VERSION 5.7 ;
  NOWIREEXTENSIONATPIN ON ;
  DIVIDERCHAR "/" ;
  BUSBITCHARS "[]" ;
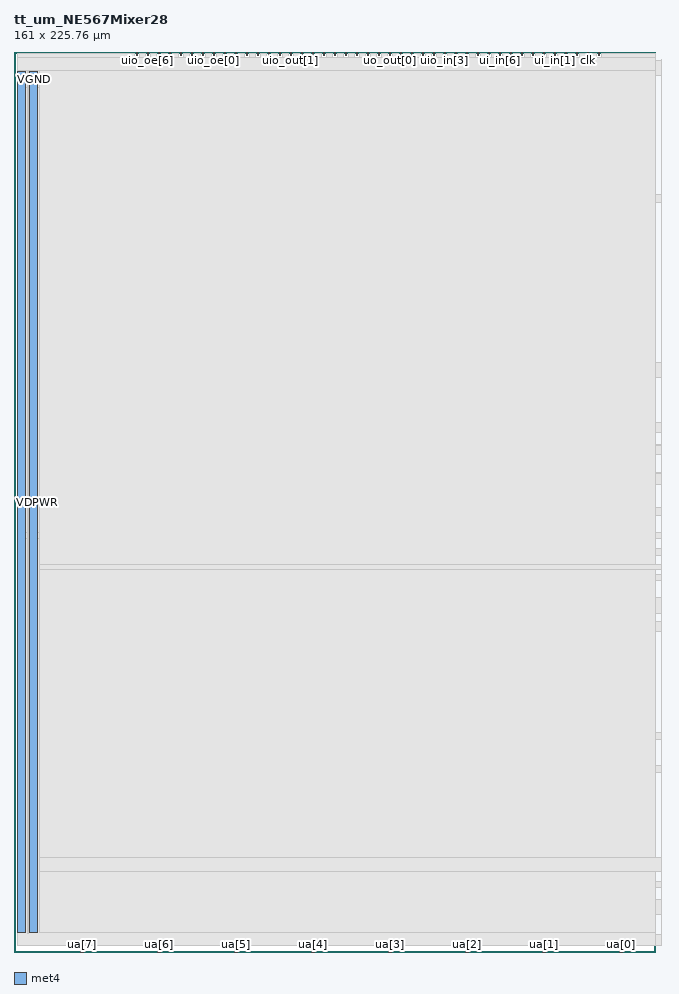
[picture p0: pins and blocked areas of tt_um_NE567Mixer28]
MACRO tt_um_NE567Mixer28
  CLASS BLOCK ;
  FOREIGN tt_um_NE567Mixer28 ;
  ORIGIN 0.000 0.000 ;
  SIZE 161.000 BY 225.760 ;
  PIN clk
    DIRECTION INPUT ;
    USE SIGNAL ;
    PORT
      LAYER met4 ;
        RECT 143.830 224.760 144.130 225.760 ;
    END
  END clk
  PIN ena
    DIRECTION INPUT ;
    USE SIGNAL ;
    PORT
      LAYER met4 ;
        RECT 146.590 224.760 146.890 225.760 ;
    END
  END ena
  PIN rst_n
    DIRECTION INPUT ;
    USE SIGNAL ;
    PORT
      LAYER met4 ;
        RECT 141.070 224.760 141.370 225.760 ;
    END
  END rst_n
  PIN ua[0]
    DIRECTION INOUT ;
    USE SIGNAL ;
    ANTENNADIFFAREA 2.320000 ;
    PORT
      LAYER met4 ;
        RECT 151.810 0.000 152.710 1.000 ;
    END
  END ua[0]
  PIN ua[1]
    DIRECTION INOUT ;
    USE SIGNAL ;
    ANTENNAGATEAREA 500.000000 ;
    PORT
      LAYER met4 ;
        RECT 132.490 0.000 133.390 1.000 ;
    END
  END ua[1]
  PIN ua[2]
    DIRECTION INOUT ;
    USE SIGNAL ;
    PORT
      LAYER met4 ;
        RECT 113.170 0.000 114.070 1.000 ;
    END
  END ua[2]
  PIN ua[3]
    DIRECTION INOUT ;
    USE SIGNAL ;
    ANTENNADIFFAREA 2.320000 ;
    PORT
      LAYER met4 ;
        RECT 93.850 0.000 94.750 1.000 ;
    END
  END ua[3]
  PIN ua[4]
    DIRECTION INOUT ;
    USE SIGNAL ;
    ANTENNAGATEAREA 500.000000 ;
    PORT
      LAYER met4 ;
        RECT 74.530 0.000 75.430 1.000 ;
    END
  END ua[4]
  PIN ua[5]
    DIRECTION INOUT ;
    USE SIGNAL ;
    ANTENNAGATEAREA 500.000000 ;
    PORT
      LAYER met4 ;
        RECT 55.210 0.000 56.110 1.000 ;
    END
  END ua[5]
  PIN ua[6]
    DIRECTION INOUT ;
    USE SIGNAL ;
    PORT
      LAYER met4 ;
        RECT 35.890 0.000 36.790 1.000 ;
    END
  END ua[6]
  PIN ua[7]
    DIRECTION INOUT ;
    USE SIGNAL ;
    PORT
      LAYER met4 ;
        RECT 16.570 0.000 17.470 1.000 ;
    END
  END ua[7]
  PIN ui_in[0]
    DIRECTION INPUT ;
    USE SIGNAL ;
    PORT
      LAYER met4 ;
        RECT 138.310 224.760 138.610 225.760 ;
    END
  END ui_in[0]
  PIN ui_in[1]
    DIRECTION INPUT ;
    USE SIGNAL ;
    PORT
      LAYER met4 ;
        RECT 135.550 224.760 135.850 225.760 ;
    END
  END ui_in[1]
  PIN ui_in[2]
    DIRECTION INPUT ;
    USE SIGNAL ;
    PORT
      LAYER met4 ;
        RECT 132.790 224.760 133.090 225.760 ;
    END
  END ui_in[2]
  PIN ui_in[3]
    DIRECTION INPUT ;
    USE SIGNAL ;
    PORT
      LAYER met4 ;
        RECT 130.030 224.760 130.330 225.760 ;
    END
  END ui_in[3]
  PIN ui_in[4]
    DIRECTION INPUT ;
    USE SIGNAL ;
    PORT
      LAYER met4 ;
        RECT 127.270 224.760 127.570 225.760 ;
    END
  END ui_in[4]
  PIN ui_in[5]
    DIRECTION INPUT ;
    USE SIGNAL ;
    PORT
      LAYER met4 ;
        RECT 124.510 224.760 124.810 225.760 ;
    END
  END ui_in[5]
  PIN ui_in[6]
    DIRECTION INPUT ;
    USE SIGNAL ;
    PORT
      LAYER met4 ;
        RECT 121.750 224.760 122.050 225.760 ;
    END
  END ui_in[6]
  PIN ui_in[7]
    DIRECTION INPUT ;
    USE SIGNAL ;
    PORT
      LAYER met4 ;
        RECT 118.990 224.760 119.290 225.760 ;
    END
  END ui_in[7]
  PIN uio_in[0]
    DIRECTION INPUT ;
    USE SIGNAL ;
    PORT
      LAYER met4 ;
        RECT 116.230 224.760 116.530 225.760 ;
    END
  END uio_in[0]
  PIN uio_in[1]
    DIRECTION INPUT ;
    USE SIGNAL ;
    PORT
      LAYER met4 ;
        RECT 113.470 224.760 113.770 225.760 ;
    END
  END uio_in[1]
  PIN uio_in[2]
    DIRECTION INPUT ;
    USE SIGNAL ;
    PORT
      LAYER met4 ;
        RECT 110.710 224.760 111.010 225.760 ;
    END
  END uio_in[2]
  PIN uio_in[3]
    DIRECTION INPUT ;
    USE SIGNAL ;
    PORT
      LAYER met4 ;
        RECT 107.950 224.760 108.250 225.760 ;
    END
  END uio_in[3]
  PIN uio_in[4]
    DIRECTION INPUT ;
    USE SIGNAL ;
    PORT
      LAYER met4 ;
        RECT 105.190 224.760 105.490 225.760 ;
    END
  END uio_in[4]
  PIN uio_in[5]
    DIRECTION INPUT ;
    USE SIGNAL ;
    PORT
      LAYER met4 ;
        RECT 102.430 224.760 102.730 225.760 ;
    END
  END uio_in[5]
  PIN uio_in[6]
    DIRECTION INPUT ;
    USE SIGNAL ;
    PORT
      LAYER met4 ;
        RECT 99.670 224.760 99.970 225.760 ;
    END
  END uio_in[6]
  PIN uio_in[7]
    DIRECTION INPUT ;
    USE SIGNAL ;
    PORT
      LAYER met4 ;
        RECT 96.910 224.760 97.210 225.760 ;
    END
  END uio_in[7]
  PIN uio_oe[0]
    DIRECTION OUTPUT ;
    USE SIGNAL ;
    ANTENNADIFFAREA 242.234787 ;
    PORT
      LAYER met4 ;
        RECT 49.990 224.760 50.290 225.760 ;
    END
  END uio_oe[0]
  PIN uio_oe[1]
    DIRECTION OUTPUT ;
    USE SIGNAL ;
    ANTENNADIFFAREA 242.234787 ;
    PORT
      LAYER met4 ;
        RECT 47.230 224.760 47.530 225.760 ;
    END
  END uio_oe[1]
  PIN uio_oe[2]
    DIRECTION OUTPUT ;
    USE SIGNAL ;
    ANTENNADIFFAREA 242.234787 ;
    PORT
      LAYER met4 ;
        RECT 44.470 224.760 44.770 225.760 ;
    END
  END uio_oe[2]
  PIN uio_oe[3]
    DIRECTION OUTPUT ;
    USE SIGNAL ;
    ANTENNADIFFAREA 242.234787 ;
    PORT
      LAYER met4 ;
        RECT 41.710 224.760 42.010 225.760 ;
    END
  END uio_oe[3]
  PIN uio_oe[4]
    DIRECTION OUTPUT ;
    USE SIGNAL ;
    ANTENNADIFFAREA 242.234787 ;
    PORT
      LAYER met4 ;
        RECT 38.950 224.760 39.250 225.760 ;
    END
  END uio_oe[4]
  PIN uio_oe[5]
    DIRECTION OUTPUT ;
    USE SIGNAL ;
    ANTENNADIFFAREA 242.234787 ;
    PORT
      LAYER met4 ;
        RECT 36.190 224.760 36.490 225.760 ;
    END
  END uio_oe[5]
  PIN uio_oe[6]
    DIRECTION OUTPUT ;
    USE SIGNAL ;
    ANTENNADIFFAREA 242.234787 ;
    PORT
      LAYER met4 ;
        RECT 33.430 224.760 33.730 225.760 ;
    END
  END uio_oe[6]
  PIN uio_oe[7]
    DIRECTION OUTPUT ;
    USE SIGNAL ;
    ANTENNADIFFAREA 242.234787 ;
    PORT
      LAYER met4 ;
        RECT 30.670 224.760 30.970 225.760 ;
    END
  END uio_oe[7]
  PIN uio_out[0]
    DIRECTION OUTPUT ;
    USE SIGNAL ;
    ANTENNADIFFAREA 242.234787 ;
    PORT
      LAYER met4 ;
        RECT 72.070 224.760 72.370 225.760 ;
    END
  END uio_out[0]
  PIN uio_out[1]
    DIRECTION OUTPUT ;
    USE SIGNAL ;
    ANTENNADIFFAREA 242.234787 ;
    PORT
      LAYER met4 ;
        RECT 69.310 224.760 69.610 225.760 ;
    END
  END uio_out[1]
  PIN uio_out[2]
    DIRECTION OUTPUT ;
    USE SIGNAL ;
    ANTENNADIFFAREA 242.234787 ;
    PORT
      LAYER met4 ;
        RECT 66.550 224.760 66.850 225.760 ;
    END
  END uio_out[2]
  PIN uio_out[3]
    DIRECTION OUTPUT ;
    USE SIGNAL ;
    ANTENNADIFFAREA 242.234787 ;
    PORT
      LAYER met4 ;
        RECT 63.790 224.760 64.090 225.760 ;
    END
  END uio_out[3]
  PIN uio_out[4]
    DIRECTION OUTPUT ;
    USE SIGNAL ;
    ANTENNADIFFAREA 242.234787 ;
    PORT
      LAYER met4 ;
        RECT 61.030 224.760 61.330 225.760 ;
    END
  END uio_out[4]
  PIN uio_out[5]
    DIRECTION OUTPUT ;
    USE SIGNAL ;
    ANTENNADIFFAREA 242.234787 ;
    PORT
      LAYER met4 ;
        RECT 58.270 224.760 58.570 225.760 ;
    END
  END uio_out[5]
  PIN uio_out[6]
    DIRECTION OUTPUT ;
    USE SIGNAL ;
    ANTENNADIFFAREA 242.234787 ;
    PORT
      LAYER met4 ;
        RECT 55.510 224.760 55.810 225.760 ;
    END
  END uio_out[6]
  PIN uio_out[7]
    DIRECTION OUTPUT ;
    USE SIGNAL ;
    ANTENNADIFFAREA 242.234787 ;
    PORT
      LAYER met4 ;
        RECT 52.750 224.760 53.050 225.760 ;
    END
  END uio_out[7]
  PIN uo_out[0]
    DIRECTION OUTPUT ;
    USE SIGNAL ;
    ANTENNADIFFAREA 242.234787 ;
    PORT
      LAYER met4 ;
        RECT 94.150 224.760 94.450 225.760 ;
    END
  END uo_out[0]
  PIN uo_out[1]
    DIRECTION OUTPUT ;
    USE SIGNAL ;
    ANTENNADIFFAREA 242.234787 ;
    PORT
      LAYER met4 ;
        RECT 91.390 224.760 91.690 225.760 ;
    END
  END uo_out[1]
  PIN uo_out[2]
    DIRECTION OUTPUT ;
    USE SIGNAL ;
    ANTENNADIFFAREA 242.234787 ;
    PORT
      LAYER met4 ;
        RECT 88.630 224.760 88.930 225.760 ;
    END
  END uo_out[2]
  PIN uo_out[3]
    DIRECTION OUTPUT ;
    USE SIGNAL ;
    ANTENNADIFFAREA 242.234787 ;
    PORT
      LAYER met4 ;
        RECT 85.870 224.760 86.170 225.760 ;
    END
  END uo_out[3]
  PIN uo_out[4]
    DIRECTION OUTPUT ;
    USE SIGNAL ;
    ANTENNADIFFAREA 242.234787 ;
    PORT
      LAYER met4 ;
        RECT 83.110 224.760 83.410 225.760 ;
    END
  END uo_out[4]
  PIN uo_out[5]
    DIRECTION OUTPUT ;
    USE SIGNAL ;
    ANTENNADIFFAREA 242.234787 ;
    PORT
      LAYER met4 ;
        RECT 80.350 224.760 80.650 225.760 ;
    END
  END uo_out[5]
  PIN uo_out[6]
    DIRECTION OUTPUT ;
    USE SIGNAL ;
    ANTENNADIFFAREA 242.234787 ;
    PORT
      LAYER met4 ;
        RECT 77.590 224.760 77.890 225.760 ;
    END
  END uo_out[6]
  PIN uo_out[7]
    DIRECTION OUTPUT ;
    USE SIGNAL ;
    ANTENNADIFFAREA 242.234787 ;
    PORT
      LAYER met4 ;
        RECT 74.830 224.760 75.130 225.760 ;
    END
  END uo_out[7]
  PIN VDPWR
    DIRECTION INOUT ;
    USE POWER ;
    PORT
      LAYER met4 ;
        RECT 1.000 5.000 3.000 220.760 ;
    END
  END VDPWR
  PIN VGND
    DIRECTION INOUT ;
    USE GROUND ;
    PORT
      LAYER met4 ;
        RECT 4.000 5.000 6.000 220.760 ;
    END
  END VGND
  OBS
      LAYER nwell ;
        RECT 40.830 17.360 161.000 218.560 ;
        RECT 252.020 207.610 275.390 217.020 ;
        RECT 281.650 214.020 287.690 218.210 ;
        RECT 303.010 213.970 309.050 218.160 ;
        RECT 281.700 207.940 287.890 212.130 ;
        RECT 302.900 207.780 309.090 211.970 ;
        RECT 481.630 207.960 505.000 217.370 ;
        RECT 511.260 214.370 517.300 218.560 ;
        RECT 532.620 214.320 538.660 218.510 ;
        RECT 511.310 208.290 517.500 212.480 ;
        RECT 532.510 208.130 538.700 212.320 ;
        RECT 252.050 180.340 280.420 202.590 ;
        RECT 291.650 180.340 320.020 202.590 ;
      LAYER pwell ;
        RECT 332.250 187.840 339.870 189.850 ;
      LAYER nwell ;
        RECT 481.660 180.690 510.030 202.940 ;
        RECT 521.260 180.690 549.630 202.940 ;
      LAYER pwell ;
        RECT 315.970 171.330 322.070 174.290 ;
        RECT 255.350 167.560 261.450 170.520 ;
        RECT 316.690 165.170 321.590 168.130 ;
        RECT 256.060 160.210 260.960 163.170 ;
        RECT 388.485 161.445 390.495 178.265 ;
        RECT 398.200 161.320 400.210 178.140 ;
        RECT 409.950 161.430 411.960 178.250 ;
        RECT 421.470 161.430 423.480 178.250 ;
        RECT 545.580 171.680 551.680 174.640 ;
        RECT 484.960 167.910 491.060 170.870 ;
        RECT 546.300 165.520 551.200 168.480 ;
        RECT 485.670 160.560 490.570 163.520 ;
        RECT 476.830 135.670 493.650 137.680 ;
        RECT 497.240 135.660 514.060 137.670 ;
        RECT 517.850 135.600 534.670 137.610 ;
        RECT 539.040 135.720 555.860 137.730 ;
        RECT 742.190 123.910 759.010 125.920 ;
        RECT 764.250 123.840 781.070 125.850 ;
        RECT 786.090 123.840 802.910 125.850 ;
        RECT 806.680 123.780 823.500 125.790 ;
      LAYER nwell ;
        RECT 300.530 73.270 323.900 82.680 ;
        RECT 330.160 79.680 336.200 83.870 ;
        RECT 351.520 79.630 357.560 83.820 ;
        RECT 330.210 73.600 336.400 77.790 ;
        RECT 351.410 73.440 357.600 77.630 ;
        RECT 574.920 73.120 598.290 82.530 ;
        RECT 604.550 79.530 610.590 83.720 ;
        RECT 625.910 79.480 631.950 83.670 ;
        RECT 604.600 73.450 610.790 77.640 ;
        RECT 625.800 73.290 631.990 77.480 ;
        RECT 766.380 73.120 789.750 82.530 ;
        RECT 796.010 79.530 802.050 83.720 ;
        RECT 817.370 79.480 823.410 83.670 ;
        RECT 796.060 73.450 802.250 77.640 ;
        RECT 817.260 73.290 823.450 77.480 ;
        RECT 300.560 46.000 328.930 68.250 ;
        RECT 340.160 46.000 368.530 68.250 ;
      LAYER pwell ;
        RECT 394.100 55.560 396.110 63.180 ;
      LAYER nwell ;
        RECT 574.950 45.850 603.320 68.100 ;
        RECT 614.550 45.850 642.920 68.100 ;
        RECT 766.410 45.850 794.780 68.100 ;
        RECT 806.010 45.850 834.380 68.100 ;
      LAYER pwell ;
        RECT 169.290 28.140 171.300 44.960 ;
        RECT 177.615 27.875 179.625 44.695 ;
        RECT 188.160 27.950 190.170 44.770 ;
        RECT 364.480 36.990 370.580 39.950 ;
        RECT 638.870 36.840 644.970 39.800 ;
        RECT 303.860 33.220 309.960 36.180 ;
        RECT 365.200 30.830 370.100 33.790 ;
        RECT 578.250 33.070 584.350 36.030 ;
        RECT 675.655 34.705 684.175 42.095 ;
        RECT 830.330 36.840 836.430 39.800 ;
        RECT 639.590 30.680 644.490 33.640 ;
        RECT 769.710 33.070 775.810 36.030 ;
        RECT 831.050 30.680 835.950 33.640 ;
        RECT 304.570 25.870 309.470 28.830 ;
        RECT 424.330 24.850 435.150 26.860 ;
        RECT 457.530 24.780 468.350 26.790 ;
        RECT 486.210 24.780 497.030 26.790 ;
        RECT 527.110 24.710 537.930 26.720 ;
        RECT 578.960 25.720 583.860 28.680 ;
        RECT 770.420 25.720 775.320 28.680 ;
        RECT 424.310 17.360 443.330 19.370 ;
        RECT 457.600 17.430 466.490 19.440 ;
        RECT 486.120 17.500 505.140 19.510 ;
        RECT 527.190 17.580 534.610 19.590 ;
      LAYER li1 ;
        RECT 40.940 17.450 161.000 218.680 ;
        RECT 513.580 218.380 514.770 218.680 ;
        RECT 283.970 218.030 285.160 218.330 ;
        RECT 511.440 218.210 517.120 218.380 ;
        RECT 535.090 218.330 536.270 218.410 ;
        RECT 281.830 217.860 287.510 218.030 ;
        RECT 305.480 217.980 306.660 218.060 ;
        RECT 270.600 216.840 272.580 216.970 ;
        RECT 252.200 216.670 275.210 216.840 ;
        RECT 252.200 207.960 252.370 216.670 ;
        RECT 270.600 216.570 272.580 216.670 ;
        RECT 253.095 216.100 263.135 216.270 ;
        RECT 264.275 216.100 274.315 216.270 ;
        RECT 252.710 215.040 252.880 216.040 ;
        RECT 263.350 215.040 263.520 216.040 ;
        RECT 263.890 215.040 264.060 216.040 ;
        RECT 274.530 215.040 274.700 216.040 ;
        RECT 253.095 214.810 263.135 214.980 ;
        RECT 264.275 214.810 274.315 214.980 ;
        RECT 252.710 213.750 252.880 214.750 ;
        RECT 263.350 213.750 263.520 214.750 ;
        RECT 263.890 213.750 264.060 214.750 ;
        RECT 274.530 213.750 274.700 214.750 ;
        RECT 253.095 213.520 263.135 213.690 ;
        RECT 264.275 213.520 274.315 213.690 ;
        RECT 252.710 212.460 252.880 213.460 ;
        RECT 263.350 212.460 263.520 213.460 ;
        RECT 263.890 212.460 264.060 213.460 ;
        RECT 274.530 212.460 274.700 213.460 ;
        RECT 253.095 212.230 263.135 212.400 ;
        RECT 264.275 212.230 274.315 212.400 ;
        RECT 252.710 211.170 252.880 212.170 ;
        RECT 263.350 211.170 263.520 212.170 ;
        RECT 263.890 211.170 264.060 212.170 ;
        RECT 274.530 211.170 274.700 212.170 ;
        RECT 253.095 210.940 263.135 211.110 ;
        RECT 264.275 210.940 274.315 211.110 ;
        RECT 252.710 209.880 252.880 210.880 ;
        RECT 263.350 209.880 263.520 210.880 ;
        RECT 263.890 209.880 264.060 210.880 ;
        RECT 274.530 209.880 274.700 210.880 ;
        RECT 253.095 209.650 263.135 209.820 ;
        RECT 264.275 209.650 274.315 209.820 ;
        RECT 252.710 208.590 252.880 209.590 ;
        RECT 263.350 208.590 263.520 209.590 ;
        RECT 263.890 208.590 264.060 209.590 ;
        RECT 274.530 208.590 274.700 209.590 ;
        RECT 253.095 208.360 263.135 208.530 ;
        RECT 264.275 208.360 274.315 208.530 ;
        RECT 275.040 207.960 275.210 216.670 ;
        RECT 281.830 214.370 282.000 217.860 ;
        RECT 283.970 217.740 285.160 217.860 ;
        RECT 282.725 217.290 286.615 217.460 ;
        RECT 282.340 215.000 282.510 217.230 ;
        RECT 286.830 215.000 287.000 217.230 ;
        RECT 282.725 214.770 286.615 214.940 ;
        RECT 287.340 214.370 287.510 217.860 ;
        RECT 281.830 214.200 287.510 214.370 ;
        RECT 303.190 217.810 308.870 217.980 ;
        RECT 303.190 214.320 303.360 217.810 ;
        RECT 305.480 217.730 306.660 217.810 ;
        RECT 304.085 217.240 307.975 217.410 ;
        RECT 303.700 214.950 303.870 217.180 ;
        RECT 308.190 214.950 308.360 217.180 ;
        RECT 304.085 214.720 307.975 214.890 ;
        RECT 308.700 214.320 308.870 217.810 ;
        RECT 500.210 217.190 502.190 217.320 ;
        RECT 303.190 214.150 308.870 214.320 ;
        RECT 481.810 217.020 504.820 217.190 ;
        RECT 284.100 211.950 285.250 212.050 ;
        RECT 281.880 211.780 287.710 211.950 ;
        RECT 305.260 211.790 306.630 211.860 ;
        RECT 281.880 208.290 282.050 211.780 ;
        RECT 284.100 211.700 285.250 211.780 ;
        RECT 282.775 211.210 286.815 211.380 ;
        RECT 282.390 208.920 282.560 211.150 ;
        RECT 287.030 208.920 287.200 211.150 ;
        RECT 282.775 208.690 286.815 208.860 ;
        RECT 287.540 208.290 287.710 211.780 ;
        RECT 281.880 208.120 287.710 208.290 ;
        RECT 303.080 211.620 308.910 211.790 ;
        RECT 303.080 208.130 303.250 211.620 ;
        RECT 305.260 211.490 306.630 211.620 ;
        RECT 303.975 211.050 308.015 211.220 ;
        RECT 303.590 208.760 303.760 210.990 ;
        RECT 308.230 208.760 308.400 210.990 ;
        RECT 303.975 208.530 308.015 208.700 ;
        RECT 308.740 208.130 308.910 211.620 ;
        RECT 481.810 208.310 481.980 217.020 ;
        RECT 500.210 216.920 502.190 217.020 ;
        RECT 482.705 216.450 492.745 216.620 ;
        RECT 493.885 216.450 503.925 216.620 ;
        RECT 482.320 215.390 482.490 216.390 ;
        RECT 492.960 215.390 493.130 216.390 ;
        RECT 493.500 215.390 493.670 216.390 ;
        RECT 504.140 215.390 504.310 216.390 ;
        RECT 482.705 215.160 492.745 215.330 ;
        RECT 493.885 215.160 503.925 215.330 ;
        RECT 482.320 214.100 482.490 215.100 ;
        RECT 492.960 214.100 493.130 215.100 ;
        RECT 493.500 214.100 493.670 215.100 ;
        RECT 504.140 214.100 504.310 215.100 ;
        RECT 482.705 213.870 492.745 214.040 ;
        RECT 493.885 213.870 503.925 214.040 ;
        RECT 482.320 212.810 482.490 213.810 ;
        RECT 492.960 212.810 493.130 213.810 ;
        RECT 493.500 212.810 493.670 213.810 ;
        RECT 504.140 212.810 504.310 213.810 ;
        RECT 482.705 212.580 492.745 212.750 ;
        RECT 493.885 212.580 503.925 212.750 ;
        RECT 482.320 211.520 482.490 212.520 ;
        RECT 492.960 211.520 493.130 212.520 ;
        RECT 493.500 211.520 493.670 212.520 ;
        RECT 504.140 211.520 504.310 212.520 ;
        RECT 482.705 211.290 492.745 211.460 ;
        RECT 493.885 211.290 503.925 211.460 ;
        RECT 482.320 210.230 482.490 211.230 ;
        RECT 492.960 210.230 493.130 211.230 ;
        RECT 493.500 210.230 493.670 211.230 ;
        RECT 504.140 210.230 504.310 211.230 ;
        RECT 482.705 210.000 492.745 210.170 ;
        RECT 493.885 210.000 503.925 210.170 ;
        RECT 482.320 208.940 482.490 209.940 ;
        RECT 492.960 208.940 493.130 209.940 ;
        RECT 493.500 208.940 493.670 209.940 ;
        RECT 504.140 208.940 504.310 209.940 ;
        RECT 482.705 208.710 492.745 208.880 ;
        RECT 493.885 208.710 503.925 208.880 ;
        RECT 504.650 208.310 504.820 217.020 ;
        RECT 511.440 214.720 511.610 218.210 ;
        RECT 513.580 218.090 514.770 218.210 ;
        RECT 512.335 217.640 516.225 217.810 ;
        RECT 511.950 215.350 512.120 217.580 ;
        RECT 516.440 215.350 516.610 217.580 ;
        RECT 512.335 215.120 516.225 215.290 ;
        RECT 516.950 214.720 517.120 218.210 ;
        RECT 511.440 214.550 517.120 214.720 ;
        RECT 532.800 218.160 538.480 218.330 ;
        RECT 532.800 214.670 532.970 218.160 ;
        RECT 535.090 218.080 536.270 218.160 ;
        RECT 533.695 217.590 537.585 217.760 ;
        RECT 533.310 215.300 533.480 217.530 ;
        RECT 537.800 215.300 537.970 217.530 ;
        RECT 533.695 215.070 537.585 215.240 ;
        RECT 538.310 214.670 538.480 218.160 ;
        RECT 532.800 214.500 538.480 214.670 ;
        RECT 513.710 212.300 514.860 212.400 ;
        RECT 511.490 212.130 517.320 212.300 ;
        RECT 534.870 212.140 536.240 212.210 ;
        RECT 511.490 208.640 511.660 212.130 ;
        RECT 513.710 212.050 514.860 212.130 ;
        RECT 512.385 211.560 516.425 211.730 ;
        RECT 512.000 209.270 512.170 211.500 ;
        RECT 516.640 209.270 516.810 211.500 ;
        RECT 512.385 209.040 516.425 209.210 ;
        RECT 517.150 208.640 517.320 212.130 ;
        RECT 511.490 208.470 517.320 208.640 ;
        RECT 532.690 211.970 538.520 212.140 ;
        RECT 532.690 208.480 532.860 211.970 ;
        RECT 534.870 211.840 536.240 211.970 ;
        RECT 533.585 211.400 537.625 211.570 ;
        RECT 533.200 209.110 533.370 211.340 ;
        RECT 537.840 209.110 538.010 211.340 ;
        RECT 533.585 208.880 537.625 209.050 ;
        RECT 538.350 208.480 538.520 211.970 ;
        RECT 532.690 208.310 538.520 208.480 ;
        RECT 481.810 208.140 504.820 208.310 ;
        RECT 303.080 207.960 308.910 208.130 ;
        RECT 252.200 207.790 275.210 207.960 ;
        RECT 487.930 202.760 490.700 202.850 ;
        RECT 527.440 202.760 529.820 202.910 ;
        RECT 481.840 202.590 509.850 202.760 ;
        RECT 258.320 202.410 261.090 202.500 ;
        RECT 297.830 202.410 300.210 202.560 ;
        RECT 252.230 202.240 280.240 202.410 ;
        RECT 252.230 180.690 252.400 202.240 ;
        RECT 258.320 202.200 261.090 202.240 ;
        RECT 253.125 201.670 265.665 201.840 ;
        RECT 266.805 201.670 279.345 201.840 ;
        RECT 252.740 191.610 252.910 201.610 ;
        RECT 265.880 191.610 266.050 201.610 ;
        RECT 266.420 191.610 266.590 201.610 ;
        RECT 279.560 191.610 279.730 201.610 ;
        RECT 253.125 191.380 265.665 191.550 ;
        RECT 266.805 191.380 279.345 191.550 ;
        RECT 252.740 181.320 252.910 191.320 ;
        RECT 265.880 181.320 266.050 191.320 ;
        RECT 266.420 181.320 266.590 191.320 ;
        RECT 279.560 181.320 279.730 191.320 ;
        RECT 253.125 181.090 265.665 181.260 ;
        RECT 266.805 181.090 279.345 181.260 ;
        RECT 280.070 180.690 280.240 202.240 ;
        RECT 252.230 180.520 280.240 180.690 ;
        RECT 291.830 202.240 319.840 202.410 ;
        RECT 291.830 180.690 292.000 202.240 ;
        RECT 297.830 202.140 300.210 202.240 ;
        RECT 292.725 201.670 305.265 201.840 ;
        RECT 306.405 201.670 318.945 201.840 ;
        RECT 292.340 191.610 292.510 201.610 ;
        RECT 305.480 191.610 305.650 201.610 ;
        RECT 306.020 191.610 306.190 201.610 ;
        RECT 319.160 191.610 319.330 201.610 ;
        RECT 292.725 191.380 305.265 191.550 ;
        RECT 306.405 191.380 318.945 191.550 ;
        RECT 292.340 181.320 292.510 191.320 ;
        RECT 305.480 181.320 305.650 191.320 ;
        RECT 306.020 181.320 306.190 191.320 ;
        RECT 319.160 181.320 319.330 191.320 ;
        RECT 292.725 181.090 305.265 181.260 ;
        RECT 306.405 181.090 318.945 181.260 ;
        RECT 319.670 180.690 319.840 202.240 ;
        RECT 332.430 189.500 339.690 189.670 ;
        RECT 332.430 188.190 332.600 189.500 ;
        RECT 333.080 188.670 335.240 189.020 ;
        RECT 336.880 188.670 339.040 189.020 ;
        RECT 335.650 188.190 336.600 188.280 ;
        RECT 339.520 188.190 339.690 189.500 ;
        RECT 332.430 188.020 339.690 188.190 ;
        RECT 335.650 187.900 336.600 188.020 ;
        RECT 481.840 181.040 482.010 202.590 ;
        RECT 487.930 202.550 490.700 202.590 ;
        RECT 482.735 202.020 495.275 202.190 ;
        RECT 496.415 202.020 508.955 202.190 ;
        RECT 482.350 191.960 482.520 201.960 ;
        RECT 495.490 191.960 495.660 201.960 ;
        RECT 496.030 191.960 496.200 201.960 ;
        RECT 509.170 191.960 509.340 201.960 ;
        RECT 482.735 191.730 495.275 191.900 ;
        RECT 496.415 191.730 508.955 191.900 ;
        RECT 482.350 181.670 482.520 191.670 ;
        RECT 495.490 181.670 495.660 191.670 ;
        RECT 496.030 181.670 496.200 191.670 ;
        RECT 509.170 181.670 509.340 191.670 ;
        RECT 482.735 181.440 495.275 181.610 ;
        RECT 496.415 181.440 508.955 181.610 ;
        RECT 509.680 181.040 509.850 202.590 ;
        RECT 481.840 180.870 509.850 181.040 ;
        RECT 521.440 202.590 549.450 202.760 ;
        RECT 521.440 181.040 521.610 202.590 ;
        RECT 527.440 202.490 529.820 202.590 ;
        RECT 522.335 202.020 534.875 202.190 ;
        RECT 536.015 202.020 548.555 202.190 ;
        RECT 521.950 191.960 522.120 201.960 ;
        RECT 535.090 191.960 535.260 201.960 ;
        RECT 535.630 191.960 535.800 201.960 ;
        RECT 548.770 191.960 548.940 201.960 ;
        RECT 522.335 191.730 534.875 191.900 ;
        RECT 536.015 191.730 548.555 191.900 ;
        RECT 521.950 181.670 522.120 191.670 ;
        RECT 535.090 181.670 535.260 191.670 ;
        RECT 535.630 181.670 535.800 191.670 ;
        RECT 548.770 181.670 548.940 191.670 ;
        RECT 522.335 181.440 534.875 181.610 ;
        RECT 536.015 181.440 548.555 181.610 ;
        RECT 549.280 181.040 549.450 202.590 ;
        RECT 521.440 180.870 549.450 181.040 ;
        RECT 291.830 180.520 319.840 180.690 ;
        RECT 388.665 177.915 390.315 178.085 ;
        RECT 316.150 173.940 321.890 174.110 ;
        RECT 316.150 171.680 316.320 173.940 ;
        RECT 317.000 173.370 321.040 173.540 ;
        RECT 316.660 172.310 316.830 173.310 ;
        RECT 321.210 172.310 321.380 173.310 ;
        RECT 317.000 172.080 321.040 172.250 ;
        RECT 316.680 171.680 317.700 171.790 ;
        RECT 321.720 171.680 321.890 173.940 ;
        RECT 316.150 171.510 321.890 171.680 ;
        RECT 316.680 171.390 317.700 171.510 ;
        RECT 255.530 170.170 261.270 170.340 ;
        RECT 255.530 169.440 255.700 170.170 ;
        RECT 256.380 169.600 260.420 169.770 ;
        RECT 255.440 168.560 255.800 169.440 ;
        RECT 255.530 167.910 255.700 168.560 ;
        RECT 256.040 168.540 256.210 169.540 ;
        RECT 260.590 168.540 260.760 169.540 ;
        RECT 256.380 168.310 260.420 168.480 ;
        RECT 261.100 167.910 261.270 170.170 ;
        RECT 316.900 167.950 317.800 168.070 ;
        RECT 255.530 167.740 261.270 167.910 ;
        RECT 316.870 167.780 321.410 167.950 ;
        RECT 316.870 167.730 317.800 167.780 ;
        RECT 316.870 165.520 317.040 167.730 ;
        RECT 317.720 167.210 320.560 167.380 ;
        RECT 317.380 166.150 317.550 167.150 ;
        RECT 320.730 166.150 320.900 167.150 ;
        RECT 317.720 165.920 320.560 166.090 ;
        RECT 318.600 165.520 319.840 165.630 ;
        RECT 321.240 165.520 321.410 167.780 ;
        RECT 316.870 165.350 321.410 165.520 ;
        RECT 318.600 165.140 319.840 165.350 ;
        RECT 256.240 162.820 260.780 162.990 ;
        RECT 256.240 160.560 256.410 162.820 ;
        RECT 257.090 162.250 259.930 162.420 ;
        RECT 256.750 161.190 256.920 162.190 ;
        RECT 260.100 161.190 260.270 162.190 ;
        RECT 257.090 160.960 259.930 161.130 ;
        RECT 258.030 160.560 259.010 160.690 ;
        RECT 260.610 160.560 260.780 162.820 ;
        RECT 388.665 161.795 388.835 177.915 ;
        RECT 389.315 175.275 389.665 177.435 ;
        RECT 389.315 162.275 389.665 164.435 ;
        RECT 390.145 161.795 390.315 177.915 ;
        RECT 388.665 161.625 390.315 161.795 ;
        RECT 398.380 177.790 400.030 177.960 ;
        RECT 398.380 161.670 398.550 177.790 ;
        RECT 399.030 175.150 399.380 177.310 ;
        RECT 399.030 162.150 399.380 164.310 ;
        RECT 398.800 161.670 399.570 161.730 ;
        RECT 399.860 161.670 400.030 177.790 ;
        RECT 389.060 161.560 389.920 161.625 ;
        RECT 398.380 161.500 400.030 161.670 ;
        RECT 410.130 177.900 411.780 178.070 ;
        RECT 410.130 161.780 410.300 177.900 ;
        RECT 410.780 175.260 411.130 177.420 ;
        RECT 410.780 162.260 411.130 164.420 ;
        RECT 410.570 161.780 411.340 161.880 ;
        RECT 411.610 161.780 411.780 177.900 ;
        RECT 410.130 161.610 411.780 161.780 ;
        RECT 421.650 177.900 423.300 178.070 ;
        RECT 421.650 161.780 421.820 177.900 ;
        RECT 422.300 175.260 422.650 177.420 ;
        RECT 422.300 162.260 422.650 164.420 ;
        RECT 422.160 161.780 422.930 161.880 ;
        RECT 423.130 161.780 423.300 177.900 ;
        RECT 545.760 174.290 551.500 174.460 ;
        RECT 545.760 172.030 545.930 174.290 ;
        RECT 546.610 173.720 550.650 173.890 ;
        RECT 546.270 172.660 546.440 173.660 ;
        RECT 550.820 172.660 550.990 173.660 ;
        RECT 546.610 172.430 550.650 172.600 ;
        RECT 546.290 172.030 547.310 172.140 ;
        RECT 551.330 172.030 551.500 174.290 ;
        RECT 545.760 171.860 551.500 172.030 ;
        RECT 546.290 171.740 547.310 171.860 ;
        RECT 485.140 170.520 490.880 170.690 ;
        RECT 485.140 169.790 485.310 170.520 ;
        RECT 485.990 169.950 490.030 170.120 ;
        RECT 485.050 168.910 485.410 169.790 ;
        RECT 485.140 168.260 485.310 168.910 ;
        RECT 485.650 168.890 485.820 169.890 ;
        RECT 490.200 168.890 490.370 169.890 ;
        RECT 485.990 168.660 490.030 168.830 ;
        RECT 490.710 168.260 490.880 170.520 ;
        RECT 546.510 168.300 547.410 168.420 ;
        RECT 485.140 168.090 490.880 168.260 ;
        RECT 546.480 168.130 551.020 168.300 ;
        RECT 546.480 168.080 547.410 168.130 ;
        RECT 546.480 165.870 546.650 168.080 ;
        RECT 547.330 167.560 550.170 167.730 ;
        RECT 546.990 166.500 547.160 167.500 ;
        RECT 550.340 166.500 550.510 167.500 ;
        RECT 547.330 166.270 550.170 166.440 ;
        RECT 548.210 165.870 549.450 165.980 ;
        RECT 550.850 165.870 551.020 168.130 ;
        RECT 546.480 165.700 551.020 165.870 ;
        RECT 548.210 165.490 549.450 165.700 ;
        RECT 421.650 161.610 423.300 161.780 ;
        RECT 485.850 163.170 490.390 163.340 ;
        RECT 410.570 161.520 411.340 161.610 ;
        RECT 422.160 161.520 422.930 161.610 ;
        RECT 398.800 161.370 399.570 161.500 ;
        RECT 485.850 160.910 486.020 163.170 ;
        RECT 486.700 162.600 489.540 162.770 ;
        RECT 486.360 161.540 486.530 162.540 ;
        RECT 489.710 161.540 489.880 162.540 ;
        RECT 486.700 161.310 489.540 161.480 ;
        RECT 487.640 160.910 488.620 161.040 ;
        RECT 490.220 160.910 490.390 163.170 ;
        RECT 485.850 160.740 490.390 160.910 ;
        RECT 487.640 160.590 488.620 160.740 ;
        RECT 256.240 160.390 260.780 160.560 ;
        RECT 258.030 160.240 259.010 160.390 ;
        RECT 484.410 137.500 486.030 137.600 ;
        RECT 477.010 137.330 493.470 137.500 ;
        RECT 504.790 137.490 506.410 137.600 ;
        RECT 546.640 137.550 548.260 137.610 ;
        RECT 477.010 136.020 477.180 137.330 ;
        RECT 484.410 137.240 486.030 137.330 ;
        RECT 477.660 136.500 479.820 136.850 ;
        RECT 490.660 136.500 492.820 136.850 ;
        RECT 493.300 136.020 493.470 137.330 ;
        RECT 477.010 135.850 493.470 136.020 ;
        RECT 497.420 137.320 513.880 137.490 ;
        RECT 525.390 137.430 527.010 137.530 ;
        RECT 497.420 136.010 497.590 137.320 ;
        RECT 504.790 137.240 506.410 137.320 ;
        RECT 498.070 136.490 500.230 136.840 ;
        RECT 511.070 136.490 513.230 136.840 ;
        RECT 513.710 136.010 513.880 137.320 ;
        RECT 497.420 135.840 513.880 136.010 ;
        RECT 518.030 137.260 534.490 137.430 ;
        RECT 518.030 135.950 518.200 137.260 ;
        RECT 525.390 137.170 527.010 137.260 ;
        RECT 518.680 136.430 520.840 136.780 ;
        RECT 531.680 136.430 533.840 136.780 ;
        RECT 534.320 135.950 534.490 137.260 ;
        RECT 518.030 135.780 534.490 135.950 ;
        RECT 539.220 137.380 555.680 137.550 ;
        RECT 539.220 136.070 539.390 137.380 ;
        RECT 546.640 137.250 548.260 137.380 ;
        RECT 539.870 136.550 542.030 136.900 ;
        RECT 552.870 136.550 555.030 136.900 ;
        RECT 555.510 136.070 555.680 137.380 ;
        RECT 539.220 135.900 555.680 136.070 ;
        RECT 742.370 125.570 758.830 125.740 ;
        RECT 742.370 124.260 742.540 125.570 ;
        RECT 743.020 124.740 745.180 125.090 ;
        RECT 756.020 124.740 758.180 125.090 ;
        RECT 748.800 124.260 751.700 124.450 ;
        RECT 758.660 124.260 758.830 125.570 ;
        RECT 742.370 124.090 758.830 124.260 ;
        RECT 764.430 125.500 780.890 125.670 ;
        RECT 764.430 124.190 764.600 125.500 ;
        RECT 765.080 124.670 767.240 125.020 ;
        RECT 778.080 124.670 780.240 125.020 ;
        RECT 771.500 124.190 774.400 124.370 ;
        RECT 780.720 124.190 780.890 125.500 ;
        RECT 748.800 123.960 751.700 124.090 ;
        RECT 764.430 124.020 780.890 124.190 ;
        RECT 786.270 125.500 802.730 125.670 ;
        RECT 786.270 124.190 786.440 125.500 ;
        RECT 786.920 124.670 789.080 125.020 ;
        RECT 799.920 124.670 802.080 125.020 ;
        RECT 792.960 124.190 795.860 124.290 ;
        RECT 802.560 124.190 802.730 125.500 ;
        RECT 786.270 124.020 802.730 124.190 ;
        RECT 806.860 125.440 823.320 125.610 ;
        RECT 806.860 124.130 807.030 125.440 ;
        RECT 807.510 124.610 809.670 124.960 ;
        RECT 820.510 124.610 822.670 124.960 ;
        RECT 813.610 124.130 816.510 124.260 ;
        RECT 823.150 124.130 823.320 125.440 ;
        RECT 771.500 123.880 774.400 124.020 ;
        RECT 792.960 123.800 795.860 124.020 ;
        RECT 806.860 123.960 823.320 124.130 ;
        RECT 813.610 123.770 816.510 123.960 ;
        RECT 332.480 83.690 333.670 83.990 ;
        RECT 330.340 83.520 336.020 83.690 ;
        RECT 353.990 83.640 355.170 83.720 ;
        RECT 319.110 82.500 321.090 82.630 ;
        RECT 300.710 82.330 323.720 82.500 ;
        RECT 300.710 73.620 300.880 82.330 ;
        RECT 319.110 82.230 321.090 82.330 ;
        RECT 301.605 81.760 311.645 81.930 ;
        RECT 312.785 81.760 322.825 81.930 ;
        RECT 301.220 80.700 301.390 81.700 ;
        RECT 311.860 80.700 312.030 81.700 ;
        RECT 312.400 80.700 312.570 81.700 ;
        RECT 323.040 80.700 323.210 81.700 ;
        RECT 301.605 80.470 311.645 80.640 ;
        RECT 312.785 80.470 322.825 80.640 ;
        RECT 301.220 79.410 301.390 80.410 ;
        RECT 311.860 79.410 312.030 80.410 ;
        RECT 312.400 79.410 312.570 80.410 ;
        RECT 323.040 79.410 323.210 80.410 ;
        RECT 301.605 79.180 311.645 79.350 ;
        RECT 312.785 79.180 322.825 79.350 ;
        RECT 301.220 78.120 301.390 79.120 ;
        RECT 311.860 78.120 312.030 79.120 ;
        RECT 312.400 78.120 312.570 79.120 ;
        RECT 323.040 78.120 323.210 79.120 ;
        RECT 301.605 77.890 311.645 78.060 ;
        RECT 312.785 77.890 322.825 78.060 ;
        RECT 301.220 76.830 301.390 77.830 ;
        RECT 311.860 76.830 312.030 77.830 ;
        RECT 312.400 76.830 312.570 77.830 ;
        RECT 323.040 76.830 323.210 77.830 ;
        RECT 301.605 76.600 311.645 76.770 ;
        RECT 312.785 76.600 322.825 76.770 ;
        RECT 301.220 75.540 301.390 76.540 ;
        RECT 311.860 75.540 312.030 76.540 ;
        RECT 312.400 75.540 312.570 76.540 ;
        RECT 323.040 75.540 323.210 76.540 ;
        RECT 301.605 75.310 311.645 75.480 ;
        RECT 312.785 75.310 322.825 75.480 ;
        RECT 301.220 74.250 301.390 75.250 ;
        RECT 311.860 74.250 312.030 75.250 ;
        RECT 312.400 74.250 312.570 75.250 ;
        RECT 323.040 74.250 323.210 75.250 ;
        RECT 301.605 74.020 311.645 74.190 ;
        RECT 312.785 74.020 322.825 74.190 ;
        RECT 323.550 73.620 323.720 82.330 ;
        RECT 330.340 80.030 330.510 83.520 ;
        RECT 332.480 83.400 333.670 83.520 ;
        RECT 331.235 82.950 335.125 83.120 ;
        RECT 330.850 80.660 331.020 82.890 ;
        RECT 335.340 80.660 335.510 82.890 ;
        RECT 331.235 80.430 335.125 80.600 ;
        RECT 335.850 80.030 336.020 83.520 ;
        RECT 330.340 79.860 336.020 80.030 ;
        RECT 351.700 83.470 357.380 83.640 ;
        RECT 606.870 83.540 608.060 83.840 ;
        RECT 351.700 79.980 351.870 83.470 ;
        RECT 353.990 83.390 355.170 83.470 ;
        RECT 352.595 82.900 356.485 83.070 ;
        RECT 352.210 80.610 352.380 82.840 ;
        RECT 356.700 80.610 356.870 82.840 ;
        RECT 352.595 80.380 356.485 80.550 ;
        RECT 357.210 79.980 357.380 83.470 ;
        RECT 604.730 83.370 610.410 83.540 ;
        RECT 628.380 83.490 629.560 83.570 ;
        RECT 798.330 83.540 799.520 83.840 ;
        RECT 593.500 82.350 595.480 82.480 ;
        RECT 351.700 79.810 357.380 79.980 ;
        RECT 575.100 82.180 598.110 82.350 ;
        RECT 332.610 77.610 333.760 77.710 ;
        RECT 330.390 77.440 336.220 77.610 ;
        RECT 353.770 77.450 355.140 77.520 ;
        RECT 330.390 73.950 330.560 77.440 ;
        RECT 332.610 77.360 333.760 77.440 ;
        RECT 331.285 76.870 335.325 77.040 ;
        RECT 330.900 74.580 331.070 76.810 ;
        RECT 335.540 74.580 335.710 76.810 ;
        RECT 331.285 74.350 335.325 74.520 ;
        RECT 336.050 73.950 336.220 77.440 ;
        RECT 330.390 73.780 336.220 73.950 ;
        RECT 351.590 77.280 357.420 77.450 ;
        RECT 351.590 73.790 351.760 77.280 ;
        RECT 353.770 77.150 355.140 77.280 ;
        RECT 352.485 76.710 356.525 76.880 ;
        RECT 352.100 74.420 352.270 76.650 ;
        RECT 356.740 74.420 356.910 76.650 ;
        RECT 352.485 74.190 356.525 74.360 ;
        RECT 357.250 73.790 357.420 77.280 ;
        RECT 351.590 73.620 357.420 73.790 ;
        RECT 300.710 73.450 323.720 73.620 ;
        RECT 575.100 73.470 575.270 82.180 ;
        RECT 593.500 82.080 595.480 82.180 ;
        RECT 575.995 81.610 586.035 81.780 ;
        RECT 587.175 81.610 597.215 81.780 ;
        RECT 575.610 80.550 575.780 81.550 ;
        RECT 586.250 80.550 586.420 81.550 ;
        RECT 586.790 80.550 586.960 81.550 ;
        RECT 597.430 80.550 597.600 81.550 ;
        RECT 575.995 80.320 586.035 80.490 ;
        RECT 587.175 80.320 597.215 80.490 ;
        RECT 575.610 79.260 575.780 80.260 ;
        RECT 586.250 79.260 586.420 80.260 ;
        RECT 586.790 79.260 586.960 80.260 ;
        RECT 597.430 79.260 597.600 80.260 ;
        RECT 575.995 79.030 586.035 79.200 ;
        RECT 587.175 79.030 597.215 79.200 ;
        RECT 575.610 77.970 575.780 78.970 ;
        RECT 586.250 77.970 586.420 78.970 ;
        RECT 586.790 77.970 586.960 78.970 ;
        RECT 597.430 77.970 597.600 78.970 ;
        RECT 575.995 77.740 586.035 77.910 ;
        RECT 587.175 77.740 597.215 77.910 ;
        RECT 575.610 76.680 575.780 77.680 ;
        RECT 586.250 76.680 586.420 77.680 ;
        RECT 586.790 76.680 586.960 77.680 ;
        RECT 597.430 76.680 597.600 77.680 ;
        RECT 575.995 76.450 586.035 76.620 ;
        RECT 587.175 76.450 597.215 76.620 ;
        RECT 575.610 75.390 575.780 76.390 ;
        RECT 586.250 75.390 586.420 76.390 ;
        RECT 586.790 75.390 586.960 76.390 ;
        RECT 597.430 75.390 597.600 76.390 ;
        RECT 575.995 75.160 586.035 75.330 ;
        RECT 587.175 75.160 597.215 75.330 ;
        RECT 575.610 74.100 575.780 75.100 ;
        RECT 586.250 74.100 586.420 75.100 ;
        RECT 586.790 74.100 586.960 75.100 ;
        RECT 597.430 74.100 597.600 75.100 ;
        RECT 575.995 73.870 586.035 74.040 ;
        RECT 587.175 73.870 597.215 74.040 ;
        RECT 597.940 73.470 598.110 82.180 ;
        RECT 604.730 79.880 604.900 83.370 ;
        RECT 606.870 83.250 608.060 83.370 ;
        RECT 605.625 82.800 609.515 82.970 ;
        RECT 605.240 80.510 605.410 82.740 ;
        RECT 609.730 80.510 609.900 82.740 ;
        RECT 605.625 80.280 609.515 80.450 ;
        RECT 610.240 79.880 610.410 83.370 ;
        RECT 604.730 79.710 610.410 79.880 ;
        RECT 626.090 83.320 631.770 83.490 ;
        RECT 626.090 79.830 626.260 83.320 ;
        RECT 628.380 83.240 629.560 83.320 ;
        RECT 626.985 82.750 630.875 82.920 ;
        RECT 626.600 80.460 626.770 82.690 ;
        RECT 631.090 80.460 631.260 82.690 ;
        RECT 626.985 80.230 630.875 80.400 ;
        RECT 631.600 79.830 631.770 83.320 ;
        RECT 796.190 83.370 801.870 83.540 ;
        RECT 819.840 83.490 821.020 83.570 ;
        RECT 784.960 82.350 786.940 82.480 ;
        RECT 626.090 79.660 631.770 79.830 ;
        RECT 766.560 82.180 789.570 82.350 ;
        RECT 607.000 77.460 608.150 77.560 ;
        RECT 604.780 77.290 610.610 77.460 ;
        RECT 628.160 77.300 629.530 77.370 ;
        RECT 604.780 73.800 604.950 77.290 ;
        RECT 607.000 77.210 608.150 77.290 ;
        RECT 605.675 76.720 609.715 76.890 ;
        RECT 605.290 74.430 605.460 76.660 ;
        RECT 609.930 74.430 610.100 76.660 ;
        RECT 605.675 74.200 609.715 74.370 ;
        RECT 610.440 73.800 610.610 77.290 ;
        RECT 604.780 73.630 610.610 73.800 ;
        RECT 625.980 77.130 631.810 77.300 ;
        RECT 625.980 73.640 626.150 77.130 ;
        RECT 628.160 77.000 629.530 77.130 ;
        RECT 626.875 76.560 630.915 76.730 ;
        RECT 626.490 74.270 626.660 76.500 ;
        RECT 631.130 74.270 631.300 76.500 ;
        RECT 626.875 74.040 630.915 74.210 ;
        RECT 631.640 73.640 631.810 77.130 ;
        RECT 625.980 73.470 631.810 73.640 ;
        RECT 766.560 73.470 766.730 82.180 ;
        RECT 784.960 82.080 786.940 82.180 ;
        RECT 767.455 81.610 777.495 81.780 ;
        RECT 778.635 81.610 788.675 81.780 ;
        RECT 767.070 80.550 767.240 81.550 ;
        RECT 777.710 80.550 777.880 81.550 ;
        RECT 778.250 80.550 778.420 81.550 ;
        RECT 788.890 80.550 789.060 81.550 ;
        RECT 767.455 80.320 777.495 80.490 ;
        RECT 778.635 80.320 788.675 80.490 ;
        RECT 767.070 79.260 767.240 80.260 ;
        RECT 777.710 79.260 777.880 80.260 ;
        RECT 778.250 79.260 778.420 80.260 ;
        RECT 788.890 79.260 789.060 80.260 ;
        RECT 767.455 79.030 777.495 79.200 ;
        RECT 778.635 79.030 788.675 79.200 ;
        RECT 767.070 77.970 767.240 78.970 ;
        RECT 777.710 77.970 777.880 78.970 ;
        RECT 778.250 77.970 778.420 78.970 ;
        RECT 788.890 77.970 789.060 78.970 ;
        RECT 767.455 77.740 777.495 77.910 ;
        RECT 778.635 77.740 788.675 77.910 ;
        RECT 767.070 76.680 767.240 77.680 ;
        RECT 777.710 76.680 777.880 77.680 ;
        RECT 778.250 76.680 778.420 77.680 ;
        RECT 788.890 76.680 789.060 77.680 ;
        RECT 767.455 76.450 777.495 76.620 ;
        RECT 778.635 76.450 788.675 76.620 ;
        RECT 767.070 75.390 767.240 76.390 ;
        RECT 777.710 75.390 777.880 76.390 ;
        RECT 778.250 75.390 778.420 76.390 ;
        RECT 788.890 75.390 789.060 76.390 ;
        RECT 767.455 75.160 777.495 75.330 ;
        RECT 778.635 75.160 788.675 75.330 ;
        RECT 767.070 74.100 767.240 75.100 ;
        RECT 777.710 74.100 777.880 75.100 ;
        RECT 778.250 74.100 778.420 75.100 ;
        RECT 788.890 74.100 789.060 75.100 ;
        RECT 767.455 73.870 777.495 74.040 ;
        RECT 778.635 73.870 788.675 74.040 ;
        RECT 789.400 73.470 789.570 82.180 ;
        RECT 796.190 79.880 796.360 83.370 ;
        RECT 798.330 83.250 799.520 83.370 ;
        RECT 797.085 82.800 800.975 82.970 ;
        RECT 796.700 80.510 796.870 82.740 ;
        RECT 801.190 80.510 801.360 82.740 ;
        RECT 797.085 80.280 800.975 80.450 ;
        RECT 801.700 79.880 801.870 83.370 ;
        RECT 796.190 79.710 801.870 79.880 ;
        RECT 817.550 83.320 823.230 83.490 ;
        RECT 817.550 79.830 817.720 83.320 ;
        RECT 819.840 83.240 821.020 83.320 ;
        RECT 818.445 82.750 822.335 82.920 ;
        RECT 818.060 80.460 818.230 82.690 ;
        RECT 822.550 80.460 822.720 82.690 ;
        RECT 818.445 80.230 822.335 80.400 ;
        RECT 823.060 79.830 823.230 83.320 ;
        RECT 817.550 79.660 823.230 79.830 ;
        RECT 798.460 77.460 799.610 77.560 ;
        RECT 796.240 77.290 802.070 77.460 ;
        RECT 819.620 77.300 820.990 77.370 ;
        RECT 796.240 73.800 796.410 77.290 ;
        RECT 798.460 77.210 799.610 77.290 ;
        RECT 797.135 76.720 801.175 76.890 ;
        RECT 796.750 74.430 796.920 76.660 ;
        RECT 801.390 74.430 801.560 76.660 ;
        RECT 797.135 74.200 801.175 74.370 ;
        RECT 801.900 73.800 802.070 77.290 ;
        RECT 796.240 73.630 802.070 73.800 ;
        RECT 817.440 77.130 823.270 77.300 ;
        RECT 817.440 73.640 817.610 77.130 ;
        RECT 819.620 77.000 820.990 77.130 ;
        RECT 818.335 76.560 822.375 76.730 ;
        RECT 817.950 74.270 818.120 76.500 ;
        RECT 822.590 74.270 822.760 76.500 ;
        RECT 818.335 74.040 822.375 74.210 ;
        RECT 823.100 73.640 823.270 77.130 ;
        RECT 817.440 73.470 823.270 73.640 ;
        RECT 575.100 73.300 598.110 73.470 ;
        RECT 766.560 73.300 789.570 73.470 ;
        RECT 306.830 68.070 309.600 68.160 ;
        RECT 346.340 68.070 348.720 68.220 ;
        RECT 300.740 67.900 328.750 68.070 ;
        RECT 300.740 46.350 300.910 67.900 ;
        RECT 306.830 67.860 309.600 67.900 ;
        RECT 301.635 67.330 314.175 67.500 ;
        RECT 315.315 67.330 327.855 67.500 ;
        RECT 301.250 57.270 301.420 67.270 ;
        RECT 314.390 57.270 314.560 67.270 ;
        RECT 314.930 57.270 315.100 67.270 ;
        RECT 328.070 57.270 328.240 67.270 ;
        RECT 301.635 57.040 314.175 57.210 ;
        RECT 315.315 57.040 327.855 57.210 ;
        RECT 301.250 46.980 301.420 56.980 ;
        RECT 314.390 46.980 314.560 56.980 ;
        RECT 314.930 46.980 315.100 56.980 ;
        RECT 328.070 46.980 328.240 56.980 ;
        RECT 301.635 46.750 314.175 46.920 ;
        RECT 315.315 46.750 327.855 46.920 ;
        RECT 328.580 46.350 328.750 67.900 ;
        RECT 300.740 46.180 328.750 46.350 ;
        RECT 340.340 67.900 368.350 68.070 ;
        RECT 581.220 67.920 583.990 68.010 ;
        RECT 620.730 67.920 623.110 68.070 ;
        RECT 772.680 67.920 775.450 68.010 ;
        RECT 812.190 67.920 814.570 68.070 ;
        RECT 340.340 46.350 340.510 67.900 ;
        RECT 346.340 67.800 348.720 67.900 ;
        RECT 341.235 67.330 353.775 67.500 ;
        RECT 354.915 67.330 367.455 67.500 ;
        RECT 340.850 57.270 341.020 67.270 ;
        RECT 353.990 57.270 354.160 67.270 ;
        RECT 354.530 57.270 354.700 67.270 ;
        RECT 367.670 57.270 367.840 67.270 ;
        RECT 341.235 57.040 353.775 57.210 ;
        RECT 354.915 57.040 367.455 57.210 ;
        RECT 340.850 46.980 341.020 56.980 ;
        RECT 353.990 46.980 354.160 56.980 ;
        RECT 354.530 46.980 354.700 56.980 ;
        RECT 367.670 46.980 367.840 56.980 ;
        RECT 341.235 46.750 353.775 46.920 ;
        RECT 354.915 46.750 367.455 46.920 ;
        RECT 368.180 46.350 368.350 67.900 ;
        RECT 575.130 67.750 603.140 67.920 ;
        RECT 394.280 62.830 395.930 63.000 ;
        RECT 394.280 55.910 394.450 62.830 ;
        RECT 394.930 60.190 395.280 62.350 ;
        RECT 395.760 59.990 395.930 62.830 ;
        RECT 395.760 59.020 396.030 59.990 ;
        RECT 394.930 56.390 395.280 58.550 ;
        RECT 395.760 55.910 395.930 59.020 ;
        RECT 394.280 55.740 395.930 55.910 ;
        RECT 340.340 46.180 368.350 46.350 ;
        RECT 575.130 46.200 575.300 67.750 ;
        RECT 581.220 67.710 583.990 67.750 ;
        RECT 576.025 67.180 588.565 67.350 ;
        RECT 589.705 67.180 602.245 67.350 ;
        RECT 575.640 57.120 575.810 67.120 ;
        RECT 588.780 57.120 588.950 67.120 ;
        RECT 589.320 57.120 589.490 67.120 ;
        RECT 602.460 57.120 602.630 67.120 ;
        RECT 576.025 56.890 588.565 57.060 ;
        RECT 589.705 56.890 602.245 57.060 ;
        RECT 575.640 46.830 575.810 56.830 ;
        RECT 588.780 46.830 588.950 56.830 ;
        RECT 589.320 46.830 589.490 56.830 ;
        RECT 602.460 46.830 602.630 56.830 ;
        RECT 576.025 46.600 588.565 46.770 ;
        RECT 589.705 46.600 602.245 46.770 ;
        RECT 602.970 46.200 603.140 67.750 ;
        RECT 575.130 46.030 603.140 46.200 ;
        RECT 614.730 67.750 642.740 67.920 ;
        RECT 614.730 46.200 614.900 67.750 ;
        RECT 620.730 67.650 623.110 67.750 ;
        RECT 615.625 67.180 628.165 67.350 ;
        RECT 629.305 67.180 641.845 67.350 ;
        RECT 615.240 57.120 615.410 67.120 ;
        RECT 628.380 57.120 628.550 67.120 ;
        RECT 628.920 57.120 629.090 67.120 ;
        RECT 642.060 57.120 642.230 67.120 ;
        RECT 615.625 56.890 628.165 57.060 ;
        RECT 629.305 56.890 641.845 57.060 ;
        RECT 615.240 46.830 615.410 56.830 ;
        RECT 628.380 46.830 628.550 56.830 ;
        RECT 628.920 46.830 629.090 56.830 ;
        RECT 642.060 46.830 642.230 56.830 ;
        RECT 615.625 46.600 628.165 46.770 ;
        RECT 629.305 46.600 641.845 46.770 ;
        RECT 642.570 46.200 642.740 67.750 ;
        RECT 614.730 46.030 642.740 46.200 ;
        RECT 766.590 67.750 794.600 67.920 ;
        RECT 766.590 46.200 766.760 67.750 ;
        RECT 772.680 67.710 775.450 67.750 ;
        RECT 767.485 67.180 780.025 67.350 ;
        RECT 781.165 67.180 793.705 67.350 ;
        RECT 767.100 57.120 767.270 67.120 ;
        RECT 780.240 57.120 780.410 67.120 ;
        RECT 780.780 57.120 780.950 67.120 ;
        RECT 793.920 57.120 794.090 67.120 ;
        RECT 767.485 56.890 780.025 57.060 ;
        RECT 781.165 56.890 793.705 57.060 ;
        RECT 767.100 46.830 767.270 56.830 ;
        RECT 780.240 46.830 780.410 56.830 ;
        RECT 780.780 46.830 780.950 56.830 ;
        RECT 793.920 46.830 794.090 56.830 ;
        RECT 767.485 46.600 780.025 46.770 ;
        RECT 781.165 46.600 793.705 46.770 ;
        RECT 794.430 46.200 794.600 67.750 ;
        RECT 766.590 46.030 794.600 46.200 ;
        RECT 806.190 67.750 834.200 67.920 ;
        RECT 806.190 46.200 806.360 67.750 ;
        RECT 812.190 67.650 814.570 67.750 ;
        RECT 807.085 67.180 819.625 67.350 ;
        RECT 820.765 67.180 833.305 67.350 ;
        RECT 806.700 57.120 806.870 67.120 ;
        RECT 819.840 57.120 820.010 67.120 ;
        RECT 820.380 57.120 820.550 67.120 ;
        RECT 833.520 57.120 833.690 67.120 ;
        RECT 807.085 56.890 819.625 57.060 ;
        RECT 820.765 56.890 833.305 57.060 ;
        RECT 806.700 46.830 806.870 56.830 ;
        RECT 819.840 46.830 820.010 56.830 ;
        RECT 820.380 46.830 820.550 56.830 ;
        RECT 833.520 46.830 833.690 56.830 ;
        RECT 807.085 46.600 819.625 46.770 ;
        RECT 820.765 46.600 833.305 46.770 ;
        RECT 834.030 46.200 834.200 67.750 ;
        RECT 806.190 46.030 834.200 46.200 ;
        RECT 169.470 44.610 171.120 44.780 ;
        RECT 169.470 28.490 169.640 44.610 ;
        RECT 170.120 41.970 170.470 44.130 ;
        RECT 170.120 28.970 170.470 31.130 ;
        RECT 169.930 28.490 170.710 28.580 ;
        RECT 170.950 28.490 171.120 44.610 ;
        RECT 169.470 28.320 171.120 28.490 ;
        RECT 177.795 44.345 179.445 44.515 ;
        RECT 169.930 28.300 170.710 28.320 ;
        RECT 177.795 28.225 177.965 44.345 ;
        RECT 178.445 41.705 178.795 43.865 ;
        RECT 178.445 28.705 178.795 30.865 ;
        RECT 178.220 28.225 179.000 28.290 ;
        RECT 179.275 28.225 179.445 44.345 ;
        RECT 177.795 28.055 179.445 28.225 ;
        RECT 188.340 44.420 189.990 44.590 ;
        RECT 188.340 28.300 188.510 44.420 ;
        RECT 188.990 41.780 189.340 43.940 ;
        RECT 188.990 28.780 189.340 30.940 ;
        RECT 188.760 28.300 189.540 28.350 ;
        RECT 189.820 28.300 189.990 44.420 ;
        RECT 675.835 41.745 683.995 41.915 ;
        RECT 364.660 39.600 370.400 39.770 ;
        RECT 364.660 37.340 364.830 39.600 ;
        RECT 365.510 39.030 369.550 39.200 ;
        RECT 365.170 37.970 365.340 38.970 ;
        RECT 369.720 37.970 369.890 38.970 ;
        RECT 365.510 37.740 369.550 37.910 ;
        RECT 365.190 37.340 366.210 37.450 ;
        RECT 370.230 37.340 370.400 39.600 ;
        RECT 364.660 37.170 370.400 37.340 ;
        RECT 639.050 39.450 644.790 39.620 ;
        RECT 639.050 37.190 639.220 39.450 ;
        RECT 639.900 38.880 643.940 39.050 ;
        RECT 639.560 37.820 639.730 38.820 ;
        RECT 644.110 37.820 644.280 38.820 ;
        RECT 639.900 37.590 643.940 37.760 ;
        RECT 639.580 37.190 640.600 37.300 ;
        RECT 644.620 37.190 644.790 39.450 ;
        RECT 365.190 37.050 366.210 37.170 ;
        RECT 639.050 37.020 644.790 37.190 ;
        RECT 639.580 36.900 640.600 37.020 ;
        RECT 304.040 35.830 309.780 36.000 ;
        RECT 304.040 35.100 304.210 35.830 ;
        RECT 304.890 35.260 308.930 35.430 ;
        RECT 303.950 34.220 304.310 35.100 ;
        RECT 304.040 33.570 304.210 34.220 ;
        RECT 304.550 34.200 304.720 35.200 ;
        RECT 309.100 34.200 309.270 35.200 ;
        RECT 304.890 33.970 308.930 34.140 ;
        RECT 309.610 33.570 309.780 35.830 ;
        RECT 578.430 35.680 584.170 35.850 ;
        RECT 578.430 34.950 578.600 35.680 ;
        RECT 579.280 35.110 583.320 35.280 ;
        RECT 578.340 34.070 578.700 34.950 ;
        RECT 365.410 33.610 366.310 33.730 ;
        RECT 304.040 33.400 309.780 33.570 ;
        RECT 365.380 33.440 369.920 33.610 ;
        RECT 365.380 33.390 366.310 33.440 ;
        RECT 365.380 31.180 365.550 33.390 ;
        RECT 366.230 32.870 369.070 33.040 ;
        RECT 365.890 31.810 366.060 32.810 ;
        RECT 369.240 31.810 369.410 32.810 ;
        RECT 366.230 31.580 369.070 31.750 ;
        RECT 367.110 31.180 368.350 31.290 ;
        RECT 369.750 31.180 369.920 33.440 ;
        RECT 578.430 33.420 578.600 34.070 ;
        RECT 578.940 34.050 579.110 35.050 ;
        RECT 583.490 34.050 583.660 35.050 ;
        RECT 579.280 33.820 583.320 33.990 ;
        RECT 584.000 33.420 584.170 35.680 ;
        RECT 675.835 35.055 676.005 41.745 ;
        RECT 676.485 35.535 678.645 41.265 ;
        RECT 681.185 35.535 683.345 41.265 ;
        RECT 679.230 35.055 680.920 35.120 ;
        RECT 683.825 35.055 683.995 41.745 ;
        RECT 830.510 39.450 836.250 39.620 ;
        RECT 830.510 37.190 830.680 39.450 ;
        RECT 831.360 38.880 835.400 39.050 ;
        RECT 831.020 37.820 831.190 38.820 ;
        RECT 835.570 37.820 835.740 38.820 ;
        RECT 831.360 37.590 835.400 37.760 ;
        RECT 831.040 37.190 832.060 37.300 ;
        RECT 836.080 37.190 836.250 39.450 ;
        RECT 830.510 37.020 836.250 37.190 ;
        RECT 831.040 36.900 832.060 37.020 ;
        RECT 675.835 34.885 683.995 35.055 ;
        RECT 769.890 35.680 775.630 35.850 ;
        RECT 769.890 34.950 770.060 35.680 ;
        RECT 770.740 35.110 774.780 35.280 ;
        RECT 679.230 34.310 680.920 34.885 ;
        RECT 769.800 34.070 770.160 34.950 ;
        RECT 639.800 33.460 640.700 33.580 ;
        RECT 578.430 33.250 584.170 33.420 ;
        RECT 639.770 33.290 644.310 33.460 ;
        RECT 365.380 31.010 369.920 31.180 ;
        RECT 639.770 33.240 640.700 33.290 ;
        RECT 639.770 31.030 639.940 33.240 ;
        RECT 640.620 32.720 643.460 32.890 ;
        RECT 640.280 31.660 640.450 32.660 ;
        RECT 643.630 31.660 643.800 32.660 ;
        RECT 640.620 31.430 643.460 31.600 ;
        RECT 641.500 31.030 642.740 31.140 ;
        RECT 644.140 31.030 644.310 33.290 ;
        RECT 769.890 33.420 770.060 34.070 ;
        RECT 770.400 34.050 770.570 35.050 ;
        RECT 774.950 34.050 775.120 35.050 ;
        RECT 770.740 33.820 774.780 33.990 ;
        RECT 775.460 33.420 775.630 35.680 ;
        RECT 831.260 33.460 832.160 33.580 ;
        RECT 769.890 33.250 775.630 33.420 ;
        RECT 831.230 33.290 835.770 33.460 ;
        RECT 367.110 30.800 368.350 31.010 ;
        RECT 639.770 30.860 644.310 31.030 ;
        RECT 831.230 33.240 832.160 33.290 ;
        RECT 831.230 31.030 831.400 33.240 ;
        RECT 832.080 32.720 834.920 32.890 ;
        RECT 831.740 31.660 831.910 32.660 ;
        RECT 835.090 31.660 835.260 32.660 ;
        RECT 832.080 31.430 834.920 31.600 ;
        RECT 832.960 31.030 834.200 31.140 ;
        RECT 835.600 31.030 835.770 33.290 ;
        RECT 831.230 30.860 835.770 31.030 ;
        RECT 641.500 30.650 642.740 30.860 ;
        RECT 832.960 30.650 834.200 30.860 ;
        RECT 188.340 28.130 189.990 28.300 ;
        RECT 304.750 28.480 309.290 28.650 ;
        RECT 188.760 28.070 189.540 28.130 ;
        RECT 178.220 28.010 179.000 28.055 ;
        RECT 304.750 26.220 304.920 28.480 ;
        RECT 305.600 27.910 308.440 28.080 ;
        RECT 305.260 26.850 305.430 27.850 ;
        RECT 308.610 26.850 308.780 27.850 ;
        RECT 305.600 26.620 308.440 26.790 ;
        RECT 306.540 26.220 307.520 26.350 ;
        RECT 309.120 26.220 309.290 28.480 ;
        RECT 579.140 28.330 583.680 28.500 ;
        RECT 424.510 26.510 434.970 26.680 ;
        RECT 424.510 26.220 424.680 26.510 ;
        RECT 304.750 26.050 309.290 26.220 ;
        RECT 306.540 25.900 307.520 26.050 ;
        RECT 424.340 25.490 424.860 26.220 ;
        RECT 425.160 25.680 427.320 26.030 ;
        RECT 432.160 25.680 434.320 26.030 ;
        RECT 424.510 25.200 424.680 25.490 ;
        RECT 434.800 25.200 434.970 26.510 ;
        RECT 457.710 26.440 468.170 26.610 ;
        RECT 457.710 26.110 457.880 26.440 ;
        RECT 457.520 25.450 458.010 26.110 ;
        RECT 458.360 25.610 460.520 25.960 ;
        RECT 465.360 25.610 467.520 25.960 ;
        RECT 424.510 25.030 434.970 25.200 ;
        RECT 457.710 25.130 457.880 25.450 ;
        RECT 468.000 25.130 468.170 26.440 ;
        RECT 486.390 26.440 496.850 26.610 ;
        RECT 486.390 26.150 486.560 26.440 ;
        RECT 486.230 25.490 486.720 26.150 ;
        RECT 487.040 25.610 489.200 25.960 ;
        RECT 494.040 25.610 496.200 25.960 ;
        RECT 457.710 24.960 468.170 25.130 ;
        RECT 486.390 25.130 486.560 25.490 ;
        RECT 496.680 25.130 496.850 26.440 ;
        RECT 527.290 26.370 537.750 26.540 ;
        RECT 527.290 26.040 527.460 26.370 ;
        RECT 527.100 25.380 527.590 26.040 ;
        RECT 527.940 25.540 530.100 25.890 ;
        RECT 534.940 25.540 537.100 25.890 ;
        RECT 486.390 24.960 496.850 25.130 ;
        RECT 527.290 25.060 527.460 25.380 ;
        RECT 537.580 25.060 537.750 26.370 ;
        RECT 579.140 26.070 579.310 28.330 ;
        RECT 579.990 27.760 582.830 27.930 ;
        RECT 579.650 26.700 579.820 27.700 ;
        RECT 583.000 26.700 583.170 27.700 ;
        RECT 579.990 26.470 582.830 26.640 ;
        RECT 580.930 26.070 581.910 26.200 ;
        RECT 583.510 26.070 583.680 28.330 ;
        RECT 579.140 25.900 583.680 26.070 ;
        RECT 770.600 28.330 775.140 28.500 ;
        RECT 770.600 26.070 770.770 28.330 ;
        RECT 771.450 27.760 774.290 27.930 ;
        RECT 771.110 26.700 771.280 27.700 ;
        RECT 774.460 26.700 774.630 27.700 ;
        RECT 771.450 26.470 774.290 26.640 ;
        RECT 772.390 26.070 773.370 26.200 ;
        RECT 774.970 26.070 775.140 28.330 ;
        RECT 770.600 25.900 775.140 26.070 ;
        RECT 580.930 25.750 581.910 25.900 ;
        RECT 772.390 25.750 773.370 25.900 ;
        RECT 527.290 24.890 537.750 25.060 ;
        RECT 424.490 19.020 443.150 19.190 ;
        RECT 424.490 17.710 424.660 19.020 ;
        RECT 425.140 18.190 427.300 18.540 ;
        RECT 440.340 18.190 442.500 18.540 ;
        RECT 440.860 17.710 441.750 17.780 ;
        RECT 442.980 17.710 443.150 19.020 ;
        RECT 424.490 17.540 443.150 17.710 ;
        RECT 457.780 19.090 466.310 19.260 ;
        RECT 457.780 17.780 457.950 19.090 ;
        RECT 458.430 18.260 460.590 18.610 ;
        RECT 463.500 18.260 465.660 18.610 ;
        RECT 464.120 17.780 465.140 17.820 ;
        RECT 466.140 17.780 466.310 19.090 ;
        RECT 457.780 17.610 466.310 17.780 ;
        RECT 486.300 19.160 504.960 19.330 ;
        RECT 486.300 17.850 486.470 19.160 ;
        RECT 486.950 18.330 489.110 18.680 ;
        RECT 502.150 18.330 504.310 18.680 ;
        RECT 502.770 17.850 503.720 17.880 ;
        RECT 504.790 17.850 504.960 19.160 ;
        RECT 486.300 17.680 504.960 17.850 ;
        RECT 527.370 19.240 534.430 19.410 ;
        RECT 527.370 17.930 527.540 19.240 ;
        RECT 528.020 18.410 530.180 18.760 ;
        RECT 531.620 18.410 533.780 18.760 ;
        RECT 532.260 17.930 533.370 17.980 ;
        RECT 534.260 17.930 534.430 19.240 ;
        RECT 527.370 17.760 534.430 17.930 ;
        RECT 440.860 17.450 441.750 17.540 ;
        RECT 464.120 17.530 465.140 17.610 ;
        RECT 502.770 17.600 503.720 17.680 ;
        RECT 532.260 17.650 533.370 17.760 ;
      LAYER met1 ;
        RECT 0.950 223.640 161.000 223.930 ;
        RECT 476.630 223.900 485.060 223.930 ;
        RECT 476.300 223.760 485.060 223.900 ;
        RECT 476.300 223.740 551.030 223.760 ;
        RECT 476.300 223.640 598.360 223.740 ;
        RECT 0.950 219.870 598.360 223.640 ;
        RECT 0.950 219.770 554.655 219.870 ;
        RECT 0.950 189.950 161.000 219.770 ;
        RECT 246.690 219.560 328.420 219.770 ;
        RECT 259.520 218.490 267.950 219.560 ;
        RECT 270.560 217.000 272.640 219.560 ;
        RECT 283.440 217.490 285.890 219.560 ;
        RECT 282.745 217.260 286.595 217.490 ;
        RECT 304.960 217.440 307.150 219.560 ;
        RECT 318.710 219.520 328.420 219.560 ;
        RECT 489.130 218.840 497.560 219.770 ;
        RECT 304.105 217.210 307.955 217.440 ;
        RECT 500.170 217.350 502.250 219.770 ;
        RECT 513.050 217.840 515.500 219.770 ;
        RECT 512.355 217.610 516.205 217.840 ;
        RECT 534.570 217.790 536.760 219.770 ;
        RECT 533.715 217.560 537.565 217.790 ;
        RECT 270.540 216.540 272.640 217.000 ;
        RECT 259.440 216.300 261.790 216.450 ;
        RECT 253.115 216.070 263.115 216.300 ;
        RECT 264.295 216.070 274.295 216.300 ;
        RECT 252.680 215.710 252.910 216.020 ;
        RECT 259.440 216.010 261.790 216.070 ;
        RECT 249.950 215.060 252.910 215.710 ;
        RECT 263.320 215.890 263.550 216.020 ;
        RECT 263.860 215.890 264.090 216.020 ;
        RECT 265.680 215.910 267.950 216.070 ;
        RECT 249.950 214.730 252.790 215.060 ;
        RECT 253.520 215.010 255.760 215.120 ;
        RECT 263.320 215.060 264.090 215.890 ;
        RECT 274.500 215.060 274.730 216.020 ;
        RECT 253.115 214.780 263.115 215.010 ;
        RECT 249.950 213.770 252.910 214.730 ;
        RECT 253.520 214.620 255.760 214.780 ;
        RECT 263.380 214.730 264.030 215.060 ;
        RECT 271.120 215.010 273.320 215.050 ;
        RECT 282.310 215.020 282.540 217.210 ;
        RECT 286.800 216.810 287.030 217.210 ;
        RECT 303.670 216.810 303.900 217.160 ;
        RECT 286.800 215.330 303.900 216.810 ;
        RECT 286.800 215.020 287.030 215.330 ;
        RECT 264.295 214.780 274.295 215.010 ;
        RECT 303.670 214.970 303.900 215.330 ;
        RECT 308.160 214.970 308.390 217.160 ;
        RECT 500.150 216.890 502.250 217.350 ;
        RECT 489.050 216.650 491.400 216.800 ;
        RECT 482.725 216.420 492.725 216.650 ;
        RECT 493.905 216.420 503.905 216.650 ;
        RECT 482.290 216.060 482.520 216.370 ;
        RECT 489.050 216.360 491.400 216.420 ;
        RECT 479.560 215.410 482.520 216.060 ;
        RECT 492.930 216.240 493.160 216.370 ;
        RECT 493.470 216.240 493.700 216.370 ;
        RECT 495.290 216.260 497.560 216.420 ;
        RECT 479.560 215.080 482.400 215.410 ;
        RECT 483.130 215.360 485.370 215.470 ;
        RECT 492.930 215.410 493.700 216.240 ;
        RECT 504.110 215.410 504.340 216.370 ;
        RECT 482.725 215.130 492.725 215.360 ;
        RECT 263.320 213.770 264.090 214.730 ;
        RECT 271.120 214.520 273.320 214.780 ;
        RECT 282.745 214.740 286.595 214.970 ;
        RECT 249.950 213.440 252.790 213.770 ;
        RECT 259.480 213.720 261.780 213.770 ;
        RECT 253.115 213.490 263.115 213.720 ;
        RECT 249.950 212.480 252.910 213.440 ;
        RECT 259.480 213.380 261.780 213.490 ;
        RECT 263.380 213.440 264.030 213.770 ;
        RECT 265.680 213.720 267.930 213.830 ;
        RECT 274.500 213.770 274.730 214.730 ;
        RECT 264.295 213.490 274.295 213.720 ;
        RECT 249.950 212.150 252.790 212.480 ;
        RECT 253.490 212.430 255.730 212.610 ;
        RECT 263.320 212.480 264.090 213.440 ;
        RECT 265.680 213.430 267.930 213.490 ;
        RECT 253.115 212.200 263.115 212.430 ;
        RECT 249.950 211.870 252.910 212.150 ;
        RECT 253.490 212.110 255.730 212.200 ;
        RECT 263.380 212.150 264.030 212.480 ;
        RECT 271.120 212.430 273.320 212.590 ;
        RECT 274.500 212.480 274.730 213.440 ;
        RECT 264.295 212.200 274.295 212.430 ;
        RECT 240.005 211.190 252.910 211.870 ;
        RECT 263.320 211.190 264.090 212.150 ;
        RECT 271.120 212.060 273.320 212.200 ;
        RECT 240.005 210.860 252.790 211.190 ;
        RECT 259.460 211.140 261.740 211.180 ;
        RECT 253.115 210.910 263.115 211.140 ;
        RECT 240.005 209.900 252.910 210.860 ;
        RECT 259.460 210.680 261.740 210.910 ;
        RECT 263.380 210.860 264.030 211.190 ;
        RECT 265.740 211.140 267.990 211.220 ;
        RECT 274.500 211.190 274.730 212.150 ;
        RECT 283.590 211.410 285.780 214.740 ;
        RECT 304.105 214.690 307.955 214.920 ;
        RECT 282.795 211.180 286.795 211.410 ;
        RECT 304.490 211.250 307.340 214.690 ;
        RECT 479.560 214.120 482.520 215.080 ;
        RECT 483.130 214.970 485.370 215.130 ;
        RECT 492.990 215.080 493.640 215.410 ;
        RECT 500.730 215.360 502.930 215.400 ;
        RECT 511.920 215.370 512.150 217.560 ;
        RECT 516.410 217.160 516.640 217.560 ;
        RECT 533.280 217.160 533.510 217.510 ;
        RECT 516.410 215.680 533.510 217.160 ;
        RECT 516.410 215.370 516.640 215.680 ;
        RECT 493.905 215.130 503.905 215.360 ;
        RECT 533.280 215.320 533.510 215.680 ;
        RECT 537.770 215.320 538.000 217.510 ;
        RECT 492.930 214.120 493.700 215.080 ;
        RECT 500.730 214.870 502.930 215.130 ;
        RECT 512.355 215.090 516.205 215.320 ;
        RECT 479.560 213.790 482.400 214.120 ;
        RECT 489.090 214.070 491.390 214.120 ;
        RECT 482.725 213.840 492.725 214.070 ;
        RECT 479.560 212.830 482.520 213.790 ;
        RECT 489.090 213.730 491.390 213.840 ;
        RECT 492.990 213.790 493.640 214.120 ;
        RECT 495.290 214.070 497.540 214.180 ;
        RECT 504.110 214.120 504.340 215.080 ;
        RECT 493.905 213.840 503.905 214.070 ;
        RECT 479.560 212.500 482.400 212.830 ;
        RECT 483.100 212.780 485.340 212.960 ;
        RECT 492.930 212.830 493.700 213.790 ;
        RECT 495.290 213.780 497.540 213.840 ;
        RECT 482.725 212.550 492.725 212.780 ;
        RECT 479.560 212.220 482.520 212.500 ;
        RECT 483.100 212.460 485.340 212.550 ;
        RECT 492.990 212.500 493.640 212.830 ;
        RECT 500.730 212.780 502.930 212.940 ;
        RECT 504.110 212.830 504.340 213.790 ;
        RECT 493.905 212.550 503.905 212.780 ;
        RECT 466.045 211.540 482.520 212.220 ;
        RECT 492.930 211.540 493.700 212.500 ;
        RECT 500.730 212.410 502.930 212.550 ;
        RECT 466.045 211.520 482.400 211.540 ;
        RECT 326.220 211.360 328.340 211.440 ;
        RECT 264.295 210.910 274.295 211.140 ;
        RECT 240.005 209.800 252.790 209.900 ;
        RECT 253.500 209.850 255.740 209.990 ;
        RECT 263.320 209.900 264.090 210.860 ;
        RECT 265.740 210.820 267.990 210.910 ;
        RECT 249.950 209.570 252.790 209.800 ;
        RECT 253.115 209.620 263.115 209.850 ;
        RECT 249.950 208.980 252.910 209.570 ;
        RECT 253.500 209.490 255.740 209.620 ;
        RECT 263.380 209.570 264.030 209.900 ;
        RECT 271.140 209.850 273.340 209.930 ;
        RECT 274.500 209.900 274.730 210.860 ;
        RECT 264.295 209.620 274.295 209.850 ;
        RECT 252.680 208.610 252.910 208.980 ;
        RECT 263.320 208.760 264.090 209.570 ;
        RECT 271.140 209.400 273.340 209.620 ;
        RECT 263.320 208.610 263.550 208.760 ;
        RECT 263.860 208.610 264.090 208.760 ;
        RECT 259.480 208.560 261.720 208.610 ;
        RECT 265.730 208.560 267.980 208.630 ;
        RECT 274.500 208.610 274.730 209.570 ;
        RECT 282.360 208.940 282.590 211.130 ;
        RECT 287.000 210.760 287.230 211.130 ;
        RECT 303.995 211.020 307.995 211.250 ;
        RECT 308.380 210.970 333.900 211.360 ;
        RECT 303.560 210.760 303.790 210.970 ;
        RECT 287.000 209.100 303.790 210.760 ;
        RECT 287.000 208.940 287.230 209.100 ;
        RECT 283.770 208.890 286.220 208.930 ;
        RECT 282.795 208.660 286.795 208.890 ;
        RECT 303.560 208.780 303.790 209.100 ;
        RECT 308.200 208.960 333.900 210.970 ;
        RECT 465.510 211.210 482.400 211.520 ;
        RECT 489.070 211.490 491.350 211.530 ;
        RECT 482.725 211.260 492.725 211.490 ;
        RECT 465.510 210.250 482.520 211.210 ;
        RECT 489.070 211.030 491.350 211.260 ;
        RECT 492.990 211.210 493.640 211.540 ;
        RECT 495.350 211.490 497.600 211.570 ;
        RECT 504.110 211.540 504.340 212.500 ;
        RECT 513.200 211.760 515.390 215.090 ;
        RECT 533.715 215.040 537.565 215.270 ;
        RECT 512.405 211.530 516.405 211.760 ;
        RECT 534.100 211.600 536.950 215.040 ;
        RECT 555.830 211.710 557.950 211.790 ;
        RECT 493.905 211.260 503.905 211.490 ;
        RECT 465.510 210.150 482.400 210.250 ;
        RECT 483.110 210.200 485.350 210.340 ;
        RECT 492.930 210.250 493.700 211.210 ;
        RECT 495.350 211.170 497.600 211.260 ;
        RECT 465.510 210.100 467.030 210.150 ;
        RECT 479.560 209.920 482.400 210.150 ;
        RECT 482.725 209.970 492.725 210.200 ;
        RECT 479.560 209.330 482.520 209.920 ;
        RECT 483.110 209.840 485.350 209.970 ;
        RECT 492.990 209.920 493.640 210.250 ;
        RECT 500.750 210.200 502.950 210.280 ;
        RECT 504.110 210.250 504.340 211.210 ;
        RECT 493.905 209.970 503.905 210.200 ;
        RECT 482.290 208.960 482.520 209.330 ;
        RECT 492.930 209.110 493.700 209.920 ;
        RECT 500.750 209.750 502.950 209.970 ;
        RECT 492.930 208.960 493.160 209.110 ;
        RECT 493.470 208.960 493.700 209.110 ;
        RECT 308.200 208.930 327.290 208.960 ;
        RECT 308.200 208.780 308.430 208.930 ;
        RECT 489.090 208.910 491.330 208.960 ;
        RECT 495.340 208.910 497.590 208.980 ;
        RECT 504.110 208.960 504.340 209.920 ;
        RECT 511.970 209.290 512.200 211.480 ;
        RECT 516.610 211.110 516.840 211.480 ;
        RECT 533.605 211.370 537.605 211.600 ;
        RECT 537.990 211.320 565.795 211.710 ;
        RECT 533.170 211.110 533.400 211.320 ;
        RECT 516.610 209.450 533.400 211.110 ;
        RECT 516.610 209.290 516.840 209.450 ;
        RECT 513.380 209.240 515.830 209.280 ;
        RECT 512.405 209.010 516.405 209.240 ;
        RECT 533.170 209.130 533.400 209.450 ;
        RECT 537.810 209.280 565.795 211.320 ;
        RECT 537.810 209.130 538.040 209.280 ;
        RECT 513.380 208.930 515.830 209.010 ;
        RECT 283.770 208.580 286.220 208.660 ;
        RECT 253.115 208.330 263.115 208.560 ;
        RECT 264.295 208.330 274.295 208.560 ;
        RECT 303.995 208.500 307.995 208.730 ;
        RECT 482.725 208.680 492.725 208.910 ;
        RECT 493.905 208.680 503.905 208.910 ;
        RECT 533.605 208.850 537.605 209.080 ;
        RECT 489.090 208.590 491.330 208.680 ;
        RECT 495.340 208.580 497.590 208.680 ;
        RECT 259.480 208.240 261.720 208.330 ;
        RECT 265.730 208.230 267.980 208.330 ;
        RECT 304.570 207.600 307.590 208.500 ;
        RECT 534.180 207.950 537.200 208.850 ;
        RECT 550.350 207.950 552.180 208.140 ;
        RECT 320.740 207.600 322.570 207.790 ;
        RECT 304.570 206.400 322.570 207.600 ;
        RECT 534.180 206.750 552.180 207.950 ;
        RECT 534.190 206.470 552.180 206.750 ;
        RECT 304.580 206.120 322.570 206.400 ;
        RECT 258.270 202.530 261.210 202.680 ;
        RECT 258.260 202.170 261.210 202.530 ;
        RECT 258.270 202.070 261.210 202.170 ;
        RECT 297.770 202.110 300.270 202.590 ;
        RECT 254.240 201.870 255.850 201.990 ;
        RECT 257.510 201.870 262.000 201.910 ;
        RECT 267.800 201.870 269.680 202.020 ;
        RECT 271.090 201.870 275.380 202.030 ;
        RECT 293.530 201.870 295.240 201.970 ;
        RECT 296.610 201.870 302.400 201.970 ;
        RECT 307.520 201.870 309.230 201.990 ;
        RECT 310.310 201.870 316.100 202.050 ;
        RECT 253.145 201.640 265.645 201.870 ;
        RECT 266.825 201.640 279.325 201.870 ;
        RECT 292.745 201.640 305.245 201.870 ;
        RECT 306.425 201.640 318.925 201.870 ;
        RECT 248.860 200.020 250.900 200.050 ;
        RECT 252.710 200.020 252.940 201.590 ;
        RECT 254.240 201.350 255.850 201.640 ;
        RECT 257.510 201.550 262.000 201.640 ;
        RECT 248.860 193.560 252.940 200.020 ;
        RECT 248.860 192.980 250.900 193.560 ;
        RECT 246.650 192.075 250.900 192.980 ;
        RECT 240.285 190.370 250.900 192.075 ;
        RECT 252.710 191.630 252.940 193.560 ;
        RECT 265.850 200.000 266.080 201.590 ;
        RECT 266.390 200.000 266.620 201.590 ;
        RECT 267.800 201.390 269.680 201.640 ;
        RECT 271.090 201.470 275.380 201.640 ;
        RECT 265.850 193.530 266.620 200.000 ;
        RECT 256.920 191.580 259.100 191.810 ;
        RECT 265.850 191.630 266.080 193.530 ;
        RECT 266.390 191.630 266.620 193.530 ;
        RECT 272.600 191.580 275.250 191.730 ;
        RECT 279.530 191.630 279.760 201.590 ;
        RECT 292.310 200.460 292.540 201.590 ;
        RECT 293.530 201.430 295.240 201.640 ;
        RECT 296.610 201.480 302.400 201.640 ;
        RECT 288.460 192.460 292.540 200.460 ;
        RECT 253.145 191.350 265.645 191.580 ;
        RECT 266.825 191.350 279.325 191.580 ;
        RECT 240.285 190.165 247.275 190.370 ;
        RECT 240.285 189.950 242.195 190.165 ;
        RECT 0.950 188.040 242.195 189.950 ;
        RECT 248.810 189.940 250.900 190.370 ;
        RECT 252.710 189.940 252.940 191.300 ;
        RECT 256.920 190.830 259.100 191.350 ;
        RECT 0.950 147.960 161.000 188.040 ;
        RECT 164.880 187.240 167.620 188.040 ;
        RECT 248.810 182.750 252.940 189.940 ;
        RECT 249.120 182.700 252.940 182.750 ;
        RECT 252.710 181.340 252.940 182.700 ;
        RECT 265.850 189.940 266.080 191.300 ;
        RECT 266.390 189.940 266.620 191.300 ;
        RECT 272.600 191.060 275.250 191.350 ;
        RECT 265.850 182.710 266.620 189.940 ;
        RECT 254.290 181.290 255.830 181.470 ;
        RECT 265.850 181.340 266.080 182.710 ;
        RECT 266.390 181.340 266.620 182.710 ;
        RECT 267.760 181.290 269.640 181.530 ;
        RECT 279.530 181.340 279.760 191.300 ;
        RECT 288.460 190.510 290.790 192.460 ;
        RECT 292.310 191.630 292.540 192.460 ;
        RECT 305.450 200.530 305.680 201.590 ;
        RECT 305.990 200.530 306.220 201.590 ;
        RECT 307.520 201.450 309.230 201.640 ;
        RECT 310.310 201.560 316.100 201.640 ;
        RECT 305.450 192.500 306.220 200.530 ;
        RECT 301.630 191.580 304.010 191.750 ;
        RECT 305.450 191.630 305.680 192.500 ;
        RECT 305.990 191.630 306.220 192.500 ;
        RECT 310.460 191.580 313.290 191.680 ;
        RECT 319.130 191.630 319.360 201.590 ;
        RECT 320.740 196.350 322.570 206.120 ;
        RECT 487.880 202.880 490.820 203.030 ;
        RECT 487.870 202.520 490.820 202.880 ;
        RECT 487.880 202.420 490.820 202.520 ;
        RECT 527.380 202.460 529.880 202.940 ;
        RECT 483.850 202.220 485.460 202.340 ;
        RECT 487.120 202.220 491.610 202.260 ;
        RECT 497.410 202.220 499.290 202.370 ;
        RECT 500.700 202.220 504.990 202.380 ;
        RECT 523.140 202.220 524.850 202.320 ;
        RECT 526.220 202.220 532.010 202.320 ;
        RECT 537.130 202.220 538.840 202.340 ;
        RECT 539.920 202.220 545.710 202.400 ;
        RECT 482.755 201.990 495.255 202.220 ;
        RECT 496.435 201.990 508.935 202.220 ;
        RECT 522.355 201.990 534.855 202.220 ;
        RECT 536.035 201.990 548.535 202.220 ;
        RECT 478.470 200.370 480.510 200.400 ;
        RECT 482.320 200.370 482.550 201.940 ;
        RECT 483.850 201.700 485.460 201.990 ;
        RECT 487.120 201.900 491.610 201.990 ;
        RECT 320.740 194.590 322.590 196.350 ;
        RECT 328.745 195.465 332.095 198.715 ;
        RECT 292.745 191.350 305.245 191.580 ;
        RECT 306.425 191.350 318.925 191.580 ;
        RECT 292.310 190.510 292.540 191.300 ;
        RECT 301.630 190.850 304.010 191.350 ;
        RECT 288.460 182.340 292.540 190.510 ;
        RECT 253.145 181.060 265.645 181.290 ;
        RECT 266.825 181.060 279.325 181.290 ;
        RECT 254.290 180.980 255.830 181.060 ;
        RECT 267.760 180.900 269.640 181.060 ;
        RECT 237.980 178.260 281.420 178.290 ;
        RECT 288.460 178.260 290.790 182.340 ;
        RECT 292.310 181.340 292.540 182.340 ;
        RECT 305.450 190.580 305.680 191.300 ;
        RECT 305.990 190.580 306.220 191.300 ;
        RECT 310.460 190.840 313.290 191.350 ;
        RECT 305.450 182.480 306.220 190.580 ;
        RECT 293.390 181.290 295.100 181.500 ;
        RECT 305.450 181.340 305.680 182.480 ;
        RECT 305.990 181.340 306.220 182.480 ;
        RECT 307.580 181.290 309.290 181.500 ;
        RECT 319.130 181.340 319.360 191.300 ;
        RECT 320.760 189.700 322.590 194.590 ;
        RECT 329.240 189.700 331.090 195.465 ;
        RECT 478.470 193.910 482.550 200.370 ;
        RECT 478.470 193.330 480.510 193.910 ;
        RECT 457.975 192.740 480.510 193.330 ;
        RECT 457.815 190.755 480.510 192.740 ;
        RECT 482.320 191.980 482.550 193.910 ;
        RECT 495.460 200.350 495.690 201.940 ;
        RECT 496.000 200.350 496.230 201.940 ;
        RECT 497.410 201.740 499.290 201.990 ;
        RECT 500.700 201.820 504.990 201.990 ;
        RECT 495.460 193.880 496.230 200.350 ;
        RECT 486.530 191.930 488.710 192.160 ;
        RECT 495.460 191.980 495.690 193.880 ;
        RECT 496.000 191.980 496.230 193.880 ;
        RECT 502.210 191.930 504.860 192.080 ;
        RECT 509.140 191.980 509.370 201.940 ;
        RECT 521.920 200.810 522.150 201.940 ;
        RECT 523.140 201.780 524.850 201.990 ;
        RECT 526.220 201.830 532.010 201.990 ;
        RECT 518.070 192.810 522.150 200.810 ;
        RECT 482.755 191.700 495.255 191.930 ;
        RECT 496.435 191.700 508.935 191.930 ;
        RECT 457.975 190.720 480.510 190.755 ;
        RECT 478.420 190.290 480.510 190.720 ;
        RECT 482.320 190.290 482.550 191.650 ;
        RECT 486.530 191.180 488.710 191.700 ;
        RECT 320.760 188.970 334.615 189.700 ;
        RECT 338.460 188.970 453.135 189.930 ;
        RECT 320.760 188.720 335.215 188.970 ;
        RECT 336.905 188.720 453.135 188.970 ;
        RECT 320.760 187.790 334.615 188.720 ;
        RECT 335.590 188.310 336.600 188.320 ;
        RECT 335.590 187.870 336.660 188.310 ;
        RECT 292.745 181.060 305.245 181.290 ;
        RECT 306.425 181.060 318.925 181.290 ;
        RECT 293.390 180.960 295.100 181.060 ;
        RECT 307.580 180.960 309.290 181.060 ;
        RECT 320.760 178.980 322.590 187.790 ;
        RECT 320.760 178.920 323.140 178.980 ;
        RECT 237.980 175.270 290.790 178.260 ;
        RECT 237.980 161.470 241.000 175.270 ;
        RECT 279.910 175.240 290.790 175.270 ;
        RECT 318.000 177.550 323.140 178.920 ;
        RECT 335.590 178.735 336.600 187.870 ;
        RECT 338.460 187.780 453.135 188.720 ;
        RECT 335.590 177.725 349.355 178.735 ;
        RECT 318.000 177.290 322.590 177.550 ;
        RECT 318.000 177.280 322.550 177.290 ;
        RECT 318.000 173.570 320.170 177.280 ;
        RECT 317.020 173.340 321.020 173.570 ;
        RECT 318.000 173.330 320.170 173.340 ;
        RECT 321.260 173.290 338.590 173.710 ;
        RECT 309.440 173.160 310.970 173.250 ;
        RECT 316.630 173.160 316.860 173.290 ;
        RECT 309.440 172.470 316.860 173.160 ;
        RECT 309.440 169.890 310.970 172.470 ;
        RECT 316.630 172.330 316.860 172.470 ;
        RECT 318.370 172.280 319.820 172.360 ;
        RECT 321.180 172.330 338.590 173.290 ;
        RECT 317.020 172.050 321.020 172.280 ;
        RECT 321.260 172.050 338.590 172.330 ;
        RECT 318.370 171.940 319.820 172.050 ;
        RECT 336.860 171.880 338.500 172.050 ;
        RECT 316.620 171.360 317.760 171.820 ;
        RECT 257.610 169.800 259.440 169.850 ;
        RECT 256.400 169.570 260.400 169.800 ;
        RECT 257.610 169.520 259.440 169.570 ;
        RECT 255.410 169.320 255.830 169.500 ;
        RECT 254.080 168.570 255.830 169.320 ;
        RECT 250.820 164.330 253.130 165.580 ;
        RECT 237.930 158.450 241.050 161.470 ;
        RECT 254.080 159.610 255.090 168.570 ;
        RECT 255.410 168.500 255.830 168.570 ;
        RECT 256.010 168.560 256.240 169.520 ;
        RECT 260.560 169.420 260.790 169.520 ;
        RECT 262.150 169.420 310.990 169.890 ;
        RECT 260.560 168.680 310.990 169.420 ;
        RECT 260.560 168.560 260.790 168.680 ;
        RECT 257.520 168.510 259.570 168.530 ;
        RECT 256.400 168.280 260.400 168.510 ;
        RECT 257.520 168.220 259.570 168.280 ;
        RECT 262.150 167.900 310.990 168.680 ;
        RECT 316.710 168.100 317.760 171.360 ;
        RECT 316.710 167.750 317.860 168.100 ;
        RECT 316.840 167.700 317.860 167.750 ;
        RECT 320.790 167.560 327.550 167.570 ;
        RECT 318.520 167.410 319.850 167.530 ;
        RECT 317.740 167.180 320.540 167.410 ;
        RECT 318.520 167.130 319.850 167.180 ;
        RECT 320.790 167.130 331.955 167.560 ;
        RECT 317.350 166.890 317.580 167.130 ;
        RECT 313.430 166.360 317.580 166.890 ;
        RECT 257.470 162.450 259.520 162.490 ;
        RECT 257.110 162.220 259.910 162.450 ;
        RECT 257.470 162.180 259.520 162.220 ;
        RECT 256.720 161.210 256.950 162.170 ;
        RECT 260.070 161.950 260.300 162.170 ;
        RECT 260.070 161.930 263.120 161.950 ;
        RECT 260.070 161.240 263.140 161.930 ;
        RECT 260.070 161.210 260.300 161.240 ;
        RECT 257.110 160.930 259.910 161.160 ;
        RECT 257.510 159.610 259.550 160.930 ;
        RECT 254.080 158.790 259.550 159.610 ;
        RECT 254.830 158.780 259.550 158.790 ;
        RECT 257.510 147.960 259.550 158.780 ;
        RECT 261.800 159.480 263.140 161.240 ;
        RECT 313.430 159.480 315.170 166.360 ;
        RECT 317.350 166.170 317.580 166.360 ;
        RECT 320.700 166.170 331.955 167.130 ;
        RECT 317.740 165.890 320.540 166.120 ;
        RECT 320.790 165.910 331.955 166.170 ;
        RECT 326.280 165.890 331.955 165.910 ;
        RECT 261.800 157.410 315.180 159.480 ;
        RECT 261.800 157.360 263.140 157.410 ;
        RECT 318.320 147.960 319.930 165.890 ;
        RECT 348.345 147.960 349.355 177.725 ;
        RECT 388.440 176.180 390.830 187.780 ;
        RECT 450.985 178.465 453.135 187.780 ;
        RECT 478.420 183.100 482.550 190.290 ;
        RECT 478.730 183.050 482.550 183.100 ;
        RECT 482.320 181.690 482.550 183.050 ;
        RECT 495.460 190.290 495.690 191.650 ;
        RECT 496.000 190.290 496.230 191.650 ;
        RECT 502.210 191.410 504.860 191.700 ;
        RECT 495.460 183.060 496.230 190.290 ;
        RECT 483.900 181.640 485.440 181.820 ;
        RECT 495.460 181.690 495.690 183.060 ;
        RECT 496.000 181.690 496.230 183.060 ;
        RECT 497.370 181.640 499.250 181.880 ;
        RECT 509.140 181.690 509.370 191.650 ;
        RECT 518.070 190.860 520.400 192.810 ;
        RECT 521.920 191.980 522.150 192.810 ;
        RECT 535.060 200.880 535.290 201.940 ;
        RECT 535.600 200.880 535.830 201.940 ;
        RECT 537.130 201.800 538.840 201.990 ;
        RECT 539.920 201.910 545.710 201.990 ;
        RECT 535.060 192.850 535.830 200.880 ;
        RECT 531.240 191.930 533.620 192.100 ;
        RECT 535.060 191.980 535.290 192.850 ;
        RECT 535.600 191.980 535.830 192.850 ;
        RECT 540.070 191.930 542.900 192.030 ;
        RECT 548.740 191.980 548.970 201.940 ;
        RECT 550.350 196.700 552.180 206.470 ;
        RECT 714.050 198.230 716.430 198.740 ;
        RECT 550.350 194.940 552.200 196.700 ;
        RECT 522.355 191.700 534.855 191.930 ;
        RECT 536.035 191.700 548.535 191.930 ;
        RECT 521.920 190.860 522.150 191.650 ;
        RECT 531.240 191.200 533.620 191.700 ;
        RECT 518.070 182.690 522.150 190.860 ;
        RECT 482.755 181.410 495.255 181.640 ;
        RECT 496.435 181.410 508.935 181.640 ;
        RECT 483.900 181.330 485.440 181.410 ;
        RECT 497.370 181.250 499.250 181.410 ;
        RECT 477.130 178.620 511.030 178.640 ;
        RECT 476.260 178.610 511.030 178.620 ;
        RECT 518.070 178.610 520.400 182.690 ;
        RECT 521.920 181.690 522.150 182.690 ;
        RECT 535.060 190.930 535.290 191.650 ;
        RECT 535.600 190.930 535.830 191.650 ;
        RECT 540.070 191.190 542.900 191.700 ;
        RECT 535.060 182.830 535.830 190.930 ;
        RECT 523.000 181.640 524.710 181.850 ;
        RECT 535.060 181.690 535.290 182.830 ;
        RECT 535.600 181.690 535.830 182.830 ;
        RECT 537.190 181.640 538.900 181.850 ;
        RECT 548.740 181.690 548.970 191.650 ;
        RECT 550.370 190.050 552.200 194.940 ;
        RECT 714.050 195.950 716.470 198.230 ;
        RECT 550.370 188.140 596.560 190.050 ;
        RECT 522.355 181.410 534.855 181.640 ;
        RECT 536.035 181.410 548.535 181.640 ;
        RECT 523.000 181.310 524.710 181.410 ;
        RECT 537.190 181.310 538.900 181.410 ;
        RECT 550.370 179.330 552.200 188.140 ;
        RECT 550.370 179.270 552.750 179.330 ;
        RECT 476.260 178.465 520.400 178.610 ;
        RECT 389.365 175.300 389.615 176.180 ;
        RECT 393.610 175.420 399.750 177.400 ;
        RECT 414.920 177.390 422.540 177.510 ;
        RECT 410.830 177.290 411.080 177.390 ;
        RECT 389.365 164.050 389.615 164.410 ;
        RECT 393.610 164.050 395.590 175.420 ;
        RECT 399.080 175.175 399.330 175.420 ;
        RECT 403.360 175.310 411.480 177.290 ;
        RECT 414.920 175.530 422.600 177.390 ;
        RECT 450.985 176.315 520.400 178.465 ;
        RECT 476.260 175.640 520.400 176.315 ;
        RECT 477.130 175.620 520.400 175.640 ;
        RECT 509.520 175.590 520.400 175.620 ;
        RECT 547.610 177.900 552.750 179.270 ;
        RECT 547.610 177.640 552.200 177.900 ;
        RECT 547.610 177.630 552.160 177.640 ;
        RECT 389.365 162.630 395.590 164.050 ;
        RECT 399.080 164.280 399.330 164.285 ;
        RECT 403.360 164.280 405.340 175.310 ;
        RECT 410.830 175.285 411.080 175.310 ;
        RECT 410.830 164.280 411.080 164.395 ;
        RECT 414.920 164.280 416.900 175.530 ;
        RECT 422.350 175.285 422.600 175.530 ;
        RECT 547.610 173.920 549.780 177.630 ;
        RECT 546.630 173.690 550.630 173.920 ;
        RECT 550.870 173.770 575.420 174.060 ;
        RECT 547.610 173.680 549.780 173.690 ;
        RECT 550.870 173.640 575.720 173.770 ;
        RECT 539.050 173.510 540.580 173.600 ;
        RECT 546.240 173.510 546.470 173.640 ;
        RECT 539.050 172.820 546.470 173.510 ;
        RECT 539.050 170.240 540.580 172.820 ;
        RECT 546.240 172.680 546.470 172.820 ;
        RECT 547.980 172.630 549.430 172.710 ;
        RECT 550.790 172.680 575.720 173.640 ;
        RECT 546.630 172.400 550.630 172.630 ;
        RECT 550.870 172.400 575.720 172.680 ;
        RECT 547.980 172.290 549.430 172.400 ;
        RECT 574.080 172.230 575.720 172.400 ;
        RECT 591.840 173.710 596.560 188.140 ;
        RECT 546.230 171.710 547.370 172.170 ;
        RECT 487.220 170.150 489.050 170.200 ;
        RECT 486.010 169.920 490.010 170.150 ;
        RECT 487.220 169.870 489.050 169.920 ;
        RECT 485.020 169.670 485.440 169.850 ;
        RECT 483.690 168.920 485.440 169.670 ;
        RECT 480.430 164.680 482.740 165.930 ;
        RECT 389.365 162.305 389.615 162.630 ;
        RECT 399.080 162.300 405.340 164.280 ;
        RECT 410.720 162.300 416.900 164.280 ;
        RECT 422.350 164.280 422.600 164.395 ;
        RECT 422.350 162.300 435.230 164.280 ;
        RECT 399.080 162.180 399.330 162.300 ;
        RECT 410.830 162.290 411.080 162.300 ;
        RECT 422.350 162.290 422.600 162.300 ;
        RECT 389.000 161.715 389.980 161.810 ;
        RECT 410.510 161.805 411.400 161.910 ;
        RECT 389.000 161.530 390.115 161.715 ;
        RECT 398.740 161.645 399.630 161.760 ;
        RECT 389.265 160.950 390.115 161.530 ;
        RECT 398.695 161.340 399.630 161.645 ;
        RECT 410.455 161.490 411.400 161.805 ;
        RECT 422.100 161.490 422.990 161.910 ;
        RECT 398.695 160.950 399.545 161.340 ;
        RECT 410.455 160.950 411.305 161.490 ;
        RECT 422.130 160.950 422.980 161.490 ;
        RECT 389.265 160.100 422.980 160.950 ;
        RECT 402.565 147.960 403.415 160.100 ;
        RECT 483.690 159.960 484.700 168.920 ;
        RECT 485.020 168.850 485.440 168.920 ;
        RECT 485.620 168.910 485.850 169.870 ;
        RECT 490.170 169.770 490.400 169.870 ;
        RECT 491.760 169.770 540.600 170.240 ;
        RECT 490.170 169.030 540.600 169.770 ;
        RECT 490.170 168.910 490.400 169.030 ;
        RECT 487.130 168.860 489.180 168.880 ;
        RECT 486.010 168.630 490.010 168.860 ;
        RECT 487.130 168.570 489.180 168.630 ;
        RECT 491.760 168.250 540.600 169.030 ;
        RECT 546.320 168.450 547.370 171.710 ;
        RECT 546.320 168.100 547.470 168.450 ;
        RECT 546.450 168.050 547.470 168.100 ;
        RECT 550.400 167.910 557.160 167.920 ;
        RECT 548.130 167.760 549.460 167.880 ;
        RECT 547.350 167.530 550.150 167.760 ;
        RECT 550.400 167.705 557.630 167.910 ;
        RECT 548.130 167.480 549.460 167.530 ;
        RECT 550.400 167.480 566.145 167.705 ;
        RECT 546.960 167.240 547.190 167.480 ;
        RECT 543.040 166.710 547.190 167.240 ;
        RECT 487.080 162.800 489.130 162.840 ;
        RECT 486.720 162.570 489.520 162.800 ;
        RECT 487.080 162.530 489.130 162.570 ;
        RECT 486.330 161.560 486.560 162.520 ;
        RECT 489.680 162.300 489.910 162.520 ;
        RECT 489.680 162.280 492.730 162.300 ;
        RECT 489.680 161.590 492.750 162.280 ;
        RECT 489.680 161.560 489.910 161.590 ;
        RECT 486.720 161.280 489.520 161.510 ;
        RECT 487.120 159.960 489.160 161.280 ;
        RECT 483.690 159.140 489.160 159.960 ;
        RECT 484.440 159.130 489.160 159.140 ;
        RECT 487.120 148.100 489.160 159.130 ;
        RECT 491.410 159.830 492.750 161.590 ;
        RECT 543.040 159.830 544.780 166.710 ;
        RECT 546.960 166.520 547.190 166.710 ;
        RECT 550.310 166.520 566.145 167.480 ;
        RECT 547.350 166.240 550.150 166.470 ;
        RECT 550.400 166.260 566.145 166.520 ;
        RECT 555.890 166.240 566.145 166.260 ;
        RECT 491.410 157.760 544.790 159.830 ;
        RECT 491.410 157.710 492.750 157.760 ;
        RECT 547.930 148.100 549.540 166.240 ;
        RECT 556.415 166.035 566.145 166.240 ;
        RECT 483.710 148.070 550.890 148.100 ;
        RECT 476.180 148.060 550.890 148.070 ;
        RECT 476.180 147.960 558.020 148.060 ;
        RECT 0.950 144.150 558.085 147.960 ;
        RECT 0.950 101.245 161.000 144.150 ;
        RECT 246.600 143.900 328.360 144.150 ;
        RECT 246.600 143.890 256.000 143.900 ;
        RECT 246.600 143.860 248.460 143.890 ;
        RECT 330.215 136.075 331.985 137.745 ;
        RECT 473.280 136.800 478.950 137.970 ;
        RECT 484.360 137.630 486.120 144.150 ;
        RECT 484.350 137.310 486.120 137.630 ;
        RECT 484.350 137.210 486.090 137.310 ;
        RECT 491.400 136.800 499.390 137.970 ;
        RECT 504.740 137.630 506.500 144.150 ;
        RECT 504.730 137.310 506.500 137.630 ;
        RECT 504.730 137.210 506.470 137.310 ;
        RECT 473.280 136.550 479.795 136.800 ;
        RECT 490.685 136.790 499.390 136.800 ;
        RECT 511.250 136.790 520.050 137.680 ;
        RECT 525.330 137.250 527.090 144.150 ;
        RECT 525.330 137.140 527.070 137.250 ;
        RECT 490.685 136.550 500.205 136.790 ;
        RECT 247.085 128.190 249.755 128.285 ;
        RECT 179.140 127.020 181.200 127.100 ;
        RECT 179.140 124.760 182.210 127.020 ;
        RECT 195.890 125.715 249.755 128.190 ;
        RECT 195.890 125.560 249.080 125.715 ;
        RECT 179.140 124.690 181.200 124.760 ;
        RECT 195.890 119.945 198.520 125.560 ;
        RECT 195.840 117.315 198.570 119.945 ;
        RECT 195.890 116.865 198.520 117.315 ;
        RECT 165.970 111.310 167.920 111.450 ;
        RECT 174.870 111.310 324.550 112.110 ;
        RECT 165.970 109.600 324.550 111.310 ;
        RECT 166.820 109.370 324.550 109.600 ;
        RECT 174.870 109.030 324.550 109.370 ;
        RECT 330.265 101.245 331.935 136.075 ;
        RECT 473.280 135.720 478.950 136.550 ;
        RECT 491.400 136.540 500.205 136.550 ;
        RECT 511.095 136.730 520.050 136.790 ;
        RECT 532.260 136.850 541.060 137.680 ;
        RECT 546.680 137.640 548.440 144.150 ;
        RECT 546.580 137.370 548.440 137.640 ;
        RECT 546.580 137.220 548.320 137.370 ;
        RECT 553.970 136.850 559.010 137.920 ;
        RECT 532.260 136.730 542.005 136.850 ;
        RECT 511.095 136.540 520.815 136.730 ;
        RECT 385.220 123.520 413.780 126.240 ;
        RECT 385.220 117.620 387.940 123.520 ;
        RECT 473.280 119.885 475.530 135.720 ;
        RECT 491.400 135.370 499.390 136.540 ;
        RECT 511.250 136.480 520.815 136.540 ;
        RECT 531.705 136.600 542.005 136.730 ;
        RECT 552.895 136.600 559.010 136.850 ;
        RECT 531.705 136.480 541.060 136.600 ;
        RECT 511.250 135.480 520.050 136.480 ;
        RECT 532.260 135.480 541.060 136.480 ;
        RECT 553.970 135.370 559.010 136.600 ;
        RECT 556.275 122.075 558.825 135.370 ;
        RECT 399.515 117.635 475.530 119.885 ;
        RECT 556.225 119.525 558.875 122.075 ;
        RECT 385.330 117.570 387.930 117.620 ;
        RECT 389.330 112.150 527.870 112.510 ;
        RECT 387.735 108.840 527.870 112.150 ;
        RECT 545.180 110.940 547.520 113.180 ;
        RECT 389.330 108.770 527.870 108.840 ;
        RECT 564.475 101.245 566.145 166.035 ;
        RECT 591.840 166.630 596.600 173.710 ;
        RECT 591.840 161.870 684.240 166.630 ;
        RECT 591.840 111.690 596.600 161.870 ;
        RECT 665.200 147.780 669.360 148.110 ;
        RECT 664.870 122.850 669.370 147.780 ;
        RECT 714.050 126.470 716.430 195.950 ;
        RECT 876.155 158.860 881.105 158.955 ;
        RECT 847.905 151.915 851.195 155.105 ;
        RECT 876.155 154.290 888.060 158.860 ;
        RECT 876.155 154.105 881.105 154.290 ;
        RECT 834.255 126.660 837.445 126.670 ;
        RECT 847.955 126.660 851.145 151.915 ;
        RECT 877.325 134.950 880.935 134.995 ;
        RECT 877.325 131.485 887.880 134.950 ;
        RECT 878.720 131.310 887.880 131.485 ;
        RECT 714.050 125.040 744.730 126.470 ;
        RECT 757.000 125.040 766.140 126.590 ;
        RECT 714.050 124.790 745.155 125.040 ;
        RECT 756.045 124.970 766.140 125.040 ;
        RECT 778.770 124.970 787.910 126.340 ;
        RECT 800.920 124.970 808.740 126.160 ;
        RECT 756.045 124.790 767.215 124.970 ;
        RECT 714.050 124.090 744.730 124.790 ;
        RECT 757.000 124.720 767.215 124.790 ;
        RECT 778.105 124.720 789.055 124.970 ;
        RECT 799.945 124.910 808.740 124.970 ;
        RECT 821.570 124.910 869.585 126.660 ;
        RECT 799.945 124.720 809.645 124.910 ;
        RECT 664.870 118.350 690.980 122.850 ;
        RECT 714.050 113.460 716.430 124.090 ;
        RECT 748.740 123.930 751.760 124.480 ;
        RECT 749.585 121.830 751.375 123.930 ;
        RECT 757.000 123.840 766.140 124.720 ;
        RECT 771.440 123.850 774.460 124.400 ;
        RECT 748.710 120.445 751.375 121.830 ;
        RECT 771.935 120.445 773.725 123.850 ;
        RECT 778.770 123.590 787.910 124.720 ;
        RECT 800.920 124.660 809.645 124.720 ;
        RECT 820.535 124.660 869.585 124.910 ;
        RECT 792.900 123.770 795.920 124.320 ;
        RECT 793.355 120.445 795.145 123.770 ;
        RECT 800.920 123.470 808.740 124.660 ;
        RECT 813.550 123.740 816.570 124.290 ;
        RECT 813.610 121.980 816.530 123.740 ;
        RECT 821.570 123.470 869.585 124.660 ;
        RECT 813.855 120.445 815.645 121.980 ;
        RECT 748.710 119.290 815.645 120.445 ;
        RECT 749.585 118.655 815.645 119.290 ;
        RECT 592.215 110.830 595.125 111.690 ;
        RECT 714.000 111.080 716.480 113.460 ;
        RECT 0.950 99.575 853.675 101.245 ;
        RECT 0.950 88.835 161.000 99.575 ;
        RECT 392.840 94.670 426.620 94.760 ;
        RECT 265.860 93.250 283.300 94.670 ;
        RECT 392.270 93.250 426.780 94.670 ;
        RECT 519.080 94.380 534.190 94.490 ;
        RECT 708.000 94.380 720.930 94.610 ;
        RECT 266.290 93.200 283.140 93.250 ;
        RECT 392.840 93.240 426.620 93.250 ;
        RECT 518.730 92.960 534.190 94.380 ;
        RECT 707.720 92.960 721.160 94.380 ;
        RECT 726.290 94.360 727.810 94.380 ;
        RECT 738.930 94.360 740.450 94.380 ;
        RECT 726.290 92.960 740.450 94.360 ;
        RECT 519.080 92.790 534.190 92.960 ;
        RECT 708.000 92.750 720.930 92.960 ;
        RECT 726.540 92.910 740.020 92.960 ;
        RECT 295.530 89.210 303.960 89.240 ;
        RECT 295.200 89.070 303.960 89.210 ;
        RECT 295.200 89.050 369.930 89.070 ;
        RECT 569.920 89.060 578.350 89.090 ;
        RECT 761.380 89.060 769.810 89.090 ;
        RECT 295.200 88.835 376.930 89.050 ;
        RECT 569.590 88.920 578.350 89.060 ;
        RECT 761.050 88.920 769.810 89.060 ;
        RECT 569.590 88.900 644.320 88.920 ;
        RECT 761.050 88.900 835.780 88.920 ;
        RECT 569.590 88.835 651.320 88.900 ;
        RECT 761.050 88.835 842.780 88.900 ;
        RECT 0.950 85.030 842.780 88.835 ;
        RECT 0.950 84.995 842.130 85.030 ;
        RECT 0.950 55.160 161.000 84.995 ;
        RECT 308.030 84.150 316.460 84.995 ;
        RECT 319.070 82.660 321.150 84.995 ;
        RECT 331.950 83.150 334.400 84.995 ;
        RECT 331.255 82.920 335.105 83.150 ;
        RECT 353.470 83.100 355.660 84.995 ;
        RECT 352.615 82.870 356.465 83.100 ;
        RECT 319.050 82.200 321.150 82.660 ;
        RECT 307.950 81.960 310.300 82.110 ;
        RECT 301.625 81.730 311.625 81.960 ;
        RECT 312.805 81.730 322.805 81.960 ;
        RECT 301.190 81.370 301.420 81.680 ;
        RECT 307.950 81.670 310.300 81.730 ;
        RECT 298.460 80.720 301.420 81.370 ;
        RECT 311.830 81.550 312.060 81.680 ;
        RECT 312.370 81.550 312.600 81.680 ;
        RECT 314.190 81.570 316.460 81.730 ;
        RECT 298.460 80.390 301.300 80.720 ;
        RECT 302.030 80.670 304.270 80.780 ;
        RECT 311.830 80.720 312.600 81.550 ;
        RECT 323.010 80.720 323.240 81.680 ;
        RECT 301.625 80.440 311.625 80.670 ;
        RECT 298.460 79.430 301.420 80.390 ;
        RECT 302.030 80.280 304.270 80.440 ;
        RECT 311.890 80.390 312.540 80.720 ;
        RECT 319.630 80.670 321.830 80.710 ;
        RECT 330.820 80.680 331.050 82.870 ;
        RECT 335.310 82.470 335.540 82.870 ;
        RECT 352.180 82.470 352.410 82.820 ;
        RECT 335.310 80.990 352.410 82.470 ;
        RECT 335.310 80.680 335.540 80.990 ;
        RECT 312.805 80.440 322.805 80.670 ;
        RECT 352.180 80.630 352.410 80.990 ;
        RECT 356.670 80.630 356.900 82.820 ;
        RECT 311.830 79.430 312.600 80.390 ;
        RECT 319.630 80.180 321.830 80.440 ;
        RECT 331.255 80.400 335.105 80.630 ;
        RECT 298.460 79.100 301.300 79.430 ;
        RECT 307.990 79.380 310.290 79.430 ;
        RECT 301.625 79.150 311.625 79.380 ;
        RECT 298.460 78.140 301.420 79.100 ;
        RECT 307.990 79.040 310.290 79.150 ;
        RECT 311.890 79.100 312.540 79.430 ;
        RECT 314.190 79.380 316.440 79.490 ;
        RECT 323.010 79.430 323.240 80.390 ;
        RECT 312.805 79.150 322.805 79.380 ;
        RECT 298.460 77.810 301.300 78.140 ;
        RECT 302.000 78.090 304.240 78.270 ;
        RECT 311.830 78.140 312.600 79.100 ;
        RECT 314.190 79.090 316.440 79.150 ;
        RECT 301.625 77.860 311.625 78.090 ;
        RECT 298.460 77.530 301.420 77.810 ;
        RECT 302.000 77.770 304.240 77.860 ;
        RECT 311.890 77.810 312.540 78.140 ;
        RECT 319.630 78.090 321.830 78.250 ;
        RECT 323.010 78.140 323.240 79.100 ;
        RECT 312.805 77.860 322.805 78.090 ;
        RECT 288.885 76.850 301.420 77.530 ;
        RECT 311.830 76.850 312.600 77.810 ;
        RECT 319.630 77.720 321.830 77.860 ;
        RECT 288.885 76.520 301.300 76.850 ;
        RECT 307.970 76.800 310.250 76.840 ;
        RECT 301.625 76.570 311.625 76.800 ;
        RECT 288.885 75.560 301.420 76.520 ;
        RECT 307.970 76.340 310.250 76.570 ;
        RECT 311.890 76.520 312.540 76.850 ;
        RECT 314.250 76.800 316.500 76.880 ;
        RECT 323.010 76.850 323.240 77.810 ;
        RECT 332.100 77.070 334.290 80.400 ;
        RECT 352.615 80.350 356.465 80.580 ;
        RECT 331.305 76.840 335.305 77.070 ;
        RECT 353.000 76.910 355.850 80.350 ;
        RECT 374.730 77.020 376.850 77.100 ;
        RECT 312.805 76.570 322.805 76.800 ;
        RECT 288.885 75.460 301.300 75.560 ;
        RECT 302.010 75.510 304.250 75.650 ;
        RECT 311.830 75.560 312.600 76.520 ;
        RECT 314.250 76.480 316.500 76.570 ;
        RECT 298.460 75.230 301.300 75.460 ;
        RECT 301.625 75.280 311.625 75.510 ;
        RECT 298.460 74.640 301.420 75.230 ;
        RECT 302.010 75.150 304.250 75.280 ;
        RECT 311.890 75.230 312.540 75.560 ;
        RECT 319.650 75.510 321.850 75.590 ;
        RECT 323.010 75.560 323.240 76.520 ;
        RECT 312.805 75.280 322.805 75.510 ;
        RECT 301.190 74.270 301.420 74.640 ;
        RECT 311.830 74.420 312.600 75.230 ;
        RECT 319.650 75.060 321.850 75.280 ;
        RECT 311.830 74.270 312.060 74.420 ;
        RECT 312.370 74.270 312.600 74.420 ;
        RECT 307.990 74.220 310.230 74.270 ;
        RECT 314.240 74.220 316.490 74.290 ;
        RECT 323.010 74.270 323.240 75.230 ;
        RECT 330.870 74.600 331.100 76.790 ;
        RECT 335.510 76.420 335.740 76.790 ;
        RECT 352.505 76.680 356.505 76.910 ;
        RECT 356.890 76.630 379.625 77.020 ;
        RECT 352.070 76.420 352.300 76.630 ;
        RECT 335.510 74.760 352.300 76.420 ;
        RECT 335.510 74.600 335.740 74.760 ;
        RECT 332.280 74.550 334.730 74.590 ;
        RECT 331.305 74.320 335.305 74.550 ;
        RECT 352.070 74.440 352.300 74.760 ;
        RECT 356.710 76.620 379.625 76.630 ;
        RECT 356.710 75.340 379.710 76.620 ;
        RECT 356.710 74.590 379.625 75.340 ;
        RECT 356.710 74.440 356.940 74.590 ;
        RECT 332.280 74.240 334.730 74.320 ;
        RECT 301.625 73.990 311.625 74.220 ;
        RECT 312.805 73.990 322.805 74.220 ;
        RECT 352.505 74.160 356.505 74.390 ;
        RECT 307.990 73.900 310.230 73.990 ;
        RECT 314.240 73.890 316.490 73.990 ;
        RECT 353.080 73.260 356.100 74.160 ;
        RECT 369.250 73.260 371.080 73.450 ;
        RECT 353.080 72.060 371.080 73.260 ;
        RECT 353.090 71.780 371.080 72.060 ;
        RECT 306.780 68.190 309.720 68.340 ;
        RECT 306.770 67.830 309.720 68.190 ;
        RECT 306.780 67.730 309.720 67.830 ;
        RECT 346.280 67.770 348.780 68.250 ;
        RECT 302.750 67.530 304.360 67.650 ;
        RECT 306.020 67.530 310.510 67.570 ;
        RECT 316.310 67.530 318.190 67.680 ;
        RECT 319.600 67.530 323.890 67.690 ;
        RECT 342.040 67.530 343.750 67.630 ;
        RECT 345.120 67.530 350.910 67.630 ;
        RECT 356.030 67.530 357.740 67.650 ;
        RECT 358.820 67.530 364.610 67.710 ;
        RECT 301.655 67.300 314.155 67.530 ;
        RECT 315.335 67.300 327.835 67.530 ;
        RECT 341.255 67.300 353.755 67.530 ;
        RECT 354.935 67.300 367.435 67.530 ;
        RECT 297.370 65.680 299.410 65.710 ;
        RECT 301.220 65.680 301.450 67.250 ;
        RECT 302.750 67.010 304.360 67.300 ;
        RECT 306.020 67.210 310.510 67.300 ;
        RECT 297.370 59.220 301.450 65.680 ;
        RECT 297.370 58.640 299.410 59.220 ;
        RECT 295.160 58.055 299.410 58.640 ;
        RECT 290.995 56.145 299.410 58.055 ;
        RECT 301.220 57.290 301.450 59.220 ;
        RECT 314.360 65.660 314.590 67.250 ;
        RECT 314.900 65.660 315.130 67.250 ;
        RECT 316.310 67.050 318.190 67.300 ;
        RECT 319.600 67.130 323.890 67.300 ;
        RECT 314.360 59.190 315.130 65.660 ;
        RECT 305.430 57.240 307.610 57.470 ;
        RECT 314.360 57.290 314.590 59.190 ;
        RECT 314.900 57.290 315.130 59.190 ;
        RECT 321.110 57.240 323.760 57.390 ;
        RECT 328.040 57.290 328.270 67.250 ;
        RECT 340.820 66.120 341.050 67.250 ;
        RECT 342.040 67.090 343.750 67.300 ;
        RECT 345.120 67.140 350.910 67.300 ;
        RECT 336.970 58.120 341.050 66.120 ;
        RECT 301.655 57.010 314.155 57.240 ;
        RECT 315.335 57.010 327.835 57.240 ;
        RECT 290.995 55.160 292.905 56.145 ;
        RECT 295.160 56.030 299.410 56.145 ;
        RECT 0.950 53.250 292.905 55.160 ;
        RECT 297.320 55.600 299.410 56.030 ;
        RECT 301.220 55.600 301.450 56.960 ;
        RECT 305.430 56.490 307.610 57.010 ;
        RECT 0.950 13.230 161.000 53.250 ;
        RECT 164.050 44.925 166.040 46.815 ;
        RECT 164.100 43.920 165.990 44.925 ;
        RECT 170.170 43.920 170.420 44.100 ;
        RECT 164.100 42.030 170.420 43.920 ;
        RECT 178.495 43.720 178.745 43.835 ;
        RECT 189.040 43.750 189.290 43.910 ;
        RECT 170.170 41.995 170.420 42.030 ;
        RECT 173.160 41.840 179.100 43.720 ;
        RECT 170.170 30.960 170.420 31.105 ;
        RECT 173.160 30.960 175.040 41.840 ;
        RECT 178.495 41.730 178.745 41.840 ;
        RECT 182.350 41.810 189.500 43.750 ;
        RECT 170.150 29.080 175.040 30.960 ;
        RECT 178.495 30.690 178.745 30.840 ;
        RECT 182.350 30.690 184.290 41.810 ;
        RECT 189.040 41.805 189.290 41.810 ;
        RECT 170.170 29.000 170.420 29.080 ;
        RECT 178.495 28.750 184.290 30.690 ;
        RECT 189.040 30.520 189.290 30.915 ;
        RECT 193.550 30.520 195.230 53.250 ;
        RECT 297.320 48.410 301.450 55.600 ;
        RECT 297.630 48.360 301.450 48.410 ;
        RECT 301.220 47.000 301.450 48.360 ;
        RECT 314.360 55.600 314.590 56.960 ;
        RECT 314.900 55.600 315.130 56.960 ;
        RECT 321.110 56.720 323.760 57.010 ;
        RECT 314.360 48.370 315.130 55.600 ;
        RECT 302.800 46.950 304.340 47.130 ;
        RECT 314.360 47.000 314.590 48.370 ;
        RECT 314.900 47.000 315.130 48.370 ;
        RECT 316.270 46.950 318.150 47.190 ;
        RECT 328.040 47.000 328.270 56.960 ;
        RECT 336.970 56.170 339.300 58.120 ;
        RECT 340.820 57.290 341.050 58.120 ;
        RECT 353.960 66.190 354.190 67.250 ;
        RECT 354.500 66.190 354.730 67.250 ;
        RECT 356.030 67.110 357.740 67.300 ;
        RECT 358.820 67.220 364.610 67.300 ;
        RECT 353.960 58.160 354.730 66.190 ;
        RECT 350.140 57.240 352.520 57.410 ;
        RECT 353.960 57.290 354.190 58.160 ;
        RECT 354.500 57.290 354.730 58.160 ;
        RECT 358.970 57.240 361.800 57.340 ;
        RECT 367.640 57.290 367.870 67.250 ;
        RECT 369.250 62.010 371.080 71.780 ;
        RECT 394.230 63.635 396.240 65.545 ;
        RECT 369.250 60.250 371.100 62.010 ;
        RECT 394.280 60.840 396.190 63.635 ;
        RECT 341.255 57.010 353.755 57.240 ;
        RECT 354.935 57.010 367.435 57.240 ;
        RECT 340.820 56.170 341.050 56.960 ;
        RECT 350.140 56.510 352.520 57.010 ;
        RECT 336.970 48.000 341.050 56.170 ;
        RECT 301.655 46.720 314.155 46.950 ;
        RECT 315.335 46.720 327.835 46.950 ;
        RECT 302.800 46.640 304.340 46.720 ;
        RECT 316.270 46.560 318.150 46.720 ;
        RECT 272.310 43.920 329.930 43.950 ;
        RECT 336.970 43.920 339.300 48.000 ;
        RECT 340.820 47.000 341.050 48.000 ;
        RECT 353.960 56.240 354.190 56.960 ;
        RECT 354.500 56.240 354.730 56.960 ;
        RECT 358.970 56.500 361.800 57.010 ;
        RECT 353.960 48.140 354.730 56.240 ;
        RECT 341.900 46.950 343.610 47.160 ;
        RECT 353.960 47.000 354.190 48.140 ;
        RECT 354.500 47.000 354.730 48.140 ;
        RECT 356.090 46.950 357.800 47.160 ;
        RECT 367.640 47.000 367.870 56.960 ;
        RECT 369.270 55.360 371.100 60.250 ;
        RECT 394.980 60.215 395.230 60.840 ;
        RECT 395.740 59.970 396.060 60.050 ;
        RECT 395.740 59.020 399.070 59.970 ;
        RECT 395.740 58.960 396.060 59.020 ;
        RECT 394.980 58.155 395.230 58.525 ;
        RECT 394.045 55.360 395.955 58.155 ;
        RECT 369.270 53.450 396.085 55.360 ;
        RECT 341.255 46.720 353.755 46.950 ;
        RECT 354.935 46.720 367.435 46.950 ;
        RECT 341.900 46.620 343.610 46.720 ;
        RECT 356.090 46.620 357.800 46.720 ;
        RECT 369.270 44.640 371.100 53.450 ;
        RECT 388.765 48.190 390.675 53.450 ;
        RECT 388.380 45.290 391.380 48.190 ;
        RECT 369.270 44.580 371.650 44.640 ;
        RECT 272.310 40.930 339.300 43.920 ;
        RECT 328.420 40.900 339.300 40.930 ;
        RECT 366.510 43.210 371.650 44.580 ;
        RECT 366.510 42.950 371.100 43.210 ;
        RECT 366.510 42.940 371.060 42.950 ;
        RECT 366.510 39.230 368.680 42.940 ;
        RECT 365.530 39.000 369.530 39.230 ;
        RECT 369.770 39.160 384.830 39.370 ;
        RECT 366.510 38.990 368.680 39.000 ;
        RECT 369.770 38.950 385.290 39.160 ;
        RECT 357.950 38.820 359.480 38.910 ;
        RECT 365.140 38.820 365.370 38.950 ;
        RECT 357.950 38.130 365.370 38.820 ;
        RECT 357.950 35.550 359.480 38.130 ;
        RECT 365.140 37.990 365.370 38.130 ;
        RECT 366.880 37.940 368.330 38.020 ;
        RECT 369.690 37.990 385.290 38.950 ;
        RECT 365.530 37.710 369.530 37.940 ;
        RECT 369.770 37.710 385.290 37.990 ;
        RECT 366.880 37.600 368.330 37.710 ;
        RECT 383.650 37.620 385.290 37.710 ;
        RECT 365.130 37.020 366.270 37.480 ;
        RECT 306.120 35.460 307.950 35.510 ;
        RECT 304.910 35.230 308.910 35.460 ;
        RECT 306.120 35.180 307.950 35.230 ;
        RECT 303.920 34.980 304.340 35.160 ;
        RECT 302.590 34.230 304.340 34.980 ;
        RECT 188.910 28.840 195.230 30.520 ;
        RECT 299.330 29.990 301.640 31.240 ;
        RECT 189.040 28.810 189.290 28.840 ;
        RECT 178.495 28.735 178.745 28.750 ;
        RECT 169.870 28.585 170.770 28.610 ;
        RECT 169.870 28.270 170.795 28.585 ;
        RECT 169.945 26.835 170.795 28.270 ;
        RECT 178.160 27.980 179.060 28.320 ;
        RECT 188.700 28.040 189.610 28.380 ;
        RECT 178.205 26.835 179.055 27.980 ;
        RECT 188.750 27.470 189.610 28.040 ;
        RECT 188.750 26.835 189.600 27.470 ;
        RECT 169.945 25.985 189.600 26.835 ;
        RECT 178.165 13.230 179.015 25.985 ;
        RECT 302.590 25.270 303.600 34.230 ;
        RECT 303.920 34.160 304.340 34.230 ;
        RECT 304.520 34.220 304.750 35.180 ;
        RECT 309.070 35.080 309.300 35.180 ;
        RECT 310.660 35.080 359.500 35.550 ;
        RECT 309.070 34.340 359.500 35.080 ;
        RECT 309.070 34.220 309.300 34.340 ;
        RECT 306.030 34.170 308.080 34.190 ;
        RECT 304.910 33.940 308.910 34.170 ;
        RECT 306.030 33.880 308.080 33.940 ;
        RECT 310.660 33.560 359.500 34.340 ;
        RECT 365.220 33.760 366.270 37.020 ;
        RECT 365.220 33.410 366.370 33.760 ;
        RECT 365.350 33.360 366.370 33.410 ;
        RECT 369.300 33.220 376.060 33.230 ;
        RECT 367.030 33.070 368.360 33.190 ;
        RECT 366.250 32.840 369.050 33.070 ;
        RECT 367.030 32.790 368.360 32.840 ;
        RECT 369.300 32.790 380.165 33.220 ;
        RECT 365.860 32.550 366.090 32.790 ;
        RECT 361.940 32.020 366.090 32.550 ;
        RECT 305.980 28.110 308.030 28.150 ;
        RECT 305.620 27.880 308.420 28.110 ;
        RECT 305.980 27.840 308.030 27.880 ;
        RECT 305.230 26.870 305.460 27.830 ;
        RECT 308.580 27.610 308.810 27.830 ;
        RECT 308.580 27.590 311.630 27.610 ;
        RECT 308.580 26.900 311.650 27.590 ;
        RECT 308.580 26.870 308.810 26.900 ;
        RECT 305.620 26.590 308.420 26.820 ;
        RECT 306.020 25.270 308.060 26.590 ;
        RECT 302.590 24.450 308.060 25.270 ;
        RECT 310.310 25.140 311.650 26.900 ;
        RECT 361.940 25.140 363.680 32.020 ;
        RECT 365.860 31.830 366.090 32.020 ;
        RECT 369.210 31.830 380.165 32.790 ;
        RECT 366.250 31.550 369.050 31.780 ;
        RECT 369.300 31.570 380.165 31.830 ;
        RECT 374.790 31.550 380.165 31.570 ;
        RECT 310.310 24.480 363.690 25.140 ;
        RECT 303.340 24.440 308.060 24.450 ;
        RECT 306.020 13.410 308.060 24.440 ;
        RECT 309.560 23.070 363.690 24.480 ;
        RECT 309.560 23.020 311.650 23.070 ;
        RECT 309.560 22.670 311.250 23.020 ;
        RECT 366.830 13.410 368.440 31.550 ;
        RECT 302.610 13.380 369.790 13.410 ;
        RECT 295.080 13.370 369.790 13.380 ;
        RECT 295.080 13.230 376.870 13.370 ;
        RECT 398.120 13.230 399.070 59.020 ;
        RECT 423.070 30.420 426.910 84.995 ;
        RECT 582.420 84.000 590.850 84.995 ;
        RECT 593.460 82.510 595.540 84.995 ;
        RECT 606.340 83.000 608.790 84.995 ;
        RECT 605.645 82.770 609.495 83.000 ;
        RECT 627.860 82.950 630.050 84.995 ;
        RECT 773.880 84.000 782.310 84.995 ;
        RECT 627.005 82.720 630.855 82.950 ;
        RECT 593.440 82.050 595.540 82.510 ;
        RECT 582.340 81.810 584.690 81.960 ;
        RECT 576.015 81.580 586.015 81.810 ;
        RECT 587.195 81.580 597.195 81.810 ;
        RECT 500.840 80.100 543.010 81.560 ;
        RECT 575.580 81.220 575.810 81.530 ;
        RECT 582.340 81.520 584.690 81.580 ;
        RECT 572.850 80.570 575.810 81.220 ;
        RECT 586.220 81.400 586.450 81.530 ;
        RECT 586.760 81.400 586.990 81.530 ;
        RECT 588.580 81.420 590.850 81.580 ;
        RECT 572.850 80.240 575.690 80.570 ;
        RECT 576.420 80.520 578.660 80.630 ;
        RECT 586.220 80.570 586.990 81.400 ;
        RECT 597.400 80.570 597.630 81.530 ;
        RECT 576.015 80.290 586.015 80.520 ;
        RECT 500.840 36.520 502.300 80.100 ;
        RECT 572.850 79.280 575.810 80.240 ;
        RECT 576.420 80.130 578.660 80.290 ;
        RECT 586.280 80.240 586.930 80.570 ;
        RECT 594.020 80.520 596.220 80.560 ;
        RECT 605.210 80.530 605.440 82.720 ;
        RECT 609.700 82.320 609.930 82.720 ;
        RECT 626.570 82.320 626.800 82.670 ;
        RECT 609.700 80.840 626.800 82.320 ;
        RECT 609.700 80.530 609.930 80.840 ;
        RECT 587.195 80.290 597.195 80.520 ;
        RECT 626.570 80.480 626.800 80.840 ;
        RECT 631.060 80.480 631.290 82.670 ;
        RECT 784.920 82.510 787.000 84.995 ;
        RECT 797.800 83.000 800.250 84.995 ;
        RECT 797.105 82.770 800.955 83.000 ;
        RECT 819.320 82.950 821.510 84.995 ;
        RECT 818.465 82.720 822.315 82.950 ;
        RECT 784.900 82.050 787.000 82.510 ;
        RECT 773.800 81.810 776.150 81.960 ;
        RECT 767.475 81.580 777.475 81.810 ;
        RECT 778.655 81.580 788.655 81.810 ;
        RECT 767.040 81.220 767.270 81.530 ;
        RECT 773.800 81.520 776.150 81.580 ;
        RECT 764.310 80.570 767.270 81.220 ;
        RECT 777.680 81.400 777.910 81.530 ;
        RECT 778.220 81.400 778.450 81.530 ;
        RECT 780.040 81.420 782.310 81.580 ;
        RECT 586.220 79.280 586.990 80.240 ;
        RECT 594.020 80.030 596.220 80.290 ;
        RECT 605.645 80.250 609.495 80.480 ;
        RECT 572.850 78.950 575.690 79.280 ;
        RECT 582.380 79.230 584.680 79.280 ;
        RECT 576.015 79.000 586.015 79.230 ;
        RECT 572.850 77.990 575.810 78.950 ;
        RECT 582.380 78.890 584.680 79.000 ;
        RECT 586.280 78.950 586.930 79.280 ;
        RECT 588.580 79.230 590.830 79.340 ;
        RECT 597.400 79.280 597.630 80.240 ;
        RECT 587.195 79.000 597.195 79.230 ;
        RECT 572.850 77.660 575.690 77.990 ;
        RECT 576.390 77.940 578.630 78.120 ;
        RECT 586.220 77.990 586.990 78.950 ;
        RECT 588.580 78.940 590.830 79.000 ;
        RECT 576.015 77.710 586.015 77.940 ;
        RECT 572.850 77.380 575.810 77.660 ;
        RECT 576.390 77.620 578.630 77.710 ;
        RECT 586.280 77.660 586.930 77.990 ;
        RECT 594.020 77.940 596.220 78.100 ;
        RECT 597.400 77.990 597.630 78.950 ;
        RECT 587.195 77.710 597.195 77.940 ;
        RECT 559.555 76.700 575.810 77.380 ;
        RECT 586.220 76.700 586.990 77.660 ;
        RECT 594.020 77.570 596.220 77.710 ;
        RECT 559.555 76.510 575.690 76.700 ;
        RECT 582.360 76.650 584.640 76.690 ;
        RECT 559.430 76.370 575.690 76.510 ;
        RECT 576.015 76.420 586.015 76.650 ;
        RECT 559.430 75.410 575.810 76.370 ;
        RECT 582.360 76.190 584.640 76.420 ;
        RECT 586.280 76.370 586.930 76.700 ;
        RECT 588.640 76.650 590.890 76.730 ;
        RECT 597.400 76.700 597.630 77.660 ;
        RECT 606.490 76.920 608.680 80.250 ;
        RECT 627.005 80.200 630.855 80.430 ;
        RECT 764.310 80.240 767.150 80.570 ;
        RECT 767.880 80.520 770.120 80.630 ;
        RECT 777.680 80.570 778.450 81.400 ;
        RECT 788.860 80.570 789.090 81.530 ;
        RECT 767.475 80.290 777.475 80.520 ;
        RECT 605.695 76.690 609.695 76.920 ;
        RECT 627.390 76.760 630.240 80.200 ;
        RECT 764.310 79.280 767.270 80.240 ;
        RECT 767.880 80.130 770.120 80.290 ;
        RECT 777.740 80.240 778.390 80.570 ;
        RECT 785.480 80.520 787.680 80.560 ;
        RECT 796.670 80.530 796.900 82.720 ;
        RECT 801.160 82.320 801.390 82.720 ;
        RECT 818.030 82.320 818.260 82.670 ;
        RECT 801.160 80.840 818.260 82.320 ;
        RECT 801.160 80.530 801.390 80.840 ;
        RECT 778.655 80.290 788.655 80.520 ;
        RECT 818.030 80.480 818.260 80.840 ;
        RECT 822.520 80.480 822.750 82.670 ;
        RECT 777.680 79.280 778.450 80.240 ;
        RECT 785.480 80.030 787.680 80.290 ;
        RECT 797.105 80.250 800.955 80.480 ;
        RECT 764.310 78.950 767.150 79.280 ;
        RECT 773.840 79.230 776.140 79.280 ;
        RECT 767.475 79.000 777.475 79.230 ;
        RECT 649.120 76.870 651.240 76.950 ;
        RECT 587.195 76.420 597.195 76.650 ;
        RECT 559.430 75.310 575.690 75.410 ;
        RECT 576.400 75.360 578.640 75.500 ;
        RECT 586.220 75.410 586.990 76.370 ;
        RECT 588.640 76.330 590.890 76.420 ;
        RECT 559.430 75.090 560.950 75.310 ;
        RECT 572.850 75.080 575.690 75.310 ;
        RECT 576.015 75.130 586.015 75.360 ;
        RECT 572.850 74.490 575.810 75.080 ;
        RECT 576.400 75.000 578.640 75.130 ;
        RECT 586.280 75.080 586.930 75.410 ;
        RECT 594.040 75.360 596.240 75.440 ;
        RECT 597.400 75.410 597.630 76.370 ;
        RECT 587.195 75.130 597.195 75.360 ;
        RECT 575.580 74.120 575.810 74.490 ;
        RECT 586.220 74.270 586.990 75.080 ;
        RECT 594.040 74.910 596.240 75.130 ;
        RECT 586.220 74.120 586.450 74.270 ;
        RECT 586.760 74.120 586.990 74.270 ;
        RECT 582.380 74.070 584.620 74.120 ;
        RECT 588.630 74.070 590.880 74.140 ;
        RECT 597.400 74.120 597.630 75.080 ;
        RECT 605.260 74.450 605.490 76.640 ;
        RECT 609.900 76.270 610.130 76.640 ;
        RECT 626.895 76.530 630.895 76.760 ;
        RECT 631.280 76.630 654.355 76.870 ;
        RECT 631.280 76.480 654.800 76.630 ;
        RECT 626.460 76.270 626.690 76.480 ;
        RECT 609.900 74.610 626.690 76.270 ;
        RECT 609.900 74.450 610.130 74.610 ;
        RECT 606.670 74.400 609.120 74.440 ;
        RECT 605.695 74.170 609.695 74.400 ;
        RECT 626.460 74.290 626.690 74.610 ;
        RECT 631.100 75.350 654.800 76.480 ;
        RECT 732.115 75.405 734.825 78.015 ;
        RECT 764.310 77.990 767.270 78.950 ;
        RECT 773.840 78.890 776.140 79.000 ;
        RECT 777.740 78.950 778.390 79.280 ;
        RECT 780.040 79.230 782.290 79.340 ;
        RECT 788.860 79.280 789.090 80.240 ;
        RECT 778.655 79.000 788.655 79.230 ;
        RECT 764.310 77.660 767.150 77.990 ;
        RECT 767.850 77.940 770.090 78.120 ;
        RECT 777.680 77.990 778.450 78.950 ;
        RECT 780.040 78.940 782.290 79.000 ;
        RECT 767.475 77.710 777.475 77.940 ;
        RECT 764.310 77.380 767.270 77.660 ;
        RECT 767.850 77.620 770.090 77.710 ;
        RECT 777.740 77.660 778.390 77.990 ;
        RECT 785.480 77.940 787.680 78.100 ;
        RECT 788.860 77.990 789.090 78.950 ;
        RECT 778.655 77.710 788.655 77.940 ;
        RECT 756.135 76.700 767.270 77.380 ;
        RECT 777.680 76.700 778.450 77.660 ;
        RECT 785.480 77.570 787.680 77.710 ;
        RECT 756.135 76.370 767.150 76.700 ;
        RECT 773.820 76.650 776.100 76.690 ;
        RECT 767.475 76.420 777.475 76.650 ;
        RECT 756.135 75.410 767.270 76.370 ;
        RECT 773.820 76.190 776.100 76.420 ;
        RECT 777.740 76.370 778.390 76.700 ;
        RECT 780.100 76.650 782.350 76.730 ;
        RECT 788.860 76.700 789.090 77.660 ;
        RECT 797.950 76.920 800.140 80.250 ;
        RECT 818.465 80.200 822.315 80.430 ;
        RECT 797.155 76.690 801.155 76.920 ;
        RECT 818.850 76.760 821.700 80.200 ;
        RECT 840.580 76.870 842.700 76.950 ;
        RECT 778.655 76.420 788.655 76.650 ;
        RECT 631.100 74.440 654.355 75.350 ;
        RECT 631.100 74.290 631.330 74.440 ;
        RECT 606.670 74.090 609.120 74.170 ;
        RECT 576.015 73.840 586.015 74.070 ;
        RECT 587.195 73.840 597.195 74.070 ;
        RECT 626.895 74.010 630.895 74.240 ;
        RECT 582.380 73.750 584.620 73.840 ;
        RECT 588.630 73.740 590.880 73.840 ;
        RECT 627.470 73.110 630.490 74.010 ;
        RECT 643.640 73.110 645.470 73.300 ;
        RECT 627.470 71.910 645.470 73.110 ;
        RECT 627.480 71.630 645.470 71.910 ;
        RECT 581.170 68.040 584.110 68.190 ;
        RECT 581.160 67.680 584.110 68.040 ;
        RECT 581.170 67.580 584.110 67.680 ;
        RECT 620.670 67.620 623.170 68.100 ;
        RECT 577.140 67.380 578.750 67.500 ;
        RECT 580.410 67.380 584.900 67.420 ;
        RECT 590.700 67.380 592.580 67.530 ;
        RECT 593.990 67.380 598.280 67.540 ;
        RECT 616.430 67.380 618.140 67.480 ;
        RECT 619.510 67.380 625.300 67.480 ;
        RECT 630.420 67.380 632.130 67.500 ;
        RECT 633.210 67.380 639.000 67.560 ;
        RECT 576.045 67.150 588.545 67.380 ;
        RECT 589.725 67.150 602.225 67.380 ;
        RECT 615.645 67.150 628.145 67.380 ;
        RECT 629.325 67.150 641.825 67.380 ;
        RECT 571.760 65.530 573.800 65.560 ;
        RECT 575.610 65.530 575.840 67.100 ;
        RECT 577.140 66.860 578.750 67.150 ;
        RECT 580.410 67.060 584.900 67.150 ;
        RECT 561.085 58.490 565.055 59.105 ;
        RECT 571.760 59.070 575.840 65.530 ;
        RECT 571.760 58.490 573.800 59.070 ;
        RECT 561.085 55.880 573.800 58.490 ;
        RECT 575.610 57.140 575.840 59.070 ;
        RECT 588.750 65.510 588.980 67.100 ;
        RECT 589.290 65.510 589.520 67.100 ;
        RECT 590.700 66.900 592.580 67.150 ;
        RECT 593.990 66.980 598.280 67.150 ;
        RECT 588.750 59.040 589.520 65.510 ;
        RECT 579.820 57.090 582.000 57.320 ;
        RECT 588.750 57.140 588.980 59.040 ;
        RECT 589.290 57.140 589.520 59.040 ;
        RECT 595.500 57.090 598.150 57.240 ;
        RECT 602.430 57.140 602.660 67.100 ;
        RECT 615.210 65.970 615.440 67.100 ;
        RECT 616.430 66.940 618.140 67.150 ;
        RECT 619.510 66.990 625.300 67.150 ;
        RECT 611.360 63.930 615.440 65.970 ;
        RECT 628.350 66.040 628.580 67.100 ;
        RECT 628.890 66.040 629.120 67.100 ;
        RECT 630.420 66.960 632.130 67.150 ;
        RECT 633.210 67.070 639.000 67.150 ;
        RECT 628.350 63.930 629.120 66.040 ;
        RECT 642.030 63.930 642.260 67.100 ;
        RECT 643.640 63.930 645.470 71.630 ;
        RECT 611.360 61.860 645.470 63.930 ;
        RECT 611.360 59.950 645.490 61.860 ;
        RECT 611.360 57.970 615.440 59.950 ;
        RECT 576.045 56.860 588.545 57.090 ;
        RECT 589.725 56.860 602.225 57.090 ;
        RECT 561.085 55.235 565.055 55.880 ;
        RECT 571.710 55.450 573.800 55.880 ;
        RECT 575.610 55.450 575.840 56.810 ;
        RECT 579.820 56.340 582.000 56.860 ;
        RECT 571.710 48.260 575.840 55.450 ;
        RECT 572.020 48.210 575.840 48.260 ;
        RECT 575.610 46.850 575.840 48.210 ;
        RECT 588.750 55.450 588.980 56.810 ;
        RECT 589.290 55.450 589.520 56.810 ;
        RECT 595.500 56.570 598.150 56.860 ;
        RECT 588.750 48.220 589.520 55.450 ;
        RECT 577.190 46.800 578.730 46.980 ;
        RECT 588.750 46.850 588.980 48.220 ;
        RECT 589.290 46.850 589.520 48.220 ;
        RECT 590.660 46.800 592.540 47.040 ;
        RECT 602.430 46.850 602.660 56.810 ;
        RECT 611.360 56.020 613.690 57.970 ;
        RECT 615.210 57.140 615.440 57.970 ;
        RECT 628.350 58.010 629.120 59.950 ;
        RECT 624.530 57.090 626.910 57.260 ;
        RECT 628.350 57.140 628.580 58.010 ;
        RECT 628.890 57.140 629.120 58.010 ;
        RECT 633.360 57.090 636.190 57.190 ;
        RECT 642.030 57.140 642.260 59.950 ;
        RECT 615.645 56.860 628.145 57.090 ;
        RECT 629.325 56.860 641.825 57.090 ;
        RECT 615.210 56.020 615.440 56.810 ;
        RECT 624.530 56.360 626.910 56.860 ;
        RECT 611.360 47.850 615.440 56.020 ;
        RECT 576.045 46.570 588.545 46.800 ;
        RECT 589.725 46.570 602.225 46.800 ;
        RECT 577.190 46.490 578.730 46.570 ;
        RECT 590.660 46.410 592.540 46.570 ;
        RECT 570.420 43.780 604.320 43.800 ;
        RECT 569.550 43.770 604.320 43.780 ;
        RECT 611.360 43.770 613.690 47.850 ;
        RECT 615.210 46.850 615.440 47.850 ;
        RECT 628.350 56.090 628.580 56.810 ;
        RECT 628.890 56.090 629.120 56.810 ;
        RECT 633.360 56.350 636.190 56.860 ;
        RECT 628.350 47.990 629.120 56.090 ;
        RECT 616.290 46.800 618.000 47.010 ;
        RECT 628.350 46.850 628.580 47.990 ;
        RECT 628.890 46.850 629.120 47.990 ;
        RECT 630.480 46.800 632.190 47.010 ;
        RECT 642.030 46.850 642.260 56.810 ;
        RECT 643.660 55.210 645.490 59.950 ;
        RECT 732.165 58.490 734.775 75.405 ;
        RECT 756.135 75.310 767.150 75.410 ;
        RECT 767.860 75.360 770.100 75.500 ;
        RECT 777.680 75.410 778.450 76.370 ;
        RECT 780.100 76.330 782.350 76.420 ;
        RECT 764.310 75.080 767.150 75.310 ;
        RECT 767.475 75.130 777.475 75.360 ;
        RECT 764.310 74.490 767.270 75.080 ;
        RECT 767.860 75.000 770.100 75.130 ;
        RECT 777.740 75.080 778.390 75.410 ;
        RECT 785.500 75.360 787.700 75.440 ;
        RECT 788.860 75.410 789.090 76.370 ;
        RECT 778.655 75.130 788.655 75.360 ;
        RECT 767.040 74.120 767.270 74.490 ;
        RECT 777.680 74.270 778.450 75.080 ;
        RECT 785.500 74.910 787.700 75.130 ;
        RECT 777.680 74.120 777.910 74.270 ;
        RECT 778.220 74.120 778.450 74.270 ;
        RECT 773.840 74.070 776.080 74.120 ;
        RECT 780.090 74.070 782.340 74.140 ;
        RECT 788.860 74.120 789.090 75.080 ;
        RECT 796.720 74.450 796.950 76.640 ;
        RECT 801.360 76.270 801.590 76.640 ;
        RECT 818.355 76.530 822.355 76.760 ;
        RECT 822.740 76.480 846.605 76.870 ;
        RECT 817.920 76.270 818.150 76.480 ;
        RECT 801.360 74.610 818.150 76.270 ;
        RECT 801.360 74.450 801.590 74.610 ;
        RECT 798.130 74.400 800.580 74.440 ;
        RECT 797.155 74.170 801.155 74.400 ;
        RECT 817.920 74.290 818.150 74.610 ;
        RECT 822.560 76.310 846.605 76.480 ;
        RECT 822.560 75.030 846.720 76.310 ;
        RECT 822.560 74.440 846.605 75.030 ;
        RECT 822.560 74.290 822.790 74.440 ;
        RECT 798.130 74.090 800.580 74.170 ;
        RECT 767.475 73.840 777.475 74.070 ;
        RECT 778.655 73.840 788.655 74.070 ;
        RECT 818.355 74.010 822.355 74.240 ;
        RECT 773.840 73.750 776.080 73.840 ;
        RECT 780.090 73.740 782.340 73.840 ;
        RECT 818.930 73.110 821.950 74.010 ;
        RECT 835.100 73.110 836.930 73.300 ;
        RECT 818.930 71.910 836.930 73.110 ;
        RECT 818.940 71.630 836.930 71.910 ;
        RECT 772.630 68.040 775.570 68.190 ;
        RECT 772.620 67.680 775.570 68.040 ;
        RECT 772.630 67.580 775.570 67.680 ;
        RECT 812.130 67.620 814.630 68.100 ;
        RECT 768.600 67.380 770.210 67.500 ;
        RECT 771.870 67.380 776.360 67.420 ;
        RECT 782.160 67.380 784.040 67.530 ;
        RECT 785.450 67.380 789.740 67.540 ;
        RECT 807.890 67.380 809.600 67.480 ;
        RECT 810.970 67.380 816.760 67.480 ;
        RECT 821.880 67.380 823.590 67.500 ;
        RECT 824.670 67.380 830.460 67.560 ;
        RECT 767.505 67.150 780.005 67.380 ;
        RECT 781.185 67.150 793.685 67.380 ;
        RECT 807.105 67.150 819.605 67.380 ;
        RECT 820.785 67.150 833.285 67.380 ;
        RECT 763.220 65.530 765.260 65.560 ;
        RECT 767.070 65.530 767.300 67.100 ;
        RECT 768.600 66.860 770.210 67.150 ;
        RECT 771.870 67.060 776.360 67.150 ;
        RECT 763.220 59.070 767.300 65.530 ;
        RECT 763.220 58.490 765.260 59.070 ;
        RECT 732.165 55.880 765.260 58.490 ;
        RECT 767.070 57.140 767.300 59.070 ;
        RECT 780.210 65.510 780.440 67.100 ;
        RECT 780.750 65.510 780.980 67.100 ;
        RECT 782.160 66.900 784.040 67.150 ;
        RECT 785.450 66.980 789.740 67.150 ;
        RECT 780.210 59.040 780.980 65.510 ;
        RECT 771.280 57.090 773.460 57.320 ;
        RECT 780.210 57.140 780.440 59.040 ;
        RECT 780.750 57.140 780.980 59.040 ;
        RECT 786.960 57.090 789.610 57.240 ;
        RECT 793.890 57.140 794.120 67.100 ;
        RECT 806.670 65.970 806.900 67.100 ;
        RECT 807.890 66.940 809.600 67.150 ;
        RECT 810.970 66.990 816.760 67.150 ;
        RECT 802.820 57.970 806.900 65.970 ;
        RECT 767.505 56.860 780.005 57.090 ;
        RECT 781.185 56.860 793.685 57.090 ;
        RECT 763.170 55.450 765.260 55.880 ;
        RECT 767.070 55.450 767.300 56.810 ;
        RECT 771.280 56.340 773.460 56.860 ;
        RECT 643.660 53.300 668.815 55.210 ;
        RECT 615.645 46.570 628.145 46.800 ;
        RECT 629.325 46.570 641.825 46.800 ;
        RECT 616.290 46.470 618.000 46.570 ;
        RECT 630.480 46.470 632.190 46.570 ;
        RECT 643.660 44.490 645.490 53.300 ;
        RECT 643.660 44.430 646.040 44.490 ;
        RECT 569.550 40.800 613.690 43.770 ;
        RECT 570.420 40.780 613.690 40.800 ;
        RECT 602.810 40.750 613.690 40.780 ;
        RECT 640.900 43.060 646.040 44.430 ;
        RECT 640.900 42.800 645.490 43.060 ;
        RECT 640.900 42.790 645.450 42.800 ;
        RECT 640.900 39.080 643.070 42.790 ;
        RECT 666.905 40.830 668.815 53.300 ;
        RECT 763.170 48.260 767.300 55.450 ;
        RECT 763.480 48.210 767.300 48.260 ;
        RECT 767.070 46.850 767.300 48.210 ;
        RECT 780.210 55.450 780.440 56.810 ;
        RECT 780.750 55.450 780.980 56.810 ;
        RECT 786.960 56.570 789.610 56.860 ;
        RECT 780.210 48.220 780.980 55.450 ;
        RECT 768.650 46.800 770.190 46.980 ;
        RECT 780.210 46.850 780.440 48.220 ;
        RECT 780.750 46.850 780.980 48.220 ;
        RECT 782.120 46.800 784.000 47.040 ;
        RECT 793.890 46.850 794.120 56.810 ;
        RECT 802.820 56.020 805.150 57.970 ;
        RECT 806.670 57.140 806.900 57.970 ;
        RECT 819.810 66.040 820.040 67.100 ;
        RECT 820.350 66.040 820.580 67.100 ;
        RECT 821.880 66.960 823.590 67.150 ;
        RECT 824.670 67.070 830.460 67.150 ;
        RECT 819.810 58.010 820.580 66.040 ;
        RECT 815.990 57.090 818.370 57.260 ;
        RECT 819.810 57.140 820.040 58.010 ;
        RECT 820.350 57.140 820.580 58.010 ;
        RECT 824.820 57.090 827.650 57.190 ;
        RECT 833.490 57.140 833.720 67.100 ;
        RECT 835.100 61.860 836.930 71.630 ;
        RECT 835.100 60.100 836.950 61.860 ;
        RECT 807.105 56.860 819.605 57.090 ;
        RECT 820.785 56.860 833.285 57.090 ;
        RECT 806.670 56.020 806.900 56.810 ;
        RECT 815.990 56.360 818.370 56.860 ;
        RECT 802.820 47.850 806.900 56.020 ;
        RECT 767.505 46.570 780.005 46.800 ;
        RECT 781.185 46.570 793.685 46.800 ;
        RECT 768.650 46.490 770.190 46.570 ;
        RECT 782.120 46.410 784.000 46.570 ;
        RECT 761.880 43.780 795.780 43.800 ;
        RECT 761.010 43.770 795.780 43.780 ;
        RECT 802.820 43.770 805.150 47.850 ;
        RECT 806.670 46.850 806.900 47.850 ;
        RECT 819.810 56.090 820.040 56.810 ;
        RECT 820.350 56.090 820.580 56.810 ;
        RECT 824.820 56.350 827.650 56.860 ;
        RECT 819.810 47.990 820.580 56.090 ;
        RECT 807.750 46.800 809.460 47.010 ;
        RECT 819.810 46.850 820.040 47.990 ;
        RECT 820.350 46.850 820.580 47.990 ;
        RECT 821.940 46.800 823.650 47.010 ;
        RECT 833.490 46.850 833.720 56.810 ;
        RECT 835.120 55.210 836.950 60.100 ;
        RECT 845.220 55.210 847.370 55.340 ;
        RECT 835.120 53.300 847.370 55.210 ;
        RECT 807.105 46.570 819.605 46.800 ;
        RECT 820.785 46.570 833.285 46.800 ;
        RECT 807.750 46.470 809.460 46.570 ;
        RECT 821.940 46.470 823.650 46.570 ;
        RECT 835.120 44.490 836.950 53.300 ;
        RECT 845.220 53.290 847.370 53.300 ;
        RECT 835.120 44.430 837.500 44.490 ;
        RECT 761.010 42.755 805.150 43.770 ;
        RECT 676.545 40.830 678.590 41.245 ;
        RECT 666.905 39.960 678.590 40.830 ;
        RECT 639.920 38.850 643.920 39.080 ;
        RECT 640.900 38.840 643.070 38.850 ;
        RECT 644.160 38.800 661.560 39.220 ;
        RECT 632.340 38.670 633.870 38.760 ;
        RECT 639.530 38.670 639.760 38.800 ;
        RECT 632.340 37.980 639.760 38.670 ;
        RECT 632.340 35.400 633.870 37.980 ;
        RECT 639.530 37.840 639.760 37.980 ;
        RECT 641.270 37.790 642.720 37.870 ;
        RECT 644.080 37.840 661.560 38.800 ;
        RECT 639.920 37.560 643.920 37.790 ;
        RECT 644.160 37.560 661.560 37.840 ;
        RECT 641.270 37.450 642.720 37.560 ;
        RECT 639.520 36.870 640.660 37.330 ;
        RECT 471.760 35.100 473.470 35.370 ;
        RECT 580.510 35.310 582.340 35.360 ;
        RECT 431.205 33.490 473.470 35.100 ;
        RECT 579.300 35.080 583.300 35.310 ;
        RECT 580.510 35.030 582.340 35.080 ;
        RECT 578.310 34.830 578.730 35.010 ;
        RECT 471.760 33.230 473.470 33.490 ;
        RECT 576.980 34.080 578.730 34.830 ;
        RECT 540.200 31.210 541.680 32.590 ;
        RECT 423.070 28.830 531.080 30.420 ;
        RECT 573.720 29.840 576.030 31.090 ;
        RECT 423.070 28.590 426.970 28.830 ;
        RECT 424.310 26.220 424.890 26.280 ;
        RECT 423.180 25.490 424.890 26.220 ;
        RECT 425.520 25.980 426.970 28.590 ;
        RECT 457.490 26.100 458.040 26.170 ;
        RECT 425.190 25.730 427.295 25.980 ;
        RECT 432.185 25.730 434.290 25.980 ;
        RECT 423.200 13.230 423.895 25.490 ;
        RECT 424.310 25.430 424.890 25.490 ;
        RECT 432.565 22.645 434.015 25.730 ;
        RECT 456.430 25.410 458.040 26.100 ;
        RECT 458.500 25.910 459.950 28.830 ;
        RECT 485.030 26.110 485.790 26.120 ;
        RECT 486.200 26.110 486.750 26.210 ;
        RECT 465.785 25.910 466.975 25.915 ;
        RECT 458.390 25.660 460.495 25.910 ;
        RECT 465.385 25.660 467.490 25.910 ;
        RECT 432.565 22.470 438.585 22.645 ;
        RECT 425.370 21.195 438.585 22.470 ;
        RECT 425.370 21.020 434.015 21.195 ;
        RECT 425.370 18.490 426.820 21.020 ;
        RECT 425.170 18.240 427.275 18.490 ;
        RECT 440.365 18.240 442.470 18.490 ;
        RECT 440.430 13.230 442.230 18.240 ;
        RECT 456.430 13.230 456.980 25.410 ;
        RECT 457.490 25.390 458.040 25.410 ;
        RECT 465.785 22.500 466.975 25.660 ;
        RECT 485.030 25.430 486.750 26.110 ;
        RECT 487.330 25.910 488.780 28.830 ;
        RECT 527.070 26.060 527.620 26.100 ;
        RECT 487.070 25.660 489.175 25.910 ;
        RECT 494.065 25.660 496.170 25.910 ;
        RECT 485.030 25.420 486.590 25.430 ;
        RECT 458.940 21.310 473.235 22.500 ;
        RECT 458.940 18.560 460.130 21.310 ;
        RECT 458.460 18.310 460.565 18.560 ;
        RECT 463.525 18.310 465.630 18.560 ;
        RECT 463.760 13.230 465.560 18.310 ;
        RECT 485.030 13.230 485.790 25.420 ;
        RECT 494.505 22.500 495.695 25.660 ;
        RECT 525.960 25.350 527.620 26.060 ;
        RECT 528.380 25.840 529.830 28.830 ;
        RECT 527.970 25.590 530.075 25.840 ;
        RECT 534.965 25.590 537.070 25.840 ;
        RECT 528.380 25.540 529.830 25.590 ;
        RECT 487.480 21.310 502.165 22.500 ;
        RECT 487.480 18.630 488.670 21.310 ;
        RECT 486.980 18.380 489.085 18.630 ;
        RECT 502.175 18.380 504.280 18.630 ;
        RECT 487.480 18.350 488.670 18.380 ;
        RECT 502.330 13.230 504.130 18.380 ;
        RECT 525.960 13.230 526.580 25.350 ;
        RECT 527.070 25.320 527.620 25.350 ;
        RECT 528.590 22.555 529.780 22.640 ;
        RECT 535.475 22.555 536.665 25.590 ;
        RECT 576.980 25.120 577.990 34.080 ;
        RECT 578.310 34.010 578.730 34.080 ;
        RECT 578.910 34.070 579.140 35.030 ;
        RECT 583.460 34.930 583.690 35.030 ;
        RECT 585.050 34.930 633.890 35.400 ;
        RECT 583.460 34.190 633.890 34.930 ;
        RECT 583.460 34.070 583.690 34.190 ;
        RECT 580.420 34.020 582.470 34.040 ;
        RECT 579.300 33.790 583.300 34.020 ;
        RECT 580.420 33.730 582.470 33.790 ;
        RECT 585.050 33.410 633.890 34.190 ;
        RECT 639.610 33.610 640.660 36.870 ;
        RECT 666.890 36.180 678.590 39.960 ;
        RECT 676.545 35.555 678.590 36.180 ;
        RECT 681.240 40.830 683.285 41.245 ;
        RECT 756.935 40.845 805.150 42.755 ;
        RECT 681.240 39.500 692.180 40.830 ;
        RECT 713.910 39.500 716.670 40.690 ;
        RECT 756.935 39.500 758.845 40.845 ;
        RECT 761.010 40.800 805.150 40.845 ;
        RECT 761.880 40.780 805.150 40.800 ;
        RECT 794.270 40.750 805.150 40.780 ;
        RECT 832.360 43.060 837.500 44.430 ;
        RECT 832.360 42.800 836.950 43.060 ;
        RECT 832.360 42.790 836.910 42.800 ;
        RECT 681.240 37.590 758.845 39.500 ;
        RECT 832.360 39.080 834.530 42.790 ;
        RECT 831.380 38.850 835.380 39.080 ;
        RECT 832.360 38.840 834.530 38.850 ;
        RECT 835.620 38.800 847.830 39.220 ;
        RECT 823.800 38.670 825.330 38.760 ;
        RECT 830.990 38.670 831.220 38.800 ;
        RECT 823.800 37.980 831.220 38.670 ;
        RECT 681.240 36.180 692.180 37.590 ;
        RECT 681.240 35.555 683.285 36.180 ;
        RECT 823.800 35.400 825.330 37.980 ;
        RECT 830.990 37.840 831.220 37.980 ;
        RECT 832.730 37.790 834.180 37.870 ;
        RECT 835.540 37.840 847.830 38.800 ;
        RECT 831.380 37.560 835.380 37.790 ;
        RECT 835.620 37.560 847.830 37.840 ;
        RECT 832.730 37.450 834.180 37.560 ;
        RECT 846.180 37.490 847.820 37.560 ;
        RECT 830.980 36.870 832.120 37.330 ;
        RECT 771.970 35.310 773.800 35.360 ;
        RECT 679.170 34.685 680.980 35.150 ;
        RECT 770.760 35.080 774.760 35.310 ;
        RECT 771.970 35.030 773.800 35.080 ;
        RECT 769.770 34.830 770.190 35.010 ;
        RECT 678.835 34.280 680.980 34.685 ;
        RECT 639.610 33.260 640.760 33.610 ;
        RECT 639.740 33.210 640.760 33.260 ;
        RECT 643.690 33.070 650.450 33.080 ;
        RECT 641.420 32.920 642.750 33.040 ;
        RECT 640.640 32.690 643.440 32.920 ;
        RECT 641.420 32.640 642.750 32.690 ;
        RECT 643.690 32.640 650.920 33.070 ;
        RECT 640.250 32.400 640.480 32.640 ;
        RECT 636.330 31.870 640.480 32.400 ;
        RECT 580.370 27.960 582.420 28.000 ;
        RECT 580.010 27.730 582.810 27.960 ;
        RECT 580.370 27.690 582.420 27.730 ;
        RECT 579.620 26.720 579.850 27.680 ;
        RECT 582.970 27.460 583.200 27.680 ;
        RECT 582.970 27.440 586.020 27.460 ;
        RECT 582.970 26.750 586.040 27.440 ;
        RECT 582.970 26.720 583.200 26.750 ;
        RECT 580.010 26.440 582.810 26.670 ;
        RECT 580.410 25.120 582.450 26.440 ;
        RECT 576.980 24.300 582.450 25.120 ;
        RECT 577.730 24.290 582.450 24.300 ;
        RECT 528.590 21.365 541.445 22.555 ;
        RECT 528.590 18.710 529.780 21.365 ;
        RECT 528.050 18.460 530.155 18.710 ;
        RECT 531.645 18.640 533.750 18.710 ;
        RECT 531.645 18.460 533.770 18.640 ;
        RECT 531.970 13.230 533.770 18.460 ;
        RECT 580.410 13.260 582.450 24.290 ;
        RECT 584.700 24.990 586.040 26.750 ;
        RECT 636.330 24.990 638.070 31.870 ;
        RECT 640.250 31.680 640.480 31.870 ;
        RECT 643.600 31.680 650.920 32.640 ;
        RECT 640.640 31.400 643.440 31.630 ;
        RECT 643.690 31.420 650.920 31.680 ;
        RECT 649.180 31.400 650.920 31.420 ;
        RECT 584.700 23.430 638.080 24.990 ;
        RECT 583.670 22.920 638.080 23.430 ;
        RECT 583.670 22.870 586.040 22.920 ;
        RECT 583.670 22.010 585.190 22.870 ;
        RECT 641.220 13.260 642.830 31.400 ;
        RECT 649.180 17.875 650.850 31.400 ;
        RECT 678.835 25.760 680.885 34.280 ;
        RECT 768.440 34.080 770.190 34.830 ;
        RECT 765.180 29.840 767.490 31.090 ;
        RECT 678.835 25.310 752.450 25.760 ;
        RECT 768.440 25.310 769.450 34.080 ;
        RECT 769.770 34.010 770.190 34.080 ;
        RECT 770.370 34.070 770.600 35.030 ;
        RECT 774.920 34.930 775.150 35.030 ;
        RECT 776.510 34.930 825.350 35.400 ;
        RECT 774.920 34.190 825.350 34.930 ;
        RECT 774.920 34.070 775.150 34.190 ;
        RECT 771.880 34.020 773.930 34.040 ;
        RECT 770.760 33.790 774.760 34.020 ;
        RECT 771.880 33.730 773.930 33.790 ;
        RECT 776.510 33.410 825.350 34.190 ;
        RECT 831.070 33.610 832.120 36.870 ;
        RECT 831.070 33.260 832.220 33.610 ;
        RECT 831.200 33.210 832.220 33.260 ;
        RECT 835.150 33.070 841.910 33.080 ;
        RECT 852.005 33.070 853.675 99.575 ;
        RECT 866.395 79.595 869.585 123.470 ;
        RECT 878.455 111.510 881.245 111.575 ;
        RECT 878.455 108.885 896.585 111.510 ;
        RECT 878.940 108.760 896.585 108.885 ;
        RECT 866.395 76.405 887.395 79.595 ;
        RECT 866.395 56.225 869.585 76.405 ;
        RECT 866.345 53.035 869.635 56.225 ;
        RECT 832.880 32.920 834.210 33.040 ;
        RECT 832.100 32.690 834.900 32.920 ;
        RECT 832.880 32.640 834.210 32.690 ;
        RECT 835.150 32.640 853.675 33.070 ;
        RECT 831.710 32.400 831.940 32.640 ;
        RECT 827.790 31.870 831.940 32.400 ;
        RECT 771.830 27.960 773.880 28.000 ;
        RECT 771.470 27.730 774.270 27.960 ;
        RECT 771.830 27.690 773.880 27.730 ;
        RECT 771.080 26.720 771.310 27.680 ;
        RECT 774.430 27.460 774.660 27.680 ;
        RECT 774.430 27.440 777.480 27.460 ;
        RECT 774.430 26.750 777.500 27.440 ;
        RECT 774.430 26.720 774.660 26.750 ;
        RECT 771.470 26.440 774.270 26.670 ;
        RECT 678.835 25.120 769.450 25.310 ;
        RECT 771.870 25.120 773.910 26.440 ;
        RECT 678.835 24.300 773.910 25.120 ;
        RECT 678.835 23.710 752.450 24.300 ;
        RECT 769.190 24.290 773.910 24.300 ;
        RECT 649.180 16.205 759.765 17.875 ;
        RECT 771.870 13.260 773.910 24.290 ;
        RECT 776.160 24.990 777.500 26.750 ;
        RECT 827.790 24.990 829.530 31.870 ;
        RECT 831.710 31.680 831.940 31.870 ;
        RECT 835.060 31.680 853.675 32.640 ;
        RECT 832.100 31.400 834.900 31.630 ;
        RECT 835.150 31.420 853.675 31.680 ;
        RECT 840.640 31.400 853.675 31.420 ;
        RECT 776.160 23.505 829.540 24.990 ;
        RECT 774.995 22.920 829.540 23.505 ;
        RECT 774.995 22.870 777.500 22.920 ;
        RECT 774.995 21.835 776.765 22.870 ;
        RECT 832.680 13.260 834.290 31.400 ;
        RECT 577.000 13.230 644.180 13.260 ;
        RECT 768.460 13.230 835.640 13.260 ;
        RECT 0.950 13.220 835.640 13.230 ;
        RECT 0.950 9.410 887.505 13.220 ;
        RECT 0.950 9.400 770.360 9.410 ;
        RECT 0.950 4.355 161.000 9.400 ;
        RECT 569.500 9.370 571.360 9.400 ;
        RECT 760.960 9.370 762.820 9.400 ;
        RECT 893.835 4.355 896.585 108.760 ;
        RECT 0.950 1.605 896.585 4.355 ;
      LAYER met2 ;
        RECT 1.000 132.830 161.000 221.390 ;
        RECT 259.570 218.440 267.900 221.040 ;
        RECT 489.180 218.790 497.510 221.390 ;
        RECT 259.580 216.500 261.670 218.440 ;
        RECT 259.490 215.960 261.740 216.500 ;
        RECT 265.790 216.340 267.900 218.440 ;
        RECT 489.190 216.850 491.280 218.790 ;
        RECT 253.570 212.660 255.730 215.360 ;
        RECT 253.540 212.060 255.730 212.660 ;
        RECT 240.330 211.120 241.750 211.570 ;
        RECT 227.250 209.700 241.750 211.120 ;
        RECT 253.570 210.040 255.730 212.060 ;
        RECT 164.930 132.830 167.570 189.930 ;
        RECT 1.000 130.190 167.570 132.830 ;
        RECT 1.000 127.180 161.000 130.190 ;
        RECT 1.000 127.070 181.200 127.180 ;
        RECT 1.000 124.710 182.160 127.070 ;
        RECT 1.000 124.690 181.200 124.710 ;
        RECT 1.000 120.300 161.000 124.690 ;
        RECT 1.000 119.995 197.580 120.300 ;
        RECT 1.000 117.300 198.520 119.995 ;
        RECT 1.000 111.540 161.000 117.300 ;
        RECT 195.890 117.265 198.520 117.300 ;
        RECT 1.000 109.480 167.900 111.540 ;
        RECT 1.000 94.670 161.000 109.480 ;
        RECT 227.250 94.670 228.670 209.700 ;
        RECT 253.550 209.440 255.730 210.040 ;
        RECT 253.570 207.050 255.730 209.440 ;
        RECT 259.510 213.820 261.710 215.960 ;
        RECT 265.730 215.860 267.900 216.340 ;
        RECT 265.790 213.880 267.900 215.860 ;
        RECT 294.090 215.450 296.110 216.600 ;
        RECT 489.100 216.310 491.350 216.850 ;
        RECT 495.400 216.690 497.510 218.790 ;
        RECT 271.170 214.470 273.270 215.100 ;
        RECT 259.510 213.330 261.730 213.820 ;
        RECT 265.730 213.380 267.900 213.880 ;
        RECT 259.510 208.150 261.710 213.330 ;
        RECT 265.790 211.270 267.900 213.380 ;
        RECT 271.200 212.640 273.200 214.470 ;
        RECT 483.180 213.010 485.340 215.710 ;
        RECT 271.170 212.010 273.270 212.640 ;
        RECT 483.150 212.410 485.340 213.010 ;
        RECT 265.790 210.770 267.940 211.270 ;
        RECT 265.790 208.680 267.900 210.770 ;
        RECT 271.200 209.980 273.200 212.010 ;
        RECT 271.190 209.350 273.290 209.980 ;
        RECT 332.550 209.630 333.830 211.010 ;
        RECT 265.780 208.180 267.930 208.680 ;
        RECT 265.790 208.130 267.900 208.180 ;
        RECT 271.200 207.050 273.200 209.350 ;
        RECT 283.820 208.530 286.170 208.980 ;
        RECT 253.570 206.380 273.200 207.050 ;
        RECT 253.610 205.570 273.200 206.380 ;
        RECT 253.610 205.290 314.730 205.570 ;
        RECT 253.610 205.050 316.290 205.290 ;
        RECT 254.290 201.300 255.800 202.040 ;
        RECT 256.820 201.730 262.590 205.050 ;
        RECT 270.400 203.680 316.290 205.050 ;
        RECT 257.560 201.500 261.950 201.730 ;
        RECT 267.850 201.340 269.630 202.070 ;
        RECT 270.400 201.690 276.170 203.680 ;
        RECT 293.580 201.970 295.190 202.020 ;
        RECT 271.140 201.420 275.330 201.690 ;
        RECT 293.500 201.380 295.190 201.970 ;
        RECT 295.960 201.630 302.670 203.680 ;
        RECT 307.570 201.890 309.180 202.040 ;
        RECT 296.660 201.430 302.350 201.630 ;
        RECT 307.480 201.400 309.180 201.890 ;
        RECT 309.580 201.590 316.290 203.680 ;
        RECT 310.360 201.510 316.050 201.590 ;
        RECT 254.400 181.520 255.720 201.300 ;
        RECT 254.340 180.930 255.780 181.520 ;
        RECT 256.970 178.030 259.050 191.860 ;
        RECT 267.900 181.580 269.430 201.340 ;
        RECT 272.650 191.010 275.200 191.780 ;
        RECT 267.810 180.850 269.590 181.580 ;
        RECT 272.830 178.030 275.010 191.010 ;
        RECT 293.500 181.550 295.170 201.380 ;
        RECT 301.680 191.490 303.960 191.800 ;
        RECT 301.680 190.800 304.110 191.490 ;
        RECT 293.440 181.020 295.170 181.550 ;
        RECT 293.440 180.910 295.050 181.020 ;
        RECT 301.830 179.480 304.110 190.800 ;
        RECT 307.480 181.550 309.150 201.400 ;
        RECT 328.795 198.715 332.045 198.765 ;
        RECT 328.795 195.465 357.375 198.715 ;
        RECT 328.795 195.415 332.045 195.465 ;
        RECT 310.510 190.790 313.240 191.730 ;
        RECT 307.480 180.940 309.240 181.550 ;
        RECT 307.630 180.910 309.240 180.940 ;
        RECT 310.610 179.570 312.970 190.790 ;
        RECT 310.610 179.480 314.900 179.570 ;
        RECT 301.830 178.280 314.900 179.480 ;
        RECT 256.970 175.930 275.010 178.030 ;
        RECT 301.900 177.640 314.900 178.280 ;
        RECT 312.270 177.610 314.900 177.640 ;
        RECT 256.970 175.890 274.900 175.930 ;
        RECT 256.970 174.340 259.050 175.890 ;
        RECT 248.210 173.050 259.050 174.340 ;
        RECT 248.210 172.180 259.030 173.050 ;
        RECT 248.210 167.160 250.850 172.180 ;
        RECT 312.390 170.930 314.900 177.610 ;
        RECT 321.620 177.500 323.090 179.030 ;
        RECT 318.420 172.270 319.770 172.410 ;
        RECT 317.980 170.930 320.230 172.270 ;
        RECT 336.910 171.830 338.450 173.470 ;
        RECT 257.660 169.470 259.390 169.900 ;
        RECT 312.390 168.950 320.530 170.930 ;
        RECT 313.950 168.910 320.530 168.950 ;
        RECT 257.570 168.430 259.520 168.580 ;
        RECT 257.470 168.170 259.520 168.430 ;
        RECT 257.470 167.160 259.480 168.170 ;
        RECT 317.980 167.280 320.230 168.910 ;
        RECT 330.250 167.610 331.920 167.620 ;
        RECT 248.210 164.080 259.810 167.160 ;
        RECT 318.570 167.080 319.800 167.280 ;
        RECT 330.235 165.840 331.920 167.610 ;
        RECT 248.280 164.040 259.810 164.080 ;
        RECT 257.470 162.260 259.480 164.040 ;
        RECT 257.520 162.130 259.470 162.260 ;
        RECT 237.980 160.720 241.000 161.520 ;
        RECT 237.760 136.465 241.010 160.720 ;
        RECT 330.250 137.795 331.920 165.840 ;
        RECT 237.760 133.215 322.845 136.465 ;
        RECT 330.250 136.150 331.935 137.795 ;
        RECT 330.265 136.025 331.935 136.150 ;
        RECT 319.595 130.515 322.845 133.215 ;
        RECT 354.125 130.515 357.375 195.465 ;
        RECT 433.200 162.250 435.180 164.330 ;
        RECT 457.865 138.215 459.850 192.790 ;
        RECT 247.135 128.285 249.705 128.335 ;
        RECT 247.135 125.715 316.180 128.285 ;
        RECT 319.595 127.265 357.375 130.515 ;
        RECT 399.460 136.230 459.850 138.215 ;
        RECT 247.135 125.665 249.705 125.715 ;
        RECT 313.610 124.960 316.180 125.715 ;
        RECT 371.590 124.960 374.770 125.630 ;
        RECT 313.610 122.390 374.770 124.960 ;
        RECT 371.590 122.350 374.770 122.390 ;
        RECT 385.380 120.070 387.880 120.120 ;
        RECT 272.670 117.570 387.880 120.070 ;
        RECT 265.910 94.670 267.330 94.720 ;
        RECT 1.000 93.250 267.330 94.670 ;
        RECT 1.000 82.790 161.000 93.250 ;
        RECT 265.910 93.200 267.330 93.250 ;
        RECT 1.000 80.290 168.780 82.790 ;
        RECT 1.000 46.890 161.000 80.290 ;
        RECT 165.810 71.100 168.310 80.290 ;
        RECT 165.810 68.600 230.230 71.100 ;
        RECT 1.000 46.865 165.720 46.890 ;
        RECT 1.000 45.000 165.990 46.865 ;
        RECT 1.000 17.700 161.000 45.000 ;
        RECT 164.100 44.875 165.990 45.000 ;
        RECT 227.730 28.575 230.230 68.600 ;
        RECT 272.670 44.000 275.170 117.570 ;
        RECT 385.380 117.520 387.880 117.570 ;
        RECT 399.460 119.935 401.440 136.230 ;
        RECT 399.460 117.585 401.815 119.935 ;
        RECT 321.420 112.150 324.500 112.160 ;
        RECT 387.785 112.150 391.095 112.200 ;
        RECT 321.420 108.980 391.095 112.150 ;
        RECT 322.790 108.840 391.095 108.980 ;
        RECT 387.785 108.790 391.095 108.840 ;
        RECT 281.830 94.670 283.250 94.720 ;
        RECT 392.320 94.670 393.740 94.720 ;
        RECT 281.830 93.250 393.740 94.670 ;
        RECT 281.830 93.200 283.250 93.250 ;
        RECT 289.320 76.030 290.740 93.250 ;
        RECT 392.320 93.200 393.740 93.250 ;
        RECT 308.080 84.100 316.410 86.700 ;
        RECT 308.090 82.160 310.180 84.100 ;
        RECT 308.000 81.620 310.250 82.160 ;
        RECT 314.300 82.000 316.410 84.100 ;
        RECT 302.080 78.320 304.240 81.020 ;
        RECT 302.050 77.720 304.240 78.320 ;
        RECT 302.080 75.700 304.240 77.720 ;
        RECT 302.060 75.100 304.240 75.700 ;
        RECT 302.080 72.710 304.240 75.100 ;
        RECT 308.020 79.480 310.220 81.620 ;
        RECT 314.240 81.520 316.410 82.000 ;
        RECT 314.300 79.540 316.410 81.520 ;
        RECT 342.600 81.110 344.620 82.260 ;
        RECT 319.680 80.130 321.780 80.760 ;
        RECT 308.020 78.990 310.240 79.480 ;
        RECT 314.240 79.040 316.410 79.540 ;
        RECT 308.020 73.810 310.220 78.990 ;
        RECT 314.300 76.930 316.410 79.040 ;
        RECT 319.710 78.300 321.710 80.130 ;
        RECT 319.680 77.670 321.780 78.300 ;
        RECT 314.300 76.430 316.450 76.930 ;
        RECT 314.300 74.340 316.410 76.430 ;
        RECT 319.710 75.640 321.710 77.670 ;
        RECT 319.700 75.010 321.800 75.640 ;
        RECT 378.380 75.290 379.660 76.670 ;
        RECT 314.290 73.840 316.440 74.340 ;
        RECT 314.300 73.790 316.410 73.840 ;
        RECT 319.710 72.710 321.710 75.010 ;
        RECT 332.330 74.190 334.680 74.640 ;
        RECT 399.460 74.420 401.440 117.585 ;
        RECT 302.080 72.040 321.710 72.710 ;
        RECT 302.120 71.230 321.710 72.040 ;
        RECT 394.190 72.440 401.440 74.420 ;
        RECT 302.120 70.950 363.240 71.230 ;
        RECT 302.120 70.710 364.800 70.950 ;
        RECT 302.800 66.960 304.310 67.700 ;
        RECT 305.330 67.390 311.100 70.710 ;
        RECT 318.910 69.340 364.800 70.710 ;
        RECT 306.070 67.160 310.460 67.390 ;
        RECT 316.360 67.000 318.140 67.730 ;
        RECT 318.910 67.350 324.680 69.340 ;
        RECT 342.090 67.630 343.700 67.680 ;
        RECT 319.650 67.080 323.840 67.350 ;
        RECT 342.010 67.040 343.700 67.630 ;
        RECT 344.470 67.290 351.180 69.340 ;
        RECT 356.080 67.550 357.690 67.700 ;
        RECT 345.170 67.090 350.860 67.290 ;
        RECT 355.990 67.060 357.690 67.550 ;
        RECT 358.090 67.250 364.800 69.340 ;
        RECT 358.870 67.170 364.560 67.250 ;
        RECT 302.910 47.180 304.230 66.960 ;
        RECT 302.850 46.590 304.290 47.180 ;
        RECT 272.360 40.880 275.380 44.000 ;
        RECT 305.480 43.690 307.560 57.520 ;
        RECT 316.410 47.240 317.940 67.000 ;
        RECT 321.160 56.670 323.710 57.440 ;
        RECT 316.320 46.510 318.100 47.240 ;
        RECT 321.340 43.690 323.520 56.670 ;
        RECT 342.010 47.210 343.680 67.040 ;
        RECT 350.190 57.150 352.470 57.460 ;
        RECT 350.190 56.460 352.620 57.150 ;
        RECT 341.950 46.680 343.680 47.210 ;
        RECT 341.950 46.570 343.560 46.680 ;
        RECT 350.340 45.140 352.620 56.460 ;
        RECT 355.990 47.210 357.660 67.060 ;
        RECT 394.190 65.595 396.170 72.440 ;
        RECT 394.190 64.090 396.190 65.595 ;
        RECT 394.280 63.585 396.190 64.090 ;
        RECT 359.020 56.450 361.750 57.390 ;
        RECT 355.990 46.600 357.750 47.210 ;
        RECT 356.140 46.570 357.750 46.600 ;
        RECT 359.120 45.230 361.480 56.450 ;
        RECT 388.430 48.190 391.330 48.240 ;
        RECT 410.930 48.190 413.830 126.290 ;
        RECT 425.310 94.670 426.730 94.720 ;
        RECT 425.310 94.380 438.550 94.670 ;
        RECT 465.560 94.380 466.980 211.570 ;
        RECT 483.180 210.390 485.340 212.410 ;
        RECT 483.160 209.790 485.340 210.390 ;
        RECT 483.180 207.400 485.340 209.790 ;
        RECT 489.120 214.170 491.320 216.310 ;
        RECT 495.340 216.210 497.510 216.690 ;
        RECT 495.400 214.230 497.510 216.210 ;
        RECT 523.700 215.800 525.720 216.950 ;
        RECT 500.780 214.820 502.880 215.450 ;
        RECT 489.120 213.680 491.340 214.170 ;
        RECT 495.340 213.730 497.510 214.230 ;
        RECT 489.120 208.500 491.320 213.680 ;
        RECT 495.400 211.620 497.510 213.730 ;
        RECT 500.810 212.990 502.810 214.820 ;
        RECT 500.780 212.360 502.880 212.990 ;
        RECT 495.400 211.120 497.550 211.620 ;
        RECT 495.400 209.030 497.510 211.120 ;
        RECT 500.810 210.330 502.810 212.360 ;
        RECT 500.800 209.700 502.900 210.330 ;
        RECT 563.940 210.040 565.220 211.420 ;
        RECT 495.390 208.530 497.540 209.030 ;
        RECT 495.400 208.480 497.510 208.530 ;
        RECT 500.810 207.400 502.810 209.700 ;
        RECT 513.430 208.880 515.780 209.330 ;
        RECT 483.180 206.730 502.810 207.400 ;
        RECT 483.220 205.920 502.810 206.730 ;
        RECT 483.220 205.640 544.340 205.920 ;
        RECT 483.220 205.400 545.900 205.640 ;
        RECT 483.900 201.650 485.410 202.390 ;
        RECT 486.430 202.080 492.200 205.400 ;
        RECT 500.010 204.030 545.900 205.400 ;
        RECT 487.170 201.850 491.560 202.080 ;
        RECT 497.460 201.690 499.240 202.420 ;
        RECT 500.010 202.040 505.780 204.030 ;
        RECT 523.190 202.320 524.800 202.370 ;
        RECT 500.750 201.770 504.940 202.040 ;
        RECT 523.110 201.730 524.800 202.320 ;
        RECT 525.570 201.980 532.280 204.030 ;
        RECT 537.180 202.240 538.790 202.390 ;
        RECT 526.270 201.780 531.960 201.980 ;
        RECT 537.090 201.750 538.790 202.240 ;
        RECT 539.190 201.940 545.900 204.030 ;
        RECT 539.970 201.860 545.660 201.940 ;
        RECT 484.010 181.870 485.330 201.650 ;
        RECT 483.950 181.280 485.390 181.870 ;
        RECT 486.580 178.380 488.660 192.210 ;
        RECT 497.510 181.930 499.040 201.690 ;
        RECT 502.260 191.360 504.810 192.130 ;
        RECT 497.420 181.200 499.200 181.930 ;
        RECT 502.440 178.380 504.620 191.360 ;
        RECT 523.110 181.900 524.780 201.730 ;
        RECT 531.290 191.840 533.570 192.150 ;
        RECT 531.290 191.150 533.720 191.840 ;
        RECT 523.050 181.370 524.780 181.900 ;
        RECT 523.050 181.260 524.660 181.370 ;
        RECT 531.440 179.830 533.720 191.150 ;
        RECT 537.090 181.900 538.760 201.750 ;
        RECT 714.140 195.900 716.420 198.280 ;
        RECT 540.120 191.140 542.850 192.080 ;
        RECT 537.090 181.290 538.850 181.900 ;
        RECT 537.240 181.260 538.850 181.290 ;
        RECT 540.220 179.920 542.580 191.140 ;
        RECT 540.220 179.830 544.510 179.920 ;
        RECT 531.440 178.630 544.510 179.830 ;
        RECT 486.580 176.280 504.620 178.380 ;
        RECT 531.510 177.990 544.510 178.630 ;
        RECT 541.880 177.960 544.510 177.990 ;
        RECT 486.580 176.240 504.510 176.280 ;
        RECT 486.580 174.690 488.660 176.240 ;
        RECT 477.820 173.400 488.660 174.690 ;
        RECT 477.820 172.530 488.640 173.400 ;
        RECT 477.820 167.510 480.460 172.530 ;
        RECT 542.000 171.280 544.510 177.960 ;
        RECT 551.230 177.850 552.700 179.380 ;
        RECT 548.030 172.620 549.380 172.760 ;
        RECT 547.590 171.280 549.840 172.620 ;
        RECT 574.130 172.180 575.670 173.820 ;
        RECT 487.270 169.820 489.000 170.250 ;
        RECT 542.000 169.300 550.140 171.280 ;
        RECT 543.560 169.260 550.140 169.300 ;
        RECT 487.180 168.780 489.130 168.930 ;
        RECT 487.080 168.520 489.130 168.780 ;
        RECT 487.080 167.510 489.090 168.520 ;
        RECT 547.590 167.630 549.840 169.260 ;
        RECT 477.820 164.430 489.420 167.510 ;
        RECT 548.180 167.430 549.410 167.630 ;
        RECT 477.890 164.390 489.420 164.430 ;
        RECT 487.080 162.610 489.090 164.390 ;
        RECT 487.130 162.480 489.080 162.610 ;
        RECT 679.430 161.820 684.190 166.680 ;
        RECT 847.955 151.865 851.145 155.155 ;
        RECT 876.205 154.055 881.055 159.005 ;
        RECT 665.250 148.110 669.310 148.160 ;
        RECT 554.060 144.100 669.310 148.110 ;
        RECT 554.070 144.050 669.310 144.100 ;
        RECT 665.250 144.000 669.310 144.050 ;
        RECT 877.375 134.995 880.885 135.045 ;
        RECT 700.625 134.645 880.885 134.995 ;
        RECT 617.345 131.485 880.885 134.645 ;
        RECT 617.345 131.135 704.135 131.485 ;
        RECT 877.375 131.435 880.885 131.485 ;
        RECT 617.345 122.745 620.855 131.135 ;
        RECT 700.625 130.910 704.135 131.135 ;
        RECT 556.525 122.650 620.855 122.745 ;
        RECT 555.940 119.235 620.855 122.650 ;
        RECT 686.430 121.830 690.930 122.900 ;
        RECT 748.760 121.830 751.300 121.880 ;
        RECT 686.430 119.290 751.300 121.830 ;
        RECT 555.940 118.570 559.390 119.235 ;
        RECT 686.430 118.300 690.930 119.290 ;
        RECT 748.760 119.240 751.300 119.290 ;
        RECT 592.265 113.640 595.075 113.690 ;
        RECT 524.080 110.360 527.820 112.560 ;
        RECT 545.130 110.830 595.075 113.640 ;
        RECT 592.265 110.780 595.075 110.830 ;
        RECT 523.880 108.720 527.820 110.360 ;
        RECT 518.780 94.380 520.200 94.430 ;
        RECT 425.310 93.250 520.370 94.380 ;
        RECT 425.310 93.200 426.730 93.250 ;
        RECT 388.430 45.290 413.830 48.190 ;
        RECT 437.130 92.960 520.370 93.250 ;
        RECT 388.430 45.240 391.330 45.290 ;
        RECT 359.120 45.140 363.410 45.230 ;
        RECT 350.340 43.940 363.410 45.140 ;
        RECT 305.480 41.590 323.520 43.690 ;
        RECT 350.410 43.300 363.410 43.940 ;
        RECT 360.780 43.270 363.410 43.300 ;
        RECT 305.480 41.550 323.410 41.590 ;
        RECT 305.480 40.000 307.560 41.550 ;
        RECT 296.720 38.710 307.560 40.000 ;
        RECT 296.720 37.840 307.540 38.710 ;
        RECT 296.720 32.820 299.360 37.840 ;
        RECT 360.900 36.590 363.410 43.270 ;
        RECT 370.130 43.160 371.600 44.690 ;
        RECT 366.930 37.930 368.280 38.070 ;
        RECT 366.490 36.590 368.740 37.930 ;
        RECT 383.700 37.570 385.240 39.210 ;
        RECT 306.170 35.130 307.900 35.560 ;
        RECT 360.900 34.610 369.040 36.590 ;
        RECT 431.255 35.050 432.865 35.150 ;
        RECT 362.460 34.570 369.040 34.610 ;
        RECT 306.080 34.090 308.030 34.240 ;
        RECT 305.980 33.830 308.030 34.090 ;
        RECT 305.980 32.820 307.990 33.830 ;
        RECT 366.490 32.940 368.740 34.570 ;
        RECT 417.580 33.440 432.865 35.050 ;
        RECT 296.720 29.740 308.320 32.820 ;
        RECT 367.080 32.740 368.310 32.940 ;
        RECT 378.445 31.500 380.115 33.270 ;
        RECT 296.790 29.700 308.320 29.740 ;
        RECT 208.750 26.110 230.230 28.575 ;
        RECT 305.980 27.920 307.990 29.700 ;
        RECT 306.030 27.790 307.980 27.920 ;
        RECT 208.750 20.530 211.215 26.110 ;
        RECT 227.730 26.090 230.230 26.110 ;
        RECT 309.610 22.620 311.200 24.530 ;
        RECT 309.660 21.870 311.200 22.620 ;
        RECT 295.250 20.330 311.200 21.870 ;
        RECT 295.250 17.700 296.790 20.330 ;
        RECT 1.000 16.160 296.790 17.700 ;
        RECT 378.475 18.475 380.085 31.500 ;
        RECT 417.580 18.475 419.190 33.440 ;
        RECT 437.130 22.695 438.550 92.960 ;
        RECT 518.780 92.910 520.200 92.960 ;
        RECT 523.880 59.105 527.750 108.720 ;
        RECT 532.670 94.380 534.090 94.430 ;
        RECT 707.770 94.380 709.190 94.430 ;
        RECT 532.670 92.960 709.190 94.380 ;
        RECT 532.670 92.910 534.090 92.960 ;
        RECT 541.500 80.050 542.960 81.610 ;
        RECT 555.030 76.510 556.450 92.960 ;
        RECT 707.770 92.910 709.190 92.960 ;
        RECT 582.470 83.950 590.800 86.550 ;
        RECT 582.480 82.010 584.570 83.950 ;
        RECT 582.390 81.470 584.640 82.010 ;
        RECT 588.690 81.850 590.800 83.950 ;
        RECT 576.470 78.170 578.630 80.870 ;
        RECT 576.440 77.570 578.630 78.170 ;
        RECT 559.480 76.510 560.900 76.560 ;
        RECT 555.030 75.090 560.900 76.510 ;
        RECT 576.470 75.550 578.630 77.570 ;
        RECT 559.480 75.040 560.900 75.090 ;
        RECT 576.450 74.950 578.630 75.550 ;
        RECT 576.470 72.560 578.630 74.950 ;
        RECT 582.410 79.330 584.610 81.470 ;
        RECT 588.630 81.370 590.800 81.850 ;
        RECT 588.690 79.390 590.800 81.370 ;
        RECT 616.990 80.960 619.010 82.110 ;
        RECT 594.070 79.980 596.170 80.610 ;
        RECT 582.410 78.840 584.630 79.330 ;
        RECT 588.630 78.890 590.800 79.390 ;
        RECT 582.410 73.660 584.610 78.840 ;
        RECT 588.690 76.780 590.800 78.890 ;
        RECT 594.100 78.150 596.100 79.980 ;
        RECT 594.070 77.520 596.170 78.150 ;
        RECT 588.690 76.280 590.840 76.780 ;
        RECT 588.690 74.190 590.800 76.280 ;
        RECT 594.100 75.490 596.100 77.520 ;
        RECT 594.090 74.860 596.190 75.490 ;
        RECT 653.470 75.300 654.750 76.680 ;
        RECT 588.680 73.690 590.830 74.190 ;
        RECT 588.690 73.640 590.800 73.690 ;
        RECT 594.100 72.560 596.100 74.860 ;
        RECT 606.720 74.040 609.070 74.490 ;
        RECT 576.470 71.890 596.100 72.560 ;
        RECT 576.510 71.080 596.100 71.890 ;
        RECT 576.510 70.800 637.630 71.080 ;
        RECT 576.510 70.560 639.190 70.800 ;
        RECT 577.190 66.810 578.700 67.550 ;
        RECT 579.720 67.240 585.490 70.560 ;
        RECT 593.300 69.190 639.190 70.560 ;
        RECT 580.460 67.010 584.850 67.240 ;
        RECT 590.750 66.850 592.530 67.580 ;
        RECT 593.300 67.200 599.070 69.190 ;
        RECT 616.480 67.480 618.090 67.530 ;
        RECT 594.040 66.930 598.230 67.200 ;
        RECT 616.400 66.890 618.090 67.480 ;
        RECT 618.860 67.140 625.570 69.190 ;
        RECT 630.470 67.400 632.080 67.550 ;
        RECT 619.560 66.940 625.250 67.140 ;
        RECT 630.380 66.910 632.080 67.400 ;
        RECT 632.480 67.100 639.190 69.190 ;
        RECT 633.260 67.020 638.950 67.100 ;
        RECT 561.135 59.105 565.005 59.155 ;
        RECT 523.880 55.235 565.005 59.105 ;
        RECT 561.135 55.185 565.005 55.235 ;
        RECT 577.300 47.030 578.620 66.810 ;
        RECT 577.240 46.440 578.680 47.030 ;
        RECT 579.870 43.540 581.950 57.370 ;
        RECT 590.800 47.090 592.330 66.850 ;
        RECT 595.550 56.520 598.100 57.290 ;
        RECT 590.710 46.360 592.490 47.090 ;
        RECT 595.730 43.540 597.910 56.520 ;
        RECT 616.400 47.060 618.070 66.890 ;
        RECT 624.580 57.000 626.860 57.310 ;
        RECT 624.580 56.310 627.010 57.000 ;
        RECT 616.340 46.530 618.070 47.060 ;
        RECT 616.340 46.420 617.950 46.530 ;
        RECT 624.730 44.990 627.010 56.310 ;
        RECT 630.380 47.060 632.050 66.910 ;
        RECT 633.410 56.300 636.140 57.240 ;
        RECT 630.380 46.450 632.140 47.060 ;
        RECT 630.530 46.420 632.140 46.450 ;
        RECT 633.510 45.080 635.870 56.300 ;
        RECT 633.510 44.990 637.800 45.080 ;
        RECT 624.730 43.790 637.800 44.990 ;
        RECT 471.890 41.170 554.910 42.590 ;
        RECT 471.890 35.420 473.310 41.170 ;
        RECT 471.810 33.180 473.420 35.420 ;
        RECT 437.085 21.350 438.550 22.695 ;
        RECT 471.890 21.740 473.310 33.180 ;
        RECT 437.085 21.145 438.535 21.350 ;
        RECT 471.995 21.260 473.185 21.740 ;
        RECT 500.890 21.390 502.200 37.995 ;
        RECT 540.250 22.605 541.630 32.640 ;
        RECT 500.925 21.260 502.115 21.390 ;
        RECT 540.205 21.315 541.630 22.605 ;
        RECT 540.250 21.310 541.630 21.315 ;
        RECT 553.490 22.340 554.910 41.170 ;
        RECT 579.870 41.440 597.910 43.540 ;
        RECT 624.800 43.150 637.800 43.790 ;
        RECT 635.170 43.120 637.800 43.150 ;
        RECT 579.870 41.400 597.800 41.440 ;
        RECT 579.870 39.850 581.950 41.400 ;
        RECT 571.110 38.560 581.950 39.850 ;
        RECT 571.110 37.690 581.930 38.560 ;
        RECT 571.110 32.670 573.750 37.690 ;
        RECT 635.290 36.440 637.800 43.120 ;
        RECT 644.520 43.010 645.990 44.540 ;
        RECT 641.320 37.780 642.670 37.920 ;
        RECT 640.880 36.440 643.130 37.780 ;
        RECT 659.850 37.510 661.510 39.270 ;
        RECT 713.960 37.980 716.620 113.650 ;
        RECT 878.505 111.575 881.195 111.625 ;
        RECT 732.020 108.885 881.195 111.575 ;
        RECT 719.690 94.380 721.110 94.430 ;
        RECT 726.340 94.380 727.760 94.430 ;
        RECT 719.690 92.960 727.780 94.380 ;
        RECT 719.690 92.910 721.110 92.960 ;
        RECT 726.340 92.910 727.760 92.960 ;
        RECT 732.020 78.065 734.710 108.885 ;
        RECT 878.505 108.835 881.195 108.885 ;
        RECT 738.980 94.380 740.400 94.430 ;
        RECT 738.980 92.960 745.140 94.380 ;
        RECT 738.980 92.910 740.400 92.960 ;
        RECT 732.020 76.200 734.775 78.065 ;
        RECT 732.165 75.355 734.775 76.200 ;
        RECT 743.720 77.120 745.140 92.960 ;
        RECT 773.930 83.950 782.260 86.550 ;
        RECT 773.940 82.010 776.030 83.950 ;
        RECT 773.850 81.470 776.100 82.010 ;
        RECT 780.150 81.850 782.260 83.950 ;
        RECT 767.930 78.170 770.090 80.870 ;
        RECT 767.900 77.570 770.090 78.170 ;
        RECT 756.460 77.120 757.880 77.170 ;
        RECT 743.720 75.700 757.880 77.120 ;
        RECT 756.460 75.650 757.880 75.700 ;
        RECT 767.930 75.550 770.090 77.570 ;
        RECT 767.910 74.950 770.090 75.550 ;
        RECT 767.930 72.560 770.090 74.950 ;
        RECT 773.870 79.330 776.070 81.470 ;
        RECT 780.090 81.370 782.260 81.850 ;
        RECT 780.150 79.390 782.260 81.370 ;
        RECT 808.450 80.960 810.470 82.110 ;
        RECT 785.530 79.980 787.630 80.610 ;
        RECT 773.870 78.840 776.090 79.330 ;
        RECT 780.090 78.890 782.260 79.390 ;
        RECT 773.870 73.660 776.070 78.840 ;
        RECT 780.150 76.780 782.260 78.890 ;
        RECT 785.560 78.150 787.560 79.980 ;
        RECT 785.530 77.520 787.630 78.150 ;
        RECT 780.150 76.280 782.300 76.780 ;
        RECT 780.150 74.190 782.260 76.280 ;
        RECT 785.560 75.490 787.560 77.520 ;
        RECT 785.550 74.860 787.650 75.490 ;
        RECT 845.390 74.980 846.670 76.360 ;
        RECT 878.345 76.355 881.535 79.645 ;
        RECT 780.140 73.690 782.290 74.190 ;
        RECT 780.150 73.640 782.260 73.690 ;
        RECT 785.560 72.560 787.560 74.860 ;
        RECT 798.180 74.040 800.530 74.490 ;
        RECT 767.930 71.890 787.560 72.560 ;
        RECT 767.970 71.080 787.560 71.890 ;
        RECT 767.970 70.800 829.090 71.080 ;
        RECT 767.970 70.560 830.650 70.800 ;
        RECT 768.650 66.810 770.160 67.550 ;
        RECT 771.180 67.240 776.950 70.560 ;
        RECT 784.760 69.190 830.650 70.560 ;
        RECT 771.920 67.010 776.310 67.240 ;
        RECT 782.210 66.850 783.990 67.580 ;
        RECT 784.760 67.200 790.530 69.190 ;
        RECT 807.940 67.480 809.550 67.530 ;
        RECT 785.500 66.930 789.690 67.200 ;
        RECT 807.860 66.890 809.550 67.480 ;
        RECT 810.320 67.140 817.030 69.190 ;
        RECT 821.930 67.400 823.540 67.550 ;
        RECT 811.020 66.940 816.710 67.140 ;
        RECT 821.840 66.910 823.540 67.400 ;
        RECT 823.940 67.100 830.650 69.190 ;
        RECT 824.720 67.020 830.410 67.100 ;
        RECT 768.760 47.030 770.080 66.810 ;
        RECT 768.700 46.440 770.140 47.030 ;
        RECT 771.330 43.540 773.410 57.370 ;
        RECT 782.260 47.090 783.790 66.850 ;
        RECT 787.010 56.520 789.560 57.290 ;
        RECT 782.170 46.360 783.950 47.090 ;
        RECT 787.190 43.540 789.370 56.520 ;
        RECT 807.860 47.060 809.530 66.890 ;
        RECT 816.040 57.000 818.320 57.310 ;
        RECT 816.040 56.310 818.470 57.000 ;
        RECT 807.800 46.530 809.530 47.060 ;
        RECT 807.800 46.420 809.410 46.530 ;
        RECT 816.190 44.990 818.470 56.310 ;
        RECT 821.840 47.060 823.510 66.910 ;
        RECT 824.870 56.300 827.600 57.240 ;
        RECT 821.840 46.450 823.600 47.060 ;
        RECT 821.990 46.420 823.600 46.450 ;
        RECT 824.970 45.080 827.330 56.300 ;
        RECT 845.270 55.340 847.320 55.390 ;
        RECT 866.395 55.340 869.585 56.275 ;
        RECT 845.270 53.290 869.585 55.340 ;
        RECT 845.270 53.240 847.320 53.290 ;
        RECT 866.395 52.985 869.585 53.290 ;
        RECT 824.970 44.990 829.260 45.080 ;
        RECT 816.190 43.790 829.260 44.990 ;
        RECT 771.330 41.440 789.370 43.540 ;
        RECT 816.260 43.150 829.260 43.790 ;
        RECT 826.630 43.120 829.260 43.150 ;
        RECT 771.330 41.400 789.260 41.440 ;
        RECT 771.330 39.850 773.410 41.400 ;
        RECT 762.570 38.560 773.410 39.850 ;
        RECT 762.570 37.690 773.390 38.560 ;
        RECT 580.560 34.980 582.290 35.410 ;
        RECT 635.290 34.460 643.430 36.440 ;
        RECT 636.850 34.420 643.430 34.460 ;
        RECT 580.470 33.940 582.420 34.090 ;
        RECT 580.370 33.680 582.420 33.940 ;
        RECT 580.370 32.670 582.380 33.680 ;
        RECT 640.880 32.790 643.130 34.420 ;
        RECT 571.110 29.590 582.710 32.670 ;
        RECT 641.470 32.590 642.700 32.790 ;
        RECT 762.570 32.670 765.210 37.690 ;
        RECT 826.750 36.440 829.260 43.120 ;
        RECT 835.980 43.010 837.450 44.540 ;
        RECT 832.780 37.780 834.130 37.920 ;
        RECT 832.340 36.440 834.590 37.780 ;
        RECT 846.230 37.440 847.770 39.080 ;
        RECT 772.020 34.980 773.750 35.410 ;
        RECT 826.750 34.460 834.890 36.440 ;
        RECT 828.310 34.420 834.890 34.460 ;
        RECT 771.930 33.940 773.880 34.090 ;
        RECT 771.830 33.680 773.880 33.940 ;
        RECT 771.830 32.670 773.840 33.680 ;
        RECT 832.340 32.790 834.590 34.420 ;
        RECT 762.570 29.590 774.170 32.670 ;
        RECT 832.930 32.590 834.160 32.790 ;
        RECT 571.180 29.550 582.710 29.590 ;
        RECT 762.640 29.550 774.170 29.590 ;
        RECT 580.370 27.770 582.380 29.550 ;
        RECT 771.830 27.770 773.840 29.550 ;
        RECT 580.420 27.640 582.370 27.770 ;
        RECT 771.880 27.640 773.830 27.770 ;
        RECT 583.720 22.340 585.140 23.480 ;
        RECT 553.490 20.920 585.140 22.340 ;
        RECT 758.050 21.055 759.720 21.210 ;
        RECT 775.045 21.055 776.715 23.555 ;
        RECT 553.490 20.900 554.910 20.920 ;
        RECT 378.475 16.865 419.190 18.475 ;
        RECT 758.050 19.385 776.715 21.055 ;
        RECT 758.050 17.925 759.720 19.385 ;
        RECT 758.045 16.670 759.720 17.925 ;
        RECT 1.000 1.555 161.000 16.160 ;
        RECT 758.045 16.155 759.715 16.670 ;
      LAYER met3 ;
        RECT 0.950 105.210 161.000 216.925 ;
        RECT 294.040 215.475 296.160 216.575 ;
        RECT 523.650 215.825 525.770 216.925 ;
        RECT 283.770 208.800 286.220 208.955 ;
        RECT 283.350 207.450 286.410 208.800 ;
        RECT 294.220 207.450 295.910 215.475 ;
        RECT 332.500 209.655 333.880 210.985 ;
        RECT 513.380 209.150 515.830 209.305 ;
        RECT 512.960 207.800 516.020 209.150 ;
        RECT 523.830 207.800 525.520 215.825 ;
        RECT 563.890 210.065 565.270 211.395 ;
        RECT 512.960 207.660 525.520 207.800 ;
        RECT 283.350 207.310 295.910 207.450 ;
        RECT 283.320 206.560 295.910 207.310 ;
        RECT 283.320 206.370 286.410 206.560 ;
        RECT 294.220 206.520 295.910 206.560 ;
        RECT 512.930 206.910 525.520 207.660 ;
        RECT 512.930 206.720 516.020 206.910 ;
        RECT 523.830 206.870 525.520 206.910 ;
        RECT 257.690 177.780 260.620 177.830 ;
        RECT 283.320 177.780 286.330 206.370 ;
        RECT 329.720 182.130 365.250 184.370 ;
        RECT 257.690 175.850 286.330 177.780 ;
        RECT 321.570 177.525 323.140 179.005 ;
        RECT 257.690 175.790 284.910 175.850 ;
        RECT 257.690 169.875 260.620 175.790 ;
        RECT 257.610 169.600 260.620 169.875 ;
        RECT 257.610 169.495 259.440 169.600 ;
        RECT 250.820 164.305 253.130 165.605 ;
        RECT 263.260 150.000 286.060 174.260 ;
        RECT 287.260 150.000 310.060 174.260 ;
        RECT 336.860 171.855 338.500 173.445 ;
        RECT 179.850 124.735 182.210 127.045 ;
        RECT 336.910 105.210 338.450 171.855 ;
        RECT 363.010 156.090 365.250 182.130 ;
        RECT 487.300 178.130 490.230 178.180 ;
        RECT 512.930 178.130 515.940 206.720 ;
        RECT 714.090 195.925 716.470 198.255 ;
        RECT 734.710 183.740 766.570 214.140 ;
        RECT 767.770 183.740 799.630 214.140 ;
        RECT 800.830 183.740 832.690 214.140 ;
        RECT 487.300 176.200 515.940 178.130 ;
        RECT 551.180 177.875 552.750 179.355 ;
        RECT 487.300 176.140 514.520 176.200 ;
        RECT 487.300 170.225 490.230 176.140 ;
        RECT 487.220 169.950 490.230 170.225 ;
        RECT 487.220 169.845 489.050 169.950 ;
        RECT 480.430 164.655 482.740 165.955 ;
        RECT 433.190 164.305 435.430 164.340 ;
        RECT 433.150 162.275 435.430 164.305 ;
        RECT 433.190 156.090 435.430 162.275 ;
        RECT 363.010 153.850 435.430 156.090 ;
        RECT 433.190 128.460 435.430 153.850 ;
        RECT 492.870 150.350 515.670 174.610 ;
        RECT 516.870 150.350 539.670 174.610 ;
        RECT 574.080 172.205 575.720 173.795 ;
        RECT 574.130 130.700 575.670 172.205 ;
        RECT 679.380 166.370 684.240 166.655 ;
        RECT 679.380 161.845 684.500 166.370 ;
        RECT 679.650 145.775 684.500 161.845 ;
        RECT 734.710 152.140 766.570 182.540 ;
        RECT 767.770 152.140 799.630 182.540 ;
        RECT 800.830 152.140 832.690 182.540 ;
        RECT 876.155 158.955 881.105 158.980 ;
        RECT 847.905 151.890 851.195 155.130 ;
        RECT 870.040 154.105 881.105 158.955 ;
        RECT 870.040 145.775 874.890 154.105 ;
        RECT 876.155 154.080 881.105 154.105 ;
        RECT 679.650 140.925 874.890 145.775 ;
        RECT 573.860 128.460 575.670 130.700 ;
        RECT 433.190 126.220 547.470 128.460 ;
        RECT 371.540 122.375 374.820 125.605 ;
        RECT 545.230 113.205 547.470 126.220 ;
        RECT 555.890 118.595 559.440 122.625 ;
        RECT 545.180 110.915 547.520 113.205 ;
        RECT 541.530 105.210 543.070 105.520 ;
        RECT 574.130 105.210 575.670 128.460 ;
        RECT 0.950 103.670 858.570 105.210 ;
        RECT 0.950 1.580 161.000 103.670 ;
        RECT 342.550 81.135 344.670 82.235 ;
        RECT 332.280 74.460 334.730 74.615 ;
        RECT 331.860 73.110 334.920 74.460 ;
        RECT 342.730 73.110 344.420 81.135 ;
        RECT 378.330 75.315 379.710 76.645 ;
        RECT 331.860 72.970 344.420 73.110 ;
        RECT 331.830 72.220 344.420 72.970 ;
        RECT 331.830 72.030 334.920 72.220 ;
        RECT 342.730 72.180 344.420 72.220 ;
        RECT 306.200 43.440 309.130 43.490 ;
        RECT 331.830 43.440 334.840 72.030 ;
        RECT 306.200 41.510 334.840 43.440 ;
        RECT 370.080 43.185 371.650 44.665 ;
        RECT 306.200 41.450 333.420 41.510 ;
        RECT 306.200 35.535 309.130 41.450 ;
        RECT 306.120 35.260 309.130 35.535 ;
        RECT 306.120 35.155 307.950 35.260 ;
        RECT 299.330 29.965 301.640 31.265 ;
        RECT 208.700 20.555 211.265 23.070 ;
        RECT 311.770 15.660 334.570 39.920 ;
        RECT 335.770 15.660 358.570 39.920 ;
        RECT 383.700 39.185 385.240 103.670 ;
        RECT 541.530 81.585 543.070 103.670 ;
        RECT 541.450 80.140 543.070 81.585 ;
        RECT 616.940 80.985 619.060 82.085 ;
        RECT 541.450 80.075 543.010 80.140 ;
        RECT 606.670 74.310 609.120 74.465 ;
        RECT 606.250 72.960 609.310 74.310 ;
        RECT 617.120 72.960 618.810 80.985 ;
        RECT 653.420 75.325 654.800 76.655 ;
        RECT 606.250 72.820 618.810 72.960 ;
        RECT 606.220 72.070 618.810 72.820 ;
        RECT 606.220 71.880 609.310 72.070 ;
        RECT 617.120 72.030 618.810 72.070 ;
        RECT 580.590 43.290 583.520 43.340 ;
        RECT 606.220 43.290 609.230 71.880 ;
        RECT 580.590 41.360 609.230 43.290 ;
        RECT 644.470 43.035 646.040 44.515 ;
        RECT 580.590 41.300 607.810 41.360 ;
        RECT 383.650 37.595 385.290 39.185 ;
        RECT 580.590 35.385 583.520 41.300 ;
        RECT 580.510 35.110 583.520 35.385 ;
        RECT 580.510 35.005 582.340 35.110 ;
        RECT 540.200 31.185 541.680 32.615 ;
        RECT 573.720 29.815 576.030 31.115 ;
        RECT 586.160 15.510 608.960 39.770 ;
        RECT 610.160 15.510 632.960 39.770 ;
        RECT 660.070 39.245 661.610 103.670 ;
        RECT 808.400 80.985 810.520 82.085 ;
        RECT 798.130 74.310 800.580 74.465 ;
        RECT 797.710 72.960 800.770 74.310 ;
        RECT 808.580 72.960 810.270 80.985 ;
        RECT 845.340 75.005 846.720 76.335 ;
        RECT 797.710 72.820 810.270 72.960 ;
        RECT 797.680 72.070 810.270 72.820 ;
        RECT 797.680 71.880 800.770 72.070 ;
        RECT 808.580 72.030 810.270 72.070 ;
        RECT 659.800 37.980 661.610 39.245 ;
        RECT 772.050 43.290 774.980 43.340 ;
        RECT 797.680 43.290 800.690 71.880 ;
        RECT 772.050 41.360 800.690 43.290 ;
        RECT 835.930 43.035 837.500 44.515 ;
        RECT 772.050 41.300 799.270 41.360 ;
        RECT 659.800 37.535 661.560 37.980 ;
        RECT 772.050 35.385 774.980 41.300 ;
        RECT 771.970 35.110 774.980 35.385 ;
        RECT 771.970 35.005 773.800 35.110 ;
        RECT 765.180 29.815 767.490 31.115 ;
        RECT 777.620 15.510 800.420 39.770 ;
        RECT 801.620 15.510 824.420 39.770 ;
        RECT 846.180 39.030 847.820 39.055 ;
        RECT 857.030 39.030 858.570 103.670 ;
        RECT 878.295 76.380 881.585 79.620 ;
        RECT 846.180 37.490 858.570 39.030 ;
        RECT 846.180 37.465 847.820 37.490 ;
      LAYER met4 ;
        RECT 0.995 224.360 30.270 225.410 ;
        RECT 31.370 224.360 33.030 225.410 ;
        RECT 34.130 224.360 35.790 225.410 ;
        RECT 36.890 224.360 38.550 225.410 ;
        RECT 39.650 224.360 41.310 225.410 ;
        RECT 42.410 224.360 44.070 225.410 ;
        RECT 45.170 224.360 46.830 225.410 ;
        RECT 47.930 224.360 49.590 225.410 ;
        RECT 50.690 224.360 52.350 225.410 ;
        RECT 53.450 224.360 55.110 225.410 ;
        RECT 56.210 224.360 57.870 225.410 ;
        RECT 58.970 224.360 60.630 225.410 ;
        RECT 61.730 224.360 63.390 225.410 ;
        RECT 64.490 224.360 66.150 225.410 ;
        RECT 67.250 224.360 68.910 225.410 ;
        RECT 70.010 224.360 71.670 225.410 ;
        RECT 72.770 224.360 74.430 225.410 ;
        RECT 75.530 224.360 77.190 225.410 ;
        RECT 78.290 224.360 79.950 225.410 ;
        RECT 81.050 224.360 82.710 225.410 ;
        RECT 83.810 224.360 85.470 225.410 ;
        RECT 86.570 224.360 88.230 225.410 ;
        RECT 89.330 224.360 90.990 225.410 ;
        RECT 92.090 224.360 93.750 225.410 ;
        RECT 94.850 224.360 96.510 225.410 ;
        RECT 97.610 224.360 99.270 225.410 ;
        RECT 100.370 224.360 102.030 225.410 ;
        RECT 103.130 224.360 104.790 225.410 ;
        RECT 105.890 224.360 107.550 225.410 ;
        RECT 108.650 224.360 110.310 225.410 ;
        RECT 111.410 224.360 113.070 225.410 ;
        RECT 114.170 224.360 115.830 225.410 ;
        RECT 116.930 224.360 118.590 225.410 ;
        RECT 119.690 224.360 121.350 225.410 ;
        RECT 122.450 224.360 124.110 225.410 ;
        RECT 125.210 224.360 126.870 225.410 ;
        RECT 127.970 224.360 129.630 225.410 ;
        RECT 130.730 224.360 132.390 225.410 ;
        RECT 133.490 224.360 135.150 225.410 ;
        RECT 136.250 224.360 137.910 225.410 ;
        RECT 139.010 224.360 140.670 225.410 ;
        RECT 141.770 224.360 143.430 225.410 ;
        RECT 144.530 224.360 146.190 225.410 ;
        RECT 147.290 224.360 161.000 225.410 ;
        RECT 0.995 221.160 161.000 224.360 ;
        RECT 3.400 4.600 3.600 221.160 ;
        RECT 6.400 97.170 161.000 221.160 ;
        RECT 714.140 217.610 749.880 217.850 ;
        RECT 750.310 217.610 752.770 217.840 ;
        RECT 714.140 217.090 816.290 217.610 ;
        RECT 714.140 215.570 750.120 217.090 ;
        RECT 563.935 211.370 565.225 211.375 ;
        RECT 332.545 210.960 333.835 210.965 ;
        RECT 332.545 209.680 345.440 210.960 ;
        RECT 563.935 210.090 581.410 211.370 ;
        RECT 563.935 210.085 565.225 210.090 ;
        RECT 332.545 209.675 333.835 209.680 ;
        RECT 329.765 184.170 332.015 184.375 ;
        RECT 329.765 182.125 332.090 184.170 ;
        RECT 322.050 179.150 323.900 179.170 ;
        RECT 322.050 178.985 324.790 179.150 ;
        RECT 321.615 177.545 324.790 178.985 ;
        RECT 322.050 177.270 324.790 177.545 ;
        RECT 250.865 164.325 253.085 165.585 ;
        RECT 251.030 151.220 252.780 164.325 ;
        RECT 263.655 163.120 285.665 173.865 ;
        RECT 287.655 163.120 309.665 173.865 ;
        RECT 322.920 163.760 324.790 177.270 ;
        RECT 329.830 171.120 332.090 182.125 ;
        RECT 329.830 168.860 335.190 171.120 ;
        RECT 321.080 163.710 324.790 163.760 ;
        RECT 311.250 163.700 324.790 163.710 ;
        RECT 310.360 163.120 324.790 163.700 ;
        RECT 262.660 162.600 324.790 163.120 ;
        RECT 263.655 151.855 285.665 162.600 ;
        RECT 287.655 151.855 309.665 162.600 ;
        RECT 310.360 162.220 324.790 162.600 ;
        RECT 310.360 162.200 311.920 162.220 ;
        RECT 321.080 162.200 324.790 162.220 ;
        RECT 332.930 157.630 335.190 168.860 ;
        RECT 324.260 155.370 335.190 157.630 ;
        RECT 255.130 151.220 263.070 151.280 ;
        RECT 251.030 150.520 263.070 151.220 ;
        RECT 251.030 150.000 310.660 150.520 ;
        RECT 251.030 149.220 263.070 150.000 ;
        RECT 251.030 149.160 252.780 149.220 ;
        RECT 324.260 141.070 326.520 155.370 ;
        RECT 179.900 138.810 326.520 141.070 ;
        RECT 179.900 127.025 182.160 138.810 ;
        RECT 179.895 124.755 182.165 127.025 ;
        RECT 344.160 97.170 345.440 209.680 ;
        RECT 551.660 179.500 553.510 179.520 ;
        RECT 551.660 179.335 554.400 179.500 ;
        RECT 551.225 177.895 554.400 179.335 ;
        RECT 551.660 177.620 554.400 177.895 ;
        RECT 480.475 164.675 482.695 165.935 ;
        RECT 480.640 151.570 482.390 164.675 ;
        RECT 493.265 163.470 515.275 174.215 ;
        RECT 517.265 163.470 539.275 174.215 ;
        RECT 552.530 164.110 554.400 177.620 ;
        RECT 550.690 164.060 554.400 164.110 ;
        RECT 540.860 164.050 554.400 164.060 ;
        RECT 539.970 163.470 554.400 164.050 ;
        RECT 492.270 162.950 554.400 163.470 ;
        RECT 493.265 152.205 515.275 162.950 ;
        RECT 517.265 152.205 539.275 162.950 ;
        RECT 539.970 162.570 554.400 162.950 ;
        RECT 539.970 162.550 541.530 162.570 ;
        RECT 550.690 162.550 554.400 162.570 ;
        RECT 484.740 151.570 492.680 151.630 ;
        RECT 480.640 150.870 492.680 151.570 ;
        RECT 480.640 150.350 540.270 150.870 ;
        RECT 480.640 149.570 492.680 150.350 ;
        RECT 480.640 149.510 482.390 149.570 ;
        RECT 371.590 131.550 423.810 134.730 ;
        RECT 371.590 125.585 374.770 131.550 ;
        RECT 371.585 122.395 374.775 125.585 ;
        RECT 420.630 122.160 423.810 131.550 ;
        RECT 555.935 122.160 559.395 122.605 ;
        RECT 420.630 118.980 559.395 122.160 ;
        RECT 555.935 118.615 559.395 118.980 ;
        RECT 580.130 97.170 581.410 210.090 ;
        RECT 714.140 198.235 716.420 215.570 ;
        RECT 749.600 214.740 750.120 215.570 ;
        RECT 749.600 214.360 750.170 214.740 ;
        RECT 749.650 213.745 750.170 214.360 ;
        RECT 714.135 195.945 716.425 198.235 ;
        RECT 735.105 184.135 764.715 213.745 ;
        RECT 749.650 182.145 750.170 184.135 ;
        RECT 735.105 152.535 764.715 182.145 ;
        RECT 749.650 151.540 750.170 152.535 ;
        RECT 766.050 150.040 766.570 214.740 ;
        RECT 782.710 213.745 783.230 217.090 ;
        RECT 768.165 184.135 797.775 213.745 ;
        RECT 782.710 182.145 783.230 184.135 ;
        RECT 768.165 152.535 797.775 182.145 ;
        RECT 782.710 151.540 783.230 152.535 ;
        RECT 799.110 150.040 799.630 214.740 ;
        RECT 815.770 213.745 816.290 217.090 ;
        RECT 801.225 184.135 830.835 213.745 ;
        RECT 815.770 182.145 816.290 184.135 ;
        RECT 801.225 152.535 830.835 182.145 ;
        RECT 815.770 151.540 816.290 152.535 ;
        RECT 832.170 151.830 832.690 214.740 ;
        RECT 845.080 155.110 850.040 155.200 ;
        RECT 845.080 154.945 851.150 155.110 ;
        RECT 832.090 151.540 832.690 151.830 ;
        RECT 840.185 152.070 851.150 154.945 ;
        RECT 832.090 151.130 832.610 151.540 ;
        RECT 840.185 151.130 843.060 152.070 ;
        RECT 847.950 151.910 851.150 152.070 ;
        RECT 826.605 150.040 829.775 150.125 ;
        RECT 832.090 150.040 843.060 151.130 ;
        RECT 766.050 149.520 843.060 150.040 ;
        RECT 826.605 149.500 829.775 149.520 ;
        RECT 832.510 149.325 843.060 149.520 ;
        RECT 832.510 149.260 842.470 149.325 ;
        RECT 6.400 95.890 846.670 97.170 ;
        RECT 6.400 23.585 161.000 95.890 ;
        RECT 378.380 76.625 379.660 95.890 ;
        RECT 378.375 75.335 379.665 76.625 ;
        RECT 540.320 46.190 541.600 46.270 ;
        RECT 549.000 46.190 550.280 95.890 ;
        RECT 653.470 76.635 654.750 95.890 ;
        RECT 653.465 75.345 654.755 76.635 ;
        RECT 845.390 76.315 846.670 95.890 ;
        RECT 878.340 78.570 881.540 79.600 ;
        RECT 877.370 76.400 881.540 78.570 ;
        RECT 845.385 75.025 846.675 76.315 ;
        RECT 540.320 44.910 550.280 46.190 ;
        RECT 370.560 44.810 372.410 44.830 ;
        RECT 370.560 44.645 373.300 44.810 ;
        RECT 370.125 43.205 373.300 44.645 ;
        RECT 370.560 42.930 373.300 43.205 ;
        RECT 299.375 29.985 301.595 31.245 ;
        RECT 6.400 20.175 211.765 23.585 ;
        RECT 6.400 4.900 161.000 20.175 ;
        RECT 299.540 16.880 301.290 29.985 ;
        RECT 312.165 28.780 334.175 39.525 ;
        RECT 336.165 28.780 358.175 39.525 ;
        RECT 371.430 29.420 373.300 42.930 ;
        RECT 540.320 32.595 541.600 44.910 ;
        RECT 644.950 44.660 646.800 44.680 ;
        RECT 836.410 44.660 838.260 44.680 ;
        RECT 644.950 44.495 647.690 44.660 ;
        RECT 836.410 44.495 839.150 44.660 ;
        RECT 644.515 43.055 647.690 44.495 ;
        RECT 835.975 43.055 839.150 44.495 ;
        RECT 644.950 42.780 647.690 43.055 ;
        RECT 836.410 42.780 839.150 43.055 ;
        RECT 540.245 31.205 541.635 32.595 ;
        RECT 573.765 29.835 575.985 31.095 ;
        RECT 369.590 29.370 373.300 29.420 ;
        RECT 359.760 29.360 373.300 29.370 ;
        RECT 358.870 28.780 373.300 29.360 ;
        RECT 311.170 28.260 373.300 28.780 ;
        RECT 312.165 17.515 334.175 28.260 ;
        RECT 336.165 17.515 358.175 28.260 ;
        RECT 358.870 27.880 373.300 28.260 ;
        RECT 358.870 27.860 360.430 27.880 ;
        RECT 369.590 27.860 373.300 27.880 ;
        RECT 303.640 16.880 311.580 16.940 ;
        RECT 299.540 16.180 311.580 16.880 ;
        RECT 573.930 16.730 575.680 29.835 ;
        RECT 586.555 28.630 608.565 39.375 ;
        RECT 610.555 28.630 632.565 39.375 ;
        RECT 645.820 29.270 647.690 42.780 ;
        RECT 765.225 29.835 767.445 31.095 ;
        RECT 643.980 29.220 647.690 29.270 ;
        RECT 634.150 29.210 647.690 29.220 ;
        RECT 633.260 28.630 647.690 29.210 ;
        RECT 585.560 28.110 647.690 28.630 ;
        RECT 586.555 17.365 608.565 28.110 ;
        RECT 610.555 17.365 632.565 28.110 ;
        RECT 633.260 27.730 647.690 28.110 ;
        RECT 633.260 27.710 634.820 27.730 ;
        RECT 643.980 27.710 647.690 27.730 ;
        RECT 578.030 16.730 585.970 16.790 ;
        RECT 299.540 15.660 359.170 16.180 ;
        RECT 573.930 16.030 585.970 16.730 ;
        RECT 765.390 16.730 767.140 29.835 ;
        RECT 778.015 28.630 800.025 39.375 ;
        RECT 802.015 28.630 824.025 39.375 ;
        RECT 837.280 29.270 839.150 42.780 ;
        RECT 835.440 29.220 839.150 29.270 ;
        RECT 825.610 29.210 839.150 29.220 ;
        RECT 824.720 28.630 839.150 29.210 ;
        RECT 777.020 28.110 839.150 28.630 ;
        RECT 778.015 17.365 800.025 28.110 ;
        RECT 802.015 17.365 824.025 28.110 ;
        RECT 824.720 27.730 839.150 28.110 ;
        RECT 824.720 27.710 826.280 27.730 ;
        RECT 835.440 27.710 839.150 27.730 ;
        RECT 769.490 16.730 777.430 16.790 ;
        RECT 765.390 16.030 777.430 16.730 ;
        RECT 299.540 14.880 311.580 15.660 ;
        RECT 573.930 15.510 633.560 16.030 ;
        RECT 765.390 15.510 825.020 16.030 ;
        RECT 299.540 14.820 301.290 14.880 ;
        RECT 573.930 14.730 585.970 15.510 ;
        RECT 765.390 14.730 777.430 15.510 ;
        RECT 573.930 14.670 575.680 14.730 ;
        RECT 765.390 14.670 767.140 14.730 ;
        RECT 877.370 4.900 881.170 76.400 ;
        RECT 6.400 4.600 881.170 4.900 ;
        RECT 0.995 1.400 881.170 4.600 ;
        RECT 0.995 0.230 16.170 1.400 ;
        RECT 17.870 0.230 35.490 1.400 ;
        RECT 37.190 0.230 54.810 1.400 ;
        RECT 56.510 0.230 74.130 1.400 ;
        RECT 75.830 0.230 93.450 1.400 ;
        RECT 95.150 0.230 112.770 1.400 ;
        RECT 114.470 0.230 132.090 1.400 ;
        RECT 133.790 1.100 881.170 1.400 ;
        RECT 133.790 0.230 151.410 1.100 ;
        RECT 153.110 0.230 161.000 1.100 ;
  END
END tt_um_NE567Mixer28
END LIBRARY

